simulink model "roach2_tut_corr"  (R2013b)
settings: Solver=VariableStepDiscrete  SolverMode=SingleTasking  StartTime=0.0  StopTime=100  RelTol=1e-3
undefined symbols (not defined in the file): add_latency, addr_width, Bit, bitfield, BitWidth, bram_latency, burst_size, casper_library_scopes, conv_latency, data_width, DelayLen, fan_latency, FFTSize, FFTStage, getfield, increment, led, Location, Lower, mult_latency, mux_latency, n_bits, n_bits_data, n_inputs, n_streams, n_taps, neg_latency, negate_latency, nsamples, pfb_size, pulse_len, reset_period, ROACH, ROACH2, snapshot, sx475t, sync_period, sync_period_bits, Upper, UseCounter, Width
libraries: xbsIndex_r4 x24444, casper_library_misc x73, xbsReplacements_r4 x34, casper_library_delays x14, xps_library x7
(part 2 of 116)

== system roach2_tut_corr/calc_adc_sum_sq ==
  In1 : Inport
  In2 : Inport  Port=2
  In3 : Inport  Port=3
  In4 : Inport  Port=4
  Accumulator : xbsIndex_r4/Accumulator  operation=Add  n_bits=32  overflow=Wrap  scale=1  rst=on  infoeditControl=reset for floating point data type must be asserted for a minimum of 2 cycles  hasbypass=off  en=off  latency=0  dbl_ovrd=off  msb_inp=100  msb=100  lsb=-100  use_behavioral_HDL=on  implementation=Fabric  block_type=accum
  Convert1 : xbsIndex_r4/Convert  gui_display_data_type=Fixed-point  arith_type=Unsigned  n_bits=32  bin_pt=0  float_type=Single  exp_bits=8  fraction_bits=24  quantization=Truncate  overflow=Wrap  en=off  latency=0  dbl_ovrd=off  pipeline=off  block_type=convert
  Convert2 : xbsIndex_r4/Convert  gui_display_data_type=Boolean  arith_type=Boolean  n_bits=32  bin_pt=0  float_type=Single  exp_bits=8  fraction_bits=24  quantization=Truncate  overflow=Wrap  en=off  latency=0  dbl_ovrd=off  pipeline=off  block_type=convert
  Counter : xbsIndex_r4/Counter  cnt_type=Free Running  cnt_to=Inf  operation=Up  start_count=0  cnt_by_val=1  arith_type=Unsigned  n_bits=2  bin_pt=0  load_pin=off  rst=off  en=off  explicit_period=off  period=1  dbl_ovrd=off  use_behavioral_HDL=off  implementation=Fabric  use_rpm=on  block_type=counter
  Counter1 : xbsIndex_r4/Counter  cnt_type=Free Running  cnt_to=Inf  operation=Up  start_count=0  cnt_by_val=1  arith_type=Unsigned  n_bits=16  bin_pt=0  load_pin=off  rst=off  en=off  explicit_period=off  period=1  dbl_ovrd=off  use_behavioral_HDL=off  implementation=Fabric  use_rpm=on  block_type=counter
  Mult : xbsIndex_r4/Mult  precision=Full  arith_type="Signed  (2's comp)"  n_bits=8  bin_pt=2  quantization=Truncate  overflow=Wrap  en=off  latency=2  dbl_ovrd=off  use_behavioral_HDL=on  opt=Speed  use_embedded=on  optimum_pipeline=off  pipeline=on  use_rpm=on  placement_style=Rectangular shape  block_type=mult
  Mux : xbsIndex_r4/Mux  inputs=4  en=off  latency=1  precision=Full  arith_type="Signed  (2's comp)"  n_bits=8  bin_pt=2  quantization=Truncate  overflow=Wrap  dbl_ovrd=off  block_type=mux
  Register : xbsIndex_r4/Register  init=0  rst=off  en=on  dbl_ovrd=off  block_type=register
  Slice : xbsIndex_r4/Slice  nbits=1  boolean_output=off  mode=Upper Bit Location + Width  bit1=0  base1=MSB of Input  bit0=0  base0=LSB of Input  dbl_ovrd=off  block_type=slice
  edge_detect2 : Subsystem  AncestorBlock=casper_library_misc/edge_detect
  sum_sq : Outport
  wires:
  Mult/1 -> Accumulator/1
  Accumulator/1 -> Register/1
  Register/1 -> Convert1/1
  Mux/1 -> Mult/1, Mult/2
  Counter/1 -> Mux/1
  Counter1/1 -> Slice/1
  Slice/1 -> edge_detect2/1(in)
  edge_detect2/1(out) -> Convert2/1
  In1/1 -> Mux/2
  In3/1 -> Mux/3
  In2/1 -> Mux/4
  In4/1 -> Mux/5
  Convert1/1 -> sum_sq/1
  Convert2/1 -> Accumulator/2, Register/2

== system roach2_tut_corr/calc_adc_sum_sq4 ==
  In1 : Inport
  In2 : Inport  Port=2
  In3 : Inport  Port=3
  In4 : Inport  Port=4
  Accumulator : xbsIndex_r4/Accumulator  operation=Add  n_bits=32  overflow=Wrap  scale=1  rst=on  infoeditControl=reset for floating point data type must be asserted for a minimum of 2 cycles  hasbypass=off  en=off  latency=0  dbl_ovrd=off  msb_inp=100  msb=100  lsb=-100  use_behavioral_HDL=on  implementation=Fabric  block_type=accum
  Convert1 : xbsIndex_r4/Convert  gui_display_data_type=Fixed-point  arith_type=Unsigned  n_bits=32  bin_pt=0  float_type=Single  exp_bits=8  fraction_bits=24  quantization=Truncate  overflow=Wrap  en=off  latency=0  dbl_ovrd=off  pipeline=off  block_type=convert
  Convert2 : xbsIndex_r4/Convert  gui_display_data_type=Boolean  arith_type=Boolean  n_bits=32  bin_pt=0  float_type=Single  exp_bits=8  fraction_bits=24  quantization=Truncate  overflow=Wrap  en=off  latency=0  dbl_ovrd=off  pipeline=off  block_type=convert
  Counter : xbsIndex_r4/Counter  cnt_type=Free Running  cnt_to=Inf  operation=Up  start_count=0  cnt_by_val=1  arith_type=Unsigned  n_bits=2  bin_pt=0  load_pin=off  rst=off  en=off  explicit_period=off  period=1  dbl_ovrd=off  use_behavioral_HDL=off  implementation=Fabric  use_rpm=on  block_type=counter
  Counter1 : xbsIndex_r4/Counter  cnt_type=Free Running  cnt_to=Inf  operation=Up  start_count=0  cnt_by_val=1  arith_type=Unsigned  n_bits=16  bin_pt=0  load_pin=off  rst=off  en=off  explicit_period=off  period=1  dbl_ovrd=off  use_behavioral_HDL=off  implementation=Fabric  use_rpm=on  block_type=counter
  Mult : xbsIndex_r4/Mult  precision=Full  arith_type="Signed  (2's comp)"  n_bits=8  bin_pt=2  quantization=Truncate  overflow=Wrap  en=off  latency=2  dbl_ovrd=off  use_behavioral_HDL=on  opt=Speed  use_embedded=on  optimum_pipeline=off  pipeline=on  use_rpm=on  placement_style=Rectangular shape  block_type=mult
  Mux : xbsIndex_r4/Mux  inputs=4  en=off  latency=1  precision=Full  arith_type="Signed  (2's comp)"  n_bits=8  bin_pt=2  quantization=Truncate  overflow=Wrap  dbl_ovrd=off  block_type=mux
  Register : xbsIndex_r4/Register  init=0  rst=off  en=on  dbl_ovrd=off  block_type=register
  Slice : xbsIndex_r4/Slice  nbits=1  boolean_output=off  mode=Upper Bit Location + Width  bit1=0  base1=MSB of Input  bit0=0  base0=LSB of Input  dbl_ovrd=off  block_type=slice
  edge_detect2 : Subsystem  AncestorBlock=casper_library_misc/edge_detect
  sum_sq : Outport
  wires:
  Convert1/1 -> sum_sq/1
  In4/1 -> Mux/5
  In2/1 -> Mux/4
  In3/1 -> Mux/3
  In1/1 -> Mux/2
  edge_detect2/1(out) -> Convert2/1
  Slice/1 -> edge_detect2/1(in)
  Counter1/1 -> Slice/1
  Counter/1 -> Mux/1
  Mux/1 -> Mult/2, Mult/1
  Register/1 -> Convert1/1
  Accumulator/1 -> Register/1
  Mult/1 -> Accumulator/1
  Convert2/1 -> Register/2, Accumulator/2

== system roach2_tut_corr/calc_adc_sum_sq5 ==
  In1 : Inport
  In2 : Inport  Port=2
  In3 : Inport  Port=3
  In4 : Inport  Port=4
  Accumulator : xbsIndex_r4/Accumulator  operation=Add  n_bits=32  overflow=Wrap  scale=1  rst=on  infoeditControl=reset for floating point data type must be asserted for a minimum of 2 cycles  hasbypass=off  en=off  latency=0  dbl_ovrd=off  msb_inp=100  msb=100  lsb=-100  use_behavioral_HDL=on  implementation=Fabric  block_type=accum
  Convert1 : xbsIndex_r4/Convert  gui_display_data_type=Fixed-point  arith_type=Unsigned  n_bits=32  bin_pt=0  float_type=Single  exp_bits=8  fraction_bits=24  quantization=Truncate  overflow=Wrap  en=off  latency=0  dbl_ovrd=off  pipeline=off  block_type=convert
  Convert2 : xbsIndex_r4/Convert  gui_display_data_type=Boolean  arith_type=Boolean  n_bits=32  bin_pt=0  float_type=Single  exp_bits=8  fraction_bits=24  quantization=Truncate  overflow=Wrap  en=off  latency=0  dbl_ovrd=off  pipeline=off  block_type=convert
  Counter : xbsIndex_r4/Counter  cnt_type=Free Running  cnt_to=Inf  operation=Up  start_count=0  cnt_by_val=1  arith_type=Unsigned  n_bits=2  bin_pt=0  load_pin=off  rst=off  en=off  explicit_period=off  period=1  dbl_ovrd=off  use_behavioral_HDL=off  implementation=Fabric  use_rpm=on  block_type=counter
  Counter1 : xbsIndex_r4/Counter  cnt_type=Free Running  cnt_to=Inf  operation=Up  start_count=0  cnt_by_val=1  arith_type=Unsigned  n_bits=16  bin_pt=0  load_pin=off  rst=off  en=off  explicit_period=off  period=1  dbl_ovrd=off  use_behavioral_HDL=off  implementation=Fabric  use_rpm=on  block_type=counter
  Mult : xbsIndex_r4/Mult  precision=Full  arith_type="Signed  (2's comp)"  n_bits=8  bin_pt=2  quantization=Truncate  overflow=Wrap  en=off  latency=2  dbl_ovrd=off  use_behavioral_HDL=on  opt=Speed  use_embedded=on  optimum_pipeline=off  pipeline=on  use_rpm=on  placement_style=Rectangular shape  block_type=mult
  Mux : xbsIndex_r4/Mux  inputs=4  en=off  latency=1  precision=Full  arith_type="Signed  (2's comp)"  n_bits=8  bin_pt=2  quantization=Truncate  overflow=Wrap  dbl_ovrd=off  block_type=mux
  Register : xbsIndex_r4/Register  init=0  rst=off  en=on  dbl_ovrd=off  block_type=register
  Slice : xbsIndex_r4/Slice  nbits=1  boolean_output=off  mode=Upper Bit Location + Width  bit1=0  base1=MSB of Input  bit0=0  base0=LSB of Input  dbl_ovrd=off  block_type=slice
  edge_detect2 : Subsystem  AncestorBlock=casper_library_misc/edge_detect
  sum_sq : Outport
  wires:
  Mult/1 -> Accumulator/1
  Accumulator/1 -> Register/1
  Register/1 -> Convert1/1
  Mux/1 -> Mult/1, Mult/2
  Counter/1 -> Mux/1
  Counter1/1 -> Slice/1
  Slice/1 -> edge_detect2/1(in)
  edge_detect2/1(out) -> Convert2/1
  In1/1 -> Mux/2
  In3/1 -> Mux/3
  In2/1 -> Mux/4
  In4/1 -> Mux/5
  Convert1/1 -> sum_sq/1
  Convert2/1 -> Accumulator/2, Register/2

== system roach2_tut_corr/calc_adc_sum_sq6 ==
  In1 : Inport
  In2 : Inport  Port=2
  In3 : Inport  Port=3
  In4 : Inport  Port=4
  Accumulator : xbsIndex_r4/Accumulator  operation=Add  n_bits=32  overflow=Wrap  scale=1  rst=on  infoeditControl=reset for floating point data type must be asserted for a minimum of 2 cycles  hasbypass=off  en=off  latency=0  dbl_ovrd=off  msb_inp=100  msb=100  lsb=-100  use_behavioral_HDL=on  implementation=Fabric  block_type=accum
  Convert1 : xbsIndex_r4/Convert  gui_display_data_type=Fixed-point  arith_type=Unsigned  n_bits=32  bin_pt=0  float_type=Single  exp_bits=8  fraction_bits=24  quantization=Truncate  overflow=Wrap  en=off  latency=0  dbl_ovrd=off  pipeline=off  block_type=convert
  Convert2 : xbsIndex_r4/Convert  gui_display_data_type=Boolean  arith_type=Boolean  n_bits=32  bin_pt=0  float_type=Single  exp_bits=8  fraction_bits=24  quantization=Truncate  overflow=Wrap  en=off  latency=0  dbl_ovrd=off  pipeline=off  block_type=convert
  Counter : xbsIndex_r4/Counter  cnt_type=Free Running  cnt_to=Inf  operation=Up  start_count=0  cnt_by_val=1  arith_type=Unsigned  n_bits=2  bin_pt=0  load_pin=off  rst=off  en=off  explicit_period=off  period=1  dbl_ovrd=off  use_behavioral_HDL=off  implementation=Fabric  use_rpm=on  block_type=counter
  Counter1 : xbsIndex_r4/Counter  cnt_type=Free Running  cnt_to=Inf  operation=Up  start_count=0  cnt_by_val=1  arith_type=Unsigned  n_bits=16  bin_pt=0  load_pin=off  rst=off  en=off  explicit_period=off  period=1  dbl_ovrd=off  use_behavioral_HDL=off  implementation=Fabric  use_rpm=on  block_type=counter
  Mult : xbsIndex_r4/Mult  precision=Full  arith_type="Signed  (2's comp)"  n_bits=8  bin_pt=2  quantization=Truncate  overflow=Wrap  en=off  latency=2  dbl_ovrd=off  use_behavioral_HDL=on  opt=Speed  use_embedded=on  optimum_pipeline=off  pipeline=on  use_rpm=on  placement_style=Rectangular shape  block_type=mult
  Mux : xbsIndex_r4/Mux  inputs=4  en=off  latency=1  precision=Full  arith_type="Signed  (2's comp)"  n_bits=8  bin_pt=2  quantization=Truncate  overflow=Wrap  dbl_ovrd=off  block_type=mux
  Register : xbsIndex_r4/Register  init=0  rst=off  en=on  dbl_ovrd=off  block_type=register
  Slice : xbsIndex_r4/Slice  nbits=1  boolean_output=off  mode=Upper Bit Location + Width  bit1=0  base1=MSB of Input  bit0=0  base0=LSB of Input  dbl_ovrd=off  block_type=slice
  edge_detect2 : Subsystem  AncestorBlock=casper_library_misc/edge_detect
  sum_sq : Outport
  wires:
  Convert1/1 -> sum_sq/1
  In4/1 -> Mux/5
  In2/1 -> Mux/4
  In3/1 -> Mux/3
  In1/1 -> Mux/2
  edge_detect2/1(out) -> Convert2/1
  Slice/1 -> edge_detect2/1(in)
  Counter1/1 -> Slice/1
  Counter/1 -> Mux/1
  Mux/1 -> Mult/2, Mult/1
  Register/1 -> Convert1/1
  Accumulator/1 -> Register/1
  Mult/1 -> Accumulator/1
  Convert2/1 -> Register/2, Accumulator/2

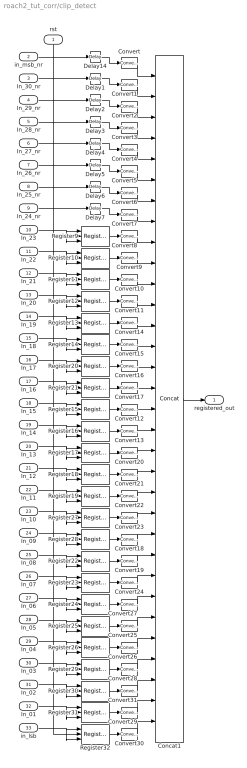
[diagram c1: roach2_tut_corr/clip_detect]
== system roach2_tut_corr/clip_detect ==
  rst : Inport
  in_msb_nr : Inport  Port=2
  In_30_nr : Inport  Port=3
  In_29_nr : Inport  Port=4
  In_28_nr : Inport  Port=5
  In_27_nr : Inport  Port=6
  In_26_nr : Inport  Port=7
  In_25_nr : Inport  Port=8
  In_24_nr : Inport  Port=9
  In_23 : Inport  Port=10
  In_22 : Inport  Port=11
  In_21 : Inport  Port=12
  In_20 : Inport  Port=13
  In_19 : Inport  Port=14
  In_18 : Inport  Port=15
  In_17 : Inport  Port=16
  In_16 : Inport  Port=17
  In_15 : Inport  Port=18
  In_14 : Inport  Port=19
  In_13 : Inport  Port=20
  In_12 : Inport  Port=21
  In_11 : Inport  Port=22
  In_10 : Inport  Port=23
  In_09 : Inport  Port=24
  In_08 : Inport  Port=25
  In_07 : Inport  Port=26
  In_06 : Inport  Port=27
  In_05 : Inport  Port=28
  In_04 : Inport  Port=29
  In_03 : Inport  Port=30
  In_02 : Inport  Port=31
  In_01 : Inport  Port=32
  in_lsb : Inport  Port=33
  Concat1 : xbsIndex_r4/Concat  num_inputs=32  dbl_ovrd=off  block_type=concat
  Convert{,1..31} (32 alike) : xbsIndex_r4/Convert  gui_display_data_type=Fixed-point  arith_type=Unsigned  n_bits=1  bin_pt=0  float_type=Single  exp_bits=8  fraction_bits=24  quantization=Truncate  overflow=Wrap  en=off  latency=0  dbl_ovrd=off  pipeline=off  block_type=convert
  Delay{1..7,14} (8 alike) : xbsIndex_r4/Delay  rst=off  infoeditControl=Selection of Reset will increase slice count due to use of real FFs and instead of SRLs  en=off  latency=1  dbl_ovrd=off  reg_retiming=on  block_type=delay
  Register{9..32} (24 alike) : xbsIndex_r4/Register  init=0  rst=on  en=on  dbl_ovrd=off  block_type=register
  registered_out : Outport
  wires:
  Concat1/1 -> registered_out/1
  rst/1 -> Register11/2, Register12/2, Register14/2, Register20/2, Register21/2, Register15/2, Register16/2, Register17/2, Register19/2, Register23/2, Register24/2, Register26/2, Register29/2, Register30/2, Register31/2, Register32/2, Register25/2, Register22/2, Register28/2, Register27/2, Register18/2, Register13/2, Register10/2, Register9/2
  in_msb_nr/1 -> Delay14/1
  Convert/1 -> Concat1/1
  In_30_nr/1 -> Delay1/1
  Convert1/1 -> Concat1/2
  Convert2/1 -> Concat1/3
  Convert3/1 -> Concat1/4
  Convert4/1 -> Concat1/5
  Convert5/1 -> Concat1/6
  Convert6/1 -> Concat1/7
  Convert7/1 -> Concat1/8
  Convert8/1 -> Concat1/9
  Convert9/1 -> Concat1/10
  Convert10/1 -> Concat1/11
  Convert11/1 -> Concat1/12
  Convert14/1 -> Concat1/13
  Convert15/1 -> Concat1/14
  Convert16/1 -> Concat1/15
  Convert17/1 -> Concat1/16
  Convert12/1 -> Concat1/17
  Convert13/1 -> Concat1/18
  Convert20/1 -> Concat1/19
  Convert21/1 -> Concat1/20
  Convert22/1 -> Concat1/21
  Convert23/1 -> Concat1/22
  Convert18/1 -> Concat1/23
  Convert19/1 -> Concat1/24
  Convert24/1 -> Concat1/25
  In_29_nr/1 -> Delay2/1
  In_28_nr/1 -> Delay3/1
  In_27_nr/1 -> Delay4/1
  In_26_nr/1 -> Delay5/1
  In_25_nr/1 -> Delay6/1
  In_24_nr/1 -> Delay7/1
  Register9/1 -> Convert8/1
  Register10/1 -> Convert9/1
  Register11/1 -> Convert10/1
  Register12/1 -> Convert11/1
  Register13/1 -> Convert14/1
  Register14/1 -> Convert15/1
  Register20/1 -> Convert16/1
  Register21/1 -> Convert17/1
  Register15/1 -> Convert12/1
  Register16/1 -> Convert13/1
  Register17/1 -> Convert20/1
  Register18/1 -> Convert21/1
  Register19/1 -> Convert22/1
  Register27/1 -> Convert23/1
  Register28/1 -> Convert18/1
  Register22/1 -> Convert19/1
  Register23/1 -> Convert24/1
  In_23/1 -> Register9/3, Register9/1
  In_22/1 -> Register10/3, Register10/1
  In_21/1 -> Register11/1, Register11/3
  In_20/1 -> Register12/3, Register12/1
  In_19/1 -> Register13/1, Register13/3
  In_18/1 -> Register14/3, Register14/1
  In_17/1 -> Register20/1, Register20/3
  In_16/1 -> Register21/1, Register21/3
  In_15/1 -> Register15/1, Register15/3
  In_14/1 -> Register16/3, Register16/1
  In_13/1 -> Register17/1, Register17/3
  In_12/1 -> Register18/3, Register18/1
  In_11/1 -> Register19/1, Register19/3
  In_10/1 -> Register27/3, Register27/1
  In_09/1 -> Register28/3, Register28/1
  In_08/1 -> Register22/3, Register22/1
  In_07/1 -> Register23/1, Register23/3
  In_06/1 -> Register24/3, Register24/1
  In_05/1 -> Register25/1, Register25/3
  In_04/1 -> Register26/3, Register26/1
  In_03/1 -> Register29/1, Register29/3
  In_02/1 -> Register30/3, Register30/1
  In_01/1 -> Register31/1, Register31/3
  Convert27/1 -> Concat1/26
  Convert25/1 -> Concat1/27
  Convert26/1 -> Concat1/28
  Convert28/1 -> Concat1/29
  Register24/1 -> Convert27/1
  Register25/1 -> Convert25/1
  Register26/1 -> Convert26/1
  Register29/1 -> Convert28/1
  Convert31/1 -> Concat1/30
  Convert29/1 -> Concat1/31
  Convert30/1 -> Concat1/32
  in_lsb/1 -> Register32/3, Register32/1
  Register30/1 -> Convert31/1
  Register31/1 -> Convert29/1
  Register32/1 -> Convert30/1
  Delay14/1 -> Convert/1
  Delay1/1 -> Convert1/1
  Delay2/1 -> Convert2/1
  Delay3/1 -> Convert3/1
  Delay4/1 -> Convert4/1
  Delay5/1 -> Convert5/1
  Delay6/1 -> Convert6/1
  Delay7/1 -> Convert7/1

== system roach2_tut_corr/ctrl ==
  sim_1 : Inport
  io_delay : xbsIndex_r4/Delay  rst=off  infoeditControl=Selection of Reset will increase slice count due to use of real FFs and instead of SRLs  en=off  latency=0  dbl_ovrd=off  reg_retiming=on  block_type=delay
  reint1 : xbsIndex_r4/Reinterpret  force_arith_type=on  arith_type=Unsigned  force_bin_pt=on  bin_pt=0  block_type=reinterpret
  roach2_tut_corr_ctrl_user_data_out : xbsIndex_r4/Gateway In  gui_display_data_type=Fixed-point  arith_type=Unsigned  n_bits=32  bin_pt=0  preci_type=Single  exp_width=8  frac_width=24  quantization="Round  (unbiased: +/- Inf)"  overflow=Saturate  period=1  dbl_ovrd=off  timing_constraint=None  locs_specified=off  LOCs={}  UseAsADC=off  ADCChannel='1'  inherit_from_input=off  hdl_port=on  block_type=gatewayin
  slice_reg : xbsIndex_r4/Slice  nbits=32  boolean_output=off  mode=Lower Bit Location + Width  bit1=0  base1=MSB of Input  bit0=0  base0=LSB of Input  dbl_ovrd=off  block_type=slice
  in_reg : Outport
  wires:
  roach2_tut_corr_ctrl_user_data_out/1 -> io_delay/1
  sim_1/1 -> roach2_tut_corr_ctrl_user_data_out/1
  io_delay/1 -> slice_reg/1
  slice_reg/1 -> reint1/1
  reint1/1 -> in_reg/1

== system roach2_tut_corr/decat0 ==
  In1 : Inport
  Reinterpret{1..4} (4 alike) : xbsIndex_r4/Reinterpret  force_arith_type=on  arith_type="Signed  (2's comp)"  force_bin_pt=on  bin_pt=0  block_type=reinterpret
  Slice15 : xbsIndex_r4/Slice  nbits=8  boolean_output=off  mode=Lower Bit Location + Width  bit1=0  base1=MSB of Input  bit0=8  base0=LSB of Input  dbl_ovrd=off  block_type=slice
  Slice16 : xbsIndex_r4/Slice  nbits=8  boolean_output=off  mode=Lower Bit Location + Width  bit1=0  base1=MSB of Input  bit0=16  base0=LSB of Input  dbl_ovrd=off  block_type=slice
  Slice17 : xbsIndex_r4/Slice  nbits=8  boolean_output=off  mode=Lower Bit Location + Width  bit1=0  base1=MSB of Input  bit0=24  base0=LSB of Input  dbl_ovrd=off  block_type=slice
  Slice9 : xbsIndex_r4/Slice  nbits=8  boolean_output=off  mode=Lower Bit Location + Width  bit1=0  base1=MSB of Input  bit0=0  base0=LSB of Input  dbl_ovrd=off  block_type=slice
  Out1 : Outport
  Out2 : Outport  Port=2
  Out3 : Outport  Port=3
  Out4 : Outport  Port=4
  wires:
  Reinterpret4/1 -> Out4/1
  Reinterpret3/1 -> Out3/1
  Reinterpret1/1 -> Out2/1
  Reinterpret2/1 -> Out1/1
  Slice9/1 -> Reinterpret4/1
  Slice15/1 -> Reinterpret3/1
  Slice16/1 -> Reinterpret1/1
  Slice17/1 -> Reinterpret2/1
  In1/1 -> Slice15/1, Slice9/1, Slice16/1, Slice17/1

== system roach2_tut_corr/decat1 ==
  In1 : Inport
  Reinterpret{1..4} (4 alike) : xbsIndex_r4/Reinterpret  force_arith_type=on  arith_type="Signed  (2's comp)"  force_bin_pt=on  bin_pt=0  block_type=reinterpret
  Slice15 : xbsIndex_r4/Slice  nbits=8  boolean_output=off  mode=Lower Bit Location + Width  bit1=0  base1=MSB of Input  bit0=8  base0=LSB of Input  dbl_ovrd=off  block_type=slice
  Slice16 : xbsIndex_r4/Slice  nbits=8  boolean_output=off  mode=Lower Bit Location + Width  bit1=0  base1=MSB of Input  bit0=16  base0=LSB of Input  dbl_ovrd=off  block_type=slice
  Slice17 : xbsIndex_r4/Slice  nbits=8  boolean_output=off  mode=Lower Bit Location + Width  bit1=0  base1=MSB of Input  bit0=24  base0=LSB of Input  dbl_ovrd=off  block_type=slice
  Slice9 : xbsIndex_r4/Slice  nbits=8  boolean_output=off  mode=Lower Bit Location + Width  bit1=0  base1=MSB of Input  bit0=0  base0=LSB of Input  dbl_ovrd=off  block_type=slice
  Out1 : Outport
  Out2 : Outport  Port=2
  Out3 : Outport  Port=3
  Out4 : Outport  Port=4
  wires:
  In1/1 -> Slice17/1, Slice16/1, Slice9/1, Slice15/1
  Slice17/1 -> Reinterpret2/1
  Slice16/1 -> Reinterpret1/1
  Slice15/1 -> Reinterpret3/1
  Slice9/1 -> Reinterpret4/1
  Reinterpret2/1 -> Out1/1
  Reinterpret1/1 -> Out2/1
  Reinterpret3/1 -> Out3/1
  Reinterpret4/1 -> Out4/1

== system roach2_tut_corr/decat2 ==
  In1 : Inport
  Reinterpret{1..4} (4 alike) : xbsIndex_r4/Reinterpret  force_arith_type=on  arith_type="Signed  (2's comp)"  force_bin_pt=on  bin_pt=0  block_type=reinterpret
  Slice15 : xbsIndex_r4/Slice  nbits=8  boolean_output=off  mode=Lower Bit Location + Width  bit1=0  base1=MSB of Input  bit0=8  base0=LSB of Input  dbl_ovrd=off  block_type=slice
  Slice16 : xbsIndex_r4/Slice  nbits=8  boolean_output=off  mode=Lower Bit Location + Width  bit1=0  base1=MSB of Input  bit0=16  base0=LSB of Input  dbl_ovrd=off  block_type=slice
  Slice17 : xbsIndex_r4/Slice  nbits=8  boolean_output=off  mode=Lower Bit Location + Width  bit1=0  base1=MSB of Input  bit0=24  base0=LSB of Input  dbl_ovrd=off  block_type=slice
  Slice9 : xbsIndex_r4/Slice  nbits=8  boolean_output=off  mode=Lower Bit Location + Width  bit1=0  base1=MSB of Input  bit0=0  base0=LSB of Input  dbl_ovrd=off  block_type=slice
  Out1 : Outport
  Out2 : Outport  Port=2
  Out3 : Outport  Port=3
  Out4 : Outport  Port=4
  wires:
  Reinterpret4/1 -> Out4/1
  Reinterpret3/1 -> Out3/1
  Reinterpret1/1 -> Out2/1
  Reinterpret2/1 -> Out1/1
  Slice9/1 -> Reinterpret4/1
  Slice15/1 -> Reinterpret3/1
  Slice16/1 -> Reinterpret1/1
  Slice17/1 -> Reinterpret2/1
  In1/1 -> Slice15/1, Slice9/1, Slice16/1, Slice17/1

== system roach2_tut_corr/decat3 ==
  In1 : Inport
  Reinterpret{1..4} (4 alike) : xbsIndex_r4/Reinterpret  force_arith_type=on  arith_type="Signed  (2's comp)"  force_bin_pt=on  bin_pt=0  block_type=reinterpret
  Slice15 : xbsIndex_r4/Slice  nbits=8  boolean_output=off  mode=Lower Bit Location + Width  bit1=0  base1=MSB of Input  bit0=8  base0=LSB of Input  dbl_ovrd=off  block_type=slice
  Slice16 : xbsIndex_r4/Slice  nbits=8  boolean_output=off  mode=Lower Bit Location + Width  bit1=0  base1=MSB of Input  bit0=16  base0=LSB of Input  dbl_ovrd=off  block_type=slice
  Slice17 : xbsIndex_r4/Slice  nbits=8  boolean_output=off  mode=Lower Bit Location + Width  bit1=0  base1=MSB of Input  bit0=24  base0=LSB of Input  dbl_ovrd=off  block_type=slice
  Slice9 : xbsIndex_r4/Slice  nbits=8  boolean_output=off  mode=Lower Bit Location + Width  bit1=0  base1=MSB of Input  bit0=0  base0=LSB of Input  dbl_ovrd=off  block_type=slice
  Out1 : Outport
  Out2 : Outport  Port=2
  Out3 : Outport  Port=3
  Out4 : Outport  Port=4
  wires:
  In1/1 -> Slice17/1, Slice16/1, Slice9/1, Slice15/1
  Slice17/1 -> Reinterpret2/1
  Slice16/1 -> Reinterpret1/1
  Slice15/1 -> Reinterpret3/1
  Slice9/1 -> Reinterpret4/1
  Reinterpret2/1 -> Out1/1
  Reinterpret1/1 -> Out2/1
  Reinterpret3/1 -> Out3/1
  Reinterpret4/1 -> Out4/1

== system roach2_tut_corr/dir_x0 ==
  new_acc : Inport
  a : Inport  Port=2
  b : Inport  Port=3
  c : Inport  Port=4
  d : Inport  Port=5
  aa : Subsystem
  ab : Subsystem
  ac : Subsystem
  ad : Subsystem
  bb : Subsystem
  bc : Subsystem
  bd : Subsystem
  cc : Subsystem
  cd : Subsystem
  dd : Subsystem
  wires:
  a/1 -> aa/2(c+di), aa/1(a+bi), ab/1(a+bi), ad/2(c+di), ac/1(a+bi)
  new_acc/1 -> bb/3(new_acc), ab/3(new_acc), cc/3(new_acc), bc/3(new_acc), ac/3(new_acc), dd/3(new_acc), cd/3(new_acc), bd/3(new_acc), ad/3(new_acc), aa/3(new_acc)
  c/1 -> ac/2(c+di), bc/2(c+di), cd/1(a+bi), cc/1(a+bi), cc/2(c+di)
  d/1 -> ad/1(a+bi), bd/2(c+di), cd/2(c+di), dd/1(a+bi), dd/2(c+di)
  b/1 -> ab/2(c+di), bb/2(c+di), bb/1(a+bi), bd/1(a+bi), bc/1(a+bi)

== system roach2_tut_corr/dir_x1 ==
  new_acc : Inport
  a : Inport  Port=2
  b : Inport  Port=3
  c : Inport  Port=4
  d : Inport  Port=5
  aa : Subsystem
  ab : Subsystem
  ac : Subsystem
  ad : Subsystem
  bb : Subsystem
  bc : Subsystem
  bd : Subsystem
  cc : Subsystem
  cd : Subsystem
  dd : Subsystem
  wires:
  b/1 -> bc/1(a+bi), bd/1(a+bi), bb/1(a+bi), bb/2(c+di), ab/2(c+di)
  d/1 -> dd/2(c+di), dd/1(a+bi), cd/2(c+di), bd/2(c+di), ad/1(a+bi)
  c/1 -> cc/2(c+di), cc/1(a+bi), cd/1(a+bi), bc/2(c+di), ac/2(c+di)
  new_acc/1 -> aa/3(new_acc), ad/3(new_acc), bd/3(new_acc), cd/3(new_acc), dd/3(new_acc), ac/3(new_acc), bc/3(new_acc), cc/3(new_acc), ab/3(new_acc), bb/3(new_acc)
  a/1 -> ac/1(a+bi), ad/2(c+di), ab/1(a+bi), aa/1(a+bi), aa/2(c+di)

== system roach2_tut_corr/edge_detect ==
  in : Inport
  Delay : xbsIndex_r4/Delay  rst=off  infoeditControl=Selection of Reset will increase slice count due to use of real FFs and instead of SRLs  en=off  latency=1  dbl_ovrd=off  reg_retiming=on  block_type=delay
  Inverter : xbsIndex_r4/Inverter  en=off  latency=0  dbl_ovrd=off  block_type=inv
  edge_op : xbsIndex_r4/Logical  logical_function=NOR  inputs=2  en=off  latency=0  precision=Full  arith_type=Unsigned  n_bits=8  bin_pt=2  align_bp=on  dbl_ovrd=off  block_type=logical
  out : Outport
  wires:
  Inverter/1 -> edge_op/1
  edge_op/1 -> out/1
  in/1 -> Inverter/1, Delay/1
  Delay/1 -> edge_op/2

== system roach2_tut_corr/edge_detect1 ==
  in : Inport
  Delay : xbsIndex_r4/Delay  rst=off  infoeditControl=Selection of Reset will increase slice count due to use of real FFs and instead of SRLs  en=off  latency=1  dbl_ovrd=off  reg_retiming=on  block_type=delay
  Inverter : xbsIndex_r4/Inverter  en=off  latency=0  dbl_ovrd=off  block_type=inv
  edge_op : xbsIndex_r4/Logical  logical_function=NOR  inputs=2  en=off  latency=0  precision=Full  arith_type=Unsigned  n_bits=8  bin_pt=2  align_bp=on  dbl_ovrd=off  block_type=logical
  out : Outport
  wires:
  Inverter/1 -> edge_op/1
  edge_op/1 -> out/1
  in/1 -> Inverter/1, Delay/1
  Delay/1 -> edge_op/2

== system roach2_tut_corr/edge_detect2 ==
  in : Inport
  Delay : xbsIndex_r4/Delay  rst=off  infoeditControl=Selection of Reset will increase slice count due to use of real FFs and instead of SRLs  en=off  latency=1  dbl_ovrd=off  reg_retiming=on  block_type=delay
  Inverter : xbsIndex_r4/Inverter  en=off  latency=0  dbl_ovrd=off  block_type=inv
  edge_op : xbsIndex_r4/Logical  logical_function=NOR  inputs=2  en=off  latency=0  precision=Full  arith_type=Unsigned  n_bits=8  bin_pt=2  align_bp=on  dbl_ovrd=off  block_type=logical
  out : Outport
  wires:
  Inverter/1 -> edge_op/1
  edge_op/1 -> out/1
  in/1 -> Inverter/1, Delay/1
  Delay/1 -> edge_op/2

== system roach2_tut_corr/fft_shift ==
  sim_1 : Inport
  io_delay : xbsIndex_r4/Delay  rst=off  infoeditControl=Selection of Reset will increase slice count due to use of real FFs and instead of SRLs  en=off  latency=0  dbl_ovrd=off  reg_retiming=on  block_type=delay
  reint1 : xbsIndex_r4/Reinterpret  force_arith_type=on  arith_type=Unsigned  force_bin_pt=on  bin_pt=0  block_type=reinterpret
  roach2_tut_corr_fft_shift_user_data_out : xbsIndex_r4/Gateway In  gui_display_data_type=Fixed-point  arith_type=Unsigned  n_bits=32  bin_pt=0  preci_type=Single  exp_width=8  frac_width=24  quantization="Round  (unbiased: +/- Inf)"  overflow=Saturate  period=1  dbl_ovrd=off  timing_constraint=None  locs_specified=off  LOCs={}  UseAsADC=off  ADCChannel='1'  inherit_from_input=off  hdl_port=on  block_type=gatewayin
  slice_reg : xbsIndex_r4/Slice  nbits=32  boolean_output=off  mode=Lower Bit Location + Width  bit1=0  base1=MSB of Input  bit0=0  base0=LSB of Input  dbl_ovrd=off  block_type=slice
  in_reg : Outport
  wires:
  roach2_tut_corr_fft_shift_user_data_out/1 -> io_delay/1
  sim_1/1 -> roach2_tut_corr_fft_shift_user_data_out/1
  io_delay/1 -> slice_reg/1
  slice_reg/1 -> reint1/1
  reint1/1 -> in_reg/1

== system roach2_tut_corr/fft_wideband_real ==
  sync : Inport
  shift : Inport  Port=2
  in00 : Inport  Port=3
  in01 : Inport  Port=4
  in02 : Inport  Port=5
  in03 : Inport  Port=6
  in10 : Inport  Port=7
  in11 : Inport  Port=8
  in12 : Inport  Port=9
  in13 : Inport  Port=10
  in20 : Inport  Port=11
  in21 : Inport  Port=12
  in22 : Inport  Port=13
  in23 : Inport  Port=14
  in30 : Inport  Port=15
  in31 : Inport  Port=16
  in32 : Inport  Port=17
  in33 : Inport  Port=18
  del_4x_pol0 : Subsystem  AncestorBlock=casper_library_delays/pipeline
  del_4x_pol1 : Subsystem  AncestorBlock=casper_library_delays/pipeline
  del_4x_pol10 : Subsystem  AncestorBlock=casper_library_delays/pipeline
  del_4x_pol11 : Subsystem  AncestorBlock=casper_library_delays/pipeline
  del_4x_pol12 : Subsystem  AncestorBlock=casper_library_delays/pipeline
  del_4x_pol13 : Subsystem  AncestorBlock=casper_library_delays/pipeline
  del_4x_pol14 : Subsystem  AncestorBlock=casper_library_delays/pipeline
  del_4x_pol15 : Subsystem  AncestorBlock=casper_library_delays/pipeline
  del_4x_pol2 : Subsystem  AncestorBlock=casper_library_delays/pipeline
  del_4x_pol3 : Subsystem  AncestorBlock=casper_library_delays/pipeline
  del_4x_pol4 : Subsystem  AncestorBlock=casper_library_delays/pipeline
  del_4x_pol5 : Subsystem  AncestorBlock=casper_library_delays/pipeline
  del_4x_pol6 : Subsystem  AncestorBlock=casper_library_delays/pipeline
  del_4x_pol7 : Subsystem  AncestorBlock=casper_library_delays/pipeline
  del_4x_pol8 : Subsystem  AncestorBlock=casper_library_delays/pipeline
  del_4x_pol9 : Subsystem  AncestorBlock=casper_library_delays/pipeline
  del_direct1 : Subsystem  AncestorBlock=casper_library_delays/pipeline
  del_direct10 : Subsystem  AncestorBlock=casper_library_delays/pipeline
  del_direct13 : Subsystem  AncestorBlock=casper_library_delays/pipeline
  del_direct14 : Subsystem  AncestorBlock=casper_library_delays/pipeline
  del_direct2 : Subsystem  AncestorBlock=casper_library_delays/pipeline
  del_direct5 : Subsystem  AncestorBlock=casper_library_delays/pipeline
  del_direct6 : Subsystem  AncestorBlock=casper_library_delays/pipeline
  del_direct9 : Subsystem  AncestorBlock=casper_library_delays/pipeline
  del_sync_4x : Subsystem  AncestorBlock=casper_library_delays/pipeline
  fft_biplex_real_4x : Subsystem  Tag=casper:fft_biplex_real_4x  AncestorBlock=casper_library_ffts/fft_biplex_real_4x
  fft_direct : Subsystem  AncestorBlock=casper_library_ffts/fft_direct
  fft_direct_sync_delay : Subsystem  AncestorBlock=casper_library_delays/pipeline
  fft_unscrambler : Subsystem  AncestorBlock=casper_library_ffts/fft_unscrambler
  in_del_4x_pol0 : Subsystem  AncestorBlock=casper_library_delays/pipeline
  in_del_4x_pol1 : Subsystem  AncestorBlock=casper_library_delays/pipeline
  in_del_4x_pol10 : Subsystem  AncestorBlock=casper_library_delays/pipeline
  in_del_4x_pol11 : Subsystem  AncestorBlock=casper_library_delays/pipeline
  in_del_4x_pol12 : Subsystem  AncestorBlock=casper_library_delays/pipeline
  in_del_4x_pol13 : Subsystem  AncestorBlock=casper_library_delays/pipeline
  in_del_4x_pol14 : Subsystem  AncestorBlock=casper_library_delays/pipeline
  in_del_4x_pol15 : Subsystem  AncestorBlock=casper_library_delays/pipeline
  in_del_4x_pol2 : Subsystem  AncestorBlock=casper_library_delays/pipeline
  in_del_4x_pol3 : Subsystem  AncestorBlock=casper_library_delays/pipeline
  in_del_4x_pol4 : Subsystem  AncestorBlock=casper_library_delays/pipeline
  in_del_4x_pol5 : Subsystem  AncestorBlock=casper_library_delays/pipeline
  in_del_4x_pol6 : Subsystem  AncestorBlock=casper_library_delays/pipeline
  in_del_4x_pol7 : Subsystem  AncestorBlock=casper_library_delays/pipeline
  in_del_4x_pol8 : Subsystem  AncestorBlock=casper_library_delays/pipeline
  in_del_4x_pol9 : Subsystem  AncestorBlock=casper_library_delays/pipeline
  in_del_sync_4x : Subsystem  AncestorBlock=casper_library_delays/pipeline
  of_or : xbsIndex_r4/Logical  logical_function=OR  inputs=2  en=off  latency=1  precision=Full  arith_type=Unsigned  n_bits=16  bin_pt=0  align_bp=on  dbl_ovrd=off  block_type=logical
  slice : xbsIndex_r4/Slice  nbits=2  boolean_output=off  mode=Lower Bit Location + Width  bit1=0  base1=MSB of Input  bit0=9  base0=LSB of Input  dbl_ovrd=off  block_type=slice
  t{0..7} (8 alike) : Terminator
  sync_out : Outport
  out00 : Outport  Port=2
  out01 : Outport  Port=3
  out10 : Outport  Port=4
  out11 : Outport  Port=5
  out20 : Outport  Port=6
  out21 : Outport  Port=7
  out30 : Outport  Port=8
  out31 : Outport  Port=9
  of : Outport  Port=10
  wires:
  sync/1 -> in_del_sync_4x/1(d)
  shift/1 -> fft_biplex_real_4x/2(shift), slice/1
  in_del_sync_4x/1(q) -> fft_biplex_real_4x/1(sync)
  fft_biplex_real_4x/1(sync_out) -> del_sync_4x/1(d)
  del_sync_4x/1(q) -> fft_direct/1(sync)
  fft_direct/4(out02) -> t0/1
  fft_direct/5(out03) -> t1/1
  fft_direct/8(out12) -> t2/1
  fft_direct/9(out13) -> t3/1
  fft_direct/12(out22) -> t4/1
  fft_direct/13(out23) -> t5/1
  fft_direct/16(out32) -> t6/1
  fft_direct/17(out33) -> t7/1
  fft_direct/1(sync_out) -> fft_direct_sync_delay/1(d)
  fft_direct_sync_delay/1(q) -> fft_unscrambler/1(sync)
  fft_unscrambler/1(sync_out) -> sync_out/1
  fft_direct/2(out00) -> del_direct1/1(d)
  del_direct1/1(q) -> fft_unscrambler/2(in00)
  fft_unscrambler/2(out00) -> out00/1
  fft_direct/3(out01) -> del_direct2/1(d)
  del_direct2/1(q) -> fft_unscrambler/3(in01)
  fft_unscrambler/3(out01) -> out01/1
  fft_direct/6(out10) -> del_direct5/1(d)
  del_direct5/1(q) -> fft_unscrambler/4(in10)
  fft_unscrambler/4(out10) -> out10/1
  fft_direct/7(out11) -> del_direct6/1(d)
  del_direct6/1(q) -> fft_unscrambler/5(in11)
  fft_unscrambler/5(out11) -> out11/1
  fft_direct/10(out20) -> del_direct9/1(d)
  del_direct9/1(q) -> fft_unscrambler/6(in20)
  fft_unscrambler/6(out20) -> out20/1
  fft_direct/11(out21) -> del_direct10/1(d)
  del_direct10/1(q) -> fft_unscrambler/7(in21)
  fft_unscrambler/7(out21) -> out21/1
  fft_direct/14(out30) -> del_direct13/1(d)
  del_direct13/1(q) -> fft_unscrambler/8(in30)
  fft_unscrambler/8(out30) -> out30/1
  fft_direct/15(out31) -> del_direct14/1(d)
  del_direct14/1(q) -> fft_unscrambler/9(in31)
  fft_unscrambler/9(out31) -> out31/1
  slice/1 -> fft_direct/2(shift)
  fft_biplex_real_4x/18(of) -> of_or/2
  fft_direct/18(of) -> of_or/1
  of_or/1 -> of/1
  in00/1 -> in_del_4x_pol0/1(d)
  in_del_4x_pol0/1(q) -> fft_biplex_real_4x/3(pol0_in)
  fft_biplex_real_4x/2(pol0_out) -> del_4x_pol0/1(d)
  del_4x_pol0/1(q) -> fft_direct/3(in00)
  in01/1 -> in_del_4x_pol1/1(d)
  in_del_4x_pol1/1(q) -> fft_biplex_real_4x/4(pol1_in)
  fft_biplex_real_4x/3(pol1_out) -> del_4x_pol1/1(d)
  del_4x_pol1/1(q) -> fft_direct/4(in01)
  in02/1 -> in_del_4x_pol2/1(d)
  in_del_4x_pol2/1(q) -> fft_biplex_real_4x/5(pol2_in)
  fft_biplex_real_4x/4(pol2_out) -> del_4x_pol2/1(d)
  del_4x_pol2/1(q) -> fft_direct/5(in02)
  in03/1 -> in_del_4x_pol3/1(d)
  in_del_4x_pol3/1(q) -> fft_biplex_real_4x/6(pol3_in)
  fft_biplex_real_4x/5(pol3_out) -> del_4x_pol3/1(d)
  del_4x_pol3/1(q) -> fft_direct/6(in03)
  in10/1 -> in_del_4x_pol4/1(d)
  in_del_4x_pol4/1(q) -> fft_biplex_real_4x/7(pol4_in)
  fft_biplex_real_4x/6(pol4_out) -> del_4x_pol4/1(d)
  del_4x_pol4/1(q) -> fft_direct/7(in10)
  in11/1 -> in_del_4x_pol5/1(d)
  in_del_4x_pol5/1(q) -> fft_biplex_real_4x/8(pol5_in)
  fft_biplex_real_4x/7(pol5_out) -> del_4x_pol5/1(d)
  del_4x_pol5/1(q) -> fft_direct/8(in11)
  in12/1 -> in_del_4x_pol6/1(d)
  in_del_4x_pol6/1(q) -> fft_biplex_real_4x/9(pol6_in)
  fft_biplex_real_4x/8(pol6_out) -> del_4x_pol6/1(d)
  del_4x_pol6/1(q) -> fft_direct/9(in12)
  in13/1 -> in_del_4x_pol7/1(d)
  in_del_4x_pol7/1(q) -> fft_biplex_real_4x/10(pol7_in)
  fft_biplex_real_4x/9(pol7_out) -> del_4x_pol7/1(d)
  del_4x_pol7/1(q) -> fft_direct/10(in13)
  in20/1 -> in_del_4x_pol8/1(d)
  in_del_4x_pol8/1(q) -> fft_biplex_real_4x/11(pol8_in)
  fft_biplex_real_4x/10(pol8_out) -> del_4x_pol8/1(d)
  del_4x_pol8/1(q) -> fft_direct/11(in20)
  in21/1 -> in_del_4x_pol9/1(d)
  in_del_4x_pol9/1(q) -> fft_biplex_real_4x/12(pol9_in)
  fft_biplex_real_4x/11(pol9_out) -> del_4x_pol9/1(d)
  del_4x_pol9/1(q) -> fft_direct/12(in21)
  in22/1 -> in_del_4x_pol10/1(d)
  in_del_4x_pol10/1(q) -> fft_biplex_real_4x/13(pol10_in)
  fft_biplex_real_4x/12(pol10_out) -> del_4x_pol10/1(d)
  del_4x_pol10/1(q) -> fft_direct/13(in22)
  in23/1 -> in_del_4x_pol11/1(d)
  in_del_4x_pol11/1(q) -> fft_biplex_real_4x/14(pol11_in)
  fft_biplex_real_4x/13(pol11_out) -> del_4x_pol11/1(d)
  del_4x_pol11/1(q) -> fft_direct/14(in23)
  in30/1 -> in_del_4x_pol12/1(d)
  in_del_4x_pol12/1(q) -> fft_biplex_real_4x/15(pol12_in)
  fft_biplex_real_4x/14(pol12_out) -> del_4x_pol12/1(d)
  del_4x_pol12/1(q) -> fft_direct/15(in30)
  in31/1 -> in_del_4x_pol13/1(d)
  in_del_4x_pol13/1(q) -> fft_biplex_real_4x/16(pol13_in)
  fft_biplex_real_4x/15(pol13_out) -> del_4x_pol13/1(d)
  del_4x_pol13/1(q) -> fft_direct/16(in31)
  in32/1 -> in_del_4x_pol14/1(d)
  in_del_4x_pol14/1(q) -> fft_biplex_real_4x/17(pol14_in)
  fft_biplex_real_4x/16(pol14_out) -> del_4x_pol14/1(d)
  del_4x_pol14/1(q) -> fft_direct/17(in32)
  in33/1 -> in_del_4x_pol15/1(d)
  in_del_4x_pol15/1(q) -> fft_biplex_real_4x/18(pol15_in)
  fft_biplex_real_4x/17(pol15_out) -> del_4x_pol15/1(d)
  del_4x_pol15/1(q) -> fft_direct/18(in33)

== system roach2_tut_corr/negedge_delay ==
  in : Inport
  Constant5 : xbsIndex_r4/Constant  const=pulse_len-2  gui_display_data_type=Fixed-point  arith_type=Unsigned  n_bits=bits  bin_pt=0  preci_type=Single  exp_width=8  frac_width=24  explicit_period=off  period=1  equ=P=C  opselect=C  inp2=PCIN>>17  opr=+  inp1=P  carry=CIN  dbl_ovrd=off  block_type=constant
  Counter3 : xbsIndex_r4/Counter  cnt_type=Free Running  cnt_to=1023  operation=Up  start_count=0  cnt_by_val=1  arith_type=Unsigned  n_bits=bits  bin_pt=0  load_pin=off  rst=on  en=on  explicit_period=on  period=1  dbl_ovrd=off  use_behavioral_HDL=on  implementation=Fabric  use_rpm=on  block_type=counter
  Delay : xbsIndex_r4/Delay  rst=off  infoeditControl=Selection of Reset will increase slice count due to use of real FFs and instead of SRLs  en=off  latency=1  dbl_ovrd=off  reg_retiming=on  block_type=delay
  Logical : xbsIndex_r4/Logical  logical_function=OR  inputs=3  en=off  latency=0  precision=Full  arith_type=Unsigned  n_bits=16  bin_pt=0  align_bp=on  dbl_ovrd=off  block_type=logical
  Relational5 : xbsIndex_r4/Relational  mode=a<=b  en=off  latency=0  dbl_ovrd=off  block_type=relational
  negedge : Subsystem  AncestorBlock=casper_library_misc/edge_detect
  out : Outport
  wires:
  Delay/1 -> Logical/2
  Logical/1 -> out/1
  Counter3/1 -> Relational5/1
  Constant5/1 -> Relational5/2
  Relational5/1 -> Logical/3, Counter3/2
  in/1 -> negedge/1(in), Logical/1, Delay/1
  negedge/1(out) -> Counter3/1

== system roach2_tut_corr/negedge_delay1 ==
  in : Inport
  Constant5 : xbsIndex_r4/Constant  const=pulse_len-2  gui_display_data_type=Fixed-point  arith_type=Unsigned  n_bits=bits  bin_pt=0  preci_type=Single  exp_width=8  frac_width=24  explicit_period=off  period=1  equ=P=C  opselect=C  inp2=PCIN>>17  opr=+  inp1=P  carry=CIN  dbl_ovrd=off  block_type=constant
  Counter3 : xbsIndex_r4/Counter  cnt_type=Free Running  cnt_to=1023  operation=Up  start_count=0  cnt_by_val=1  arith_type=Unsigned  n_bits=bits  bin_pt=0  load_pin=off  rst=on  en=on  explicit_period=on  period=1  dbl_ovrd=off  use_behavioral_HDL=on  implementation=Fabric  use_rpm=on  block_type=counter
  Delay : xbsIndex_r4/Delay  rst=off  infoeditControl=Selection of Reset will increase slice count due to use of real FFs and instead of SRLs  en=off  latency=1  dbl_ovrd=off  reg_retiming=on  block_type=delay
  Logical : xbsIndex_r4/Logical  logical_function=OR  inputs=3  en=off  latency=0  precision=Full  arith_type=Unsigned  n_bits=16  bin_pt=0  align_bp=on  dbl_ovrd=off  block_type=logical
  Relational5 : xbsIndex_r4/Relational  mode=a<=b  en=off  latency=0  dbl_ovrd=off  block_type=relational
  negedge : Subsystem  AncestorBlock=casper_library_misc/edge_detect
  out : Outport
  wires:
  Delay/1 -> Logical/2
  Logical/1 -> out/1
  Counter3/1 -> Relational5/1
  Constant5/1 -> Relational5/2
  Relational5/1 -> Logical/3, Counter3/2
  in/1 -> negedge/1(in), Logical/1, Delay/1
  negedge/1(out) -> Counter3/1

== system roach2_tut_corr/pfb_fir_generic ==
  sync : Inport
  pol0_in0 : Inport  Port=2
  pol0_in1 : Inport  Port=3
  pol0_in2 : Inport  Port=4
  pol0_in3 : Inport  Port=5
  pol1_in0 : Inport  Port=6
  pol1_in1 : Inport  Port=7
  pol1_in2 : Inport  Port=8
  pol1_in3 : Inport  Port=9
  pol2_in0 : Inport  Port=10
  pol2_in1 : Inport  Port=11
  pol2_in2 : Inport  Port=12
  pol2_in3 : Inport  Port=13
  pol3_in0 : Inport  Port=14
  pol3_in1 : Inport  Port=15
  pol3_in2 : Inport  Port=16
  pol3_in3 : Inport  Port=17
  bus_convert : Subsystem  AncestorBlock=casper_library_bus/bus_convert
  bus_create : Subsystem  AncestorBlock=casper_library_flow_control/bus_create
  bus_expand : Subsystem  AncestorBlock=casper_library_flow_control/bus_expand
  bus_scale : Subsystem  AncestorBlock=casper_library_bus/bus_scale
  coeff_munge : Subsystem  AncestorBlock=casper_library_flow_control/munge
  pfb_fir_coeff_gen : Subsystem  AncestorBlock=casper_library_pfbs/pfb_fir_coeff_gen
  pfb_fir_taps : Subsystem  AncestorBlock=casper_library_pfbs/pfb_fir_taps
  sync_delay : xbsIndex_r4/Delay  rst=off  infoeditControl=Selection of Reset will increase slice count due to use of real FFs and instead of SRLs  en=off  latency=conv_latency  dbl_ovrd=off  reg_retiming=on  block_type=delay
  sync_out : Outport
  pol0_out0 : Outport  Port=2
  pol0_out1 : Outport  Port=3
  pol0_out2 : Outport  Port=4
  pol0_out3 : Outport  Port=5
  pol1_out0 : Outport  Port=6
  pol1_out1 : Outport  Port=7
  pol1_out2 : Outport  Port=8
  pol1_out3 : Outport  Port=9
  pol2_out0 : Outport  Port=10
  pol2_out1 : Outport  Port=11
  pol2_out2 : Outport  Port=12
  pol2_out3 : Outport  Port=13
  pol3_out0 : Outport  Port=14
  pol3_out1 : Outport  Port=15
  pol3_out2 : Outport  Port=16
  pol3_out3 : Outport  Port=17
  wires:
  pol0_in0/1 -> bus_create/1(in1)
  bus_expand/1(msb_out16) -> pol0_out0/1
  pol0_in1/1 -> bus_create/5(in5)
  bus_expand/5(out12) -> pol0_out1/1
  pol0_in2/1 -> bus_create/9(in9)
  bus_expand/9(out8) -> pol0_out2/1
  pol0_in3/1 -> bus_create/13(in13)
  bus_expand/13(out4) -> pol0_out3/1
  pol1_in0/1 -> bus_create/2(in2)
  bus_expand/2(out15) -> pol1_out0/1
  pol1_in1/1 -> bus_create/6(in6)
  bus_expand/6(out11) -> pol1_out1/1
  pol1_in2/1 -> bus_create/10(in10)
  bus_expand/10(out7) -> pol1_out2/1
  pol1_in3/1 -> bus_create/14(in14)
  bus_expand/14(out3) -> pol1_out3/1
  pol2_in0/1 -> bus_create/3(in3)
  bus_expand/3(out14) -> pol2_out0/1
  pol2_in1/1 -> bus_create/7(in7)
  bus_expand/7(out10) -> pol2_out1/1
  pol2_in2/1 -> bus_create/11(in11)
  bus_expand/11(out6) -> pol2_out2/1
  pol2_in3/1 -> bus_create/15(in15)
  bus_expand/15(out2) -> pol2_out3/1
  pol3_in0/1 -> bus_create/4(in4)
  bus_expand/4(out13) -> pol3_out0/1
  pol3_in1/1 -> bus_create/8(in8)
  bus_expand/8(out9) -> pol3_out1/1
  pol3_in2/1 -> bus_create/12(in12)
  bus_expand/12(out5) -> pol3_out2/1
  pol3_in3/1 -> bus_create/16(in16)
  bus_expand/16(lsb_out1) -> pol3_out3/1
  bus_create/1(bus_out) -> pfb_fir_coeff_gen/2(din)
  pfb_fir_coeff_gen/3(coeffs) -> coeff_munge/1(din)
  pfb_fir_coeff_gen/2(dout) -> pfb_fir_taps/2(din)
  coeff_munge/1(dout) -> pfb_fir_taps/3(coeffs)
  pfb_fir_taps/2(dout) -> bus_scale/1(din)
  bus_scale/1(dout) -> bus_convert/1(din)
  bus_convert/1(dout) -> bus_expand/1(bus_in)
  sync/1 -> pfb_fir_coeff_gen/1(sync)
  pfb_fir_coeff_gen/1(sync_out) -> pfb_fir_taps/1(sync)
  pfb_fir_taps/1(sync_out) -> sync_delay/1
  sync_delay/1 -> sync_out/1

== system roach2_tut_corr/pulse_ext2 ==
  in : Inport
  Constant5 : xbsIndex_r4/Constant  const=pulse_len  gui_display_data_type=Fixed-point  arith_type=Unsigned  n_bits=bits  bin_pt=0  preci_type=Single  exp_width=8  frac_width=24  explicit_period=off  period=1  equ=P=C  opselect=C  inp2=PCIN>>17  opr=+  inp1=P  carry=CIN  dbl_ovrd=off  block_type=constant
  Counter3 : xbsIndex_r4/Counter  cnt_type=Free Running  cnt_to=1023  operation=Up  start_count=0  cnt_by_val=1  arith_type=Unsigned  n_bits=bits  bin_pt=0  load_pin=off  rst=on  en=on  explicit_period=on  period=1  dbl_ovrd=off  use_behavioral_HDL=off  implementation=Fabric  use_rpm=on  block_type=counter
  Relational5 : xbsIndex_r4/Relational  mode=a!=b  en=off  latency=0  dbl_ovrd=off  block_type=relational
  edge_detect : Subsystem  AncestorBlock=casper_library_misc/edge_detect
  out : Outport
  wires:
  Counter3/1 -> Relational5/1
  Constant5/1 -> Relational5/2
  Relational5/1 -> Counter3/2, out/1
  in/1 -> edge_detect/1(in)
  edge_detect/1(out) -> Counter3/1

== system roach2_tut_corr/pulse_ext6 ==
  in : Inport
  Constant5 : xbsIndex_r4/Constant  const=pulse_len  gui_display_data_type=Fixed-point  arith_type=Unsigned  n_bits=bits  bin_pt=0  preci_type=Single  exp_width=8  frac_width=24  explicit_period=off  period=1  equ=P=C  opselect=C  inp2=PCIN>>17  opr=+  inp1=P  carry=CIN  dbl_ovrd=off  block_type=constant
  Counter3 : xbsIndex_r4/Counter  cnt_type=Free Running  cnt_to=1023  operation=Up  start_count=0  cnt_by_val=1  arith_type=Unsigned  n_bits=bits  bin_pt=0  load_pin=off  rst=on  en=on  explicit_period=on  period=1  dbl_ovrd=off  use_behavioral_HDL=off  implementation=Fabric  use_rpm=on  block_type=counter
  Relational5 : xbsIndex_r4/Relational  mode=a!=b  en=off  latency=0  dbl_ovrd=off  block_type=relational
  edge_detect : Subsystem  AncestorBlock=casper_library_misc/edge_detect
  out : Outport
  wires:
  edge_detect/1(out) -> Counter3/1
  in/1 -> edge_detect/1(in)
  Relational5/1 -> out/1, Counter3/2
  Constant5/1 -> Relational5/2
  Counter3/1 -> Relational5/1

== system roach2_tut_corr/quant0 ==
  sync : Inport
  din : Inport  Port=2
  Constant : xbsIndex_r4/Constant  const=0  gui_display_data_type=Fixed-point  arith_type=Unsigned  n_bits=32  bin_pt=0  preci_type=Single  exp_width=8  frac_width=24  explicit_period=on  period=1  equ=P=C  opselect=C  inp2=PCIN>>17  opr=+  inp1=P  carry=CIN  dbl_ovrd=off  block_type=constant
  Constant1 : xbsIndex_r4/Constant  const=0  gui_display_data_type=Boolean  arith_type=Boolean  n_bits=32  bin_pt=0  preci_type=Single  exp_width=8  frac_width=24  explicit_period=on  period=1  equ=P=C  opselect=C  inp2=PCIN>>17  opr=+  inp1=P  carry=CIN  dbl_ovrd=off  block_type=constant
  Counter : xbsIndex_r4/Counter  cnt_type=Free Running  cnt_to=Inf  operation=Up  start_count=0  cnt_by_val=1  arith_type=Unsigned  n_bits=10  bin_pt=0  load_pin=off  rst=on  en=off  explicit_period=on  period=1  dbl_ovrd=off  use_behavioral_HDL=off  implementation=Fabric  block_type=counter
  Delay{1..3,5} (4 alike) : xbsIndex_r4/Delay  rst=off  infoeditControl=Selection of Reset will increase slice count due to use of real FFs and instead of SRLs  en=off  latency=1  dbl_ovrd=off  reg_retiming=on  block_type=delay
  Delay{6,18..19,25} (4 alike) : xbsIndex_r4/Delay  rst=off  infoeditControl=Selection of Reset will increase slice count due to use of real FFs and instead of SRLs  en=off  latency=1  dbl_ovrd=off  reg_retiming=off  block_type=delay
  Delay4 : xbsIndex_r4/Delay  rst=off  infoeditControl=Selection of Reset will increase slice count due to use of real FFs and instead of SRLs  en=off  latency=6  dbl_ovrd=off  reg_retiming=on  block_type=delay
  Logical5 : xbsIndex_r4/Logical  logical_function=OR  inputs=2  en=off  latency=0  precision=Full  arith_type=Unsigned  n_bits=8  bin_pt=2  align_bp=on  dbl_ovrd=off  block_type=logical
  Slice11 : xbsIndex_r4/Slice  nbits=16  boolean_output=off  mode=Lower Bit Location + Width  bit1=0  base1=MSB of Input  bit0=0  base0=LSB of Input  dbl_ovrd=off  block_type=slice
  Slice14 : xbsIndex_r4/Slice  nbits=16  boolean_output=off  mode=Lower Bit Location + Width  bit1=0  base1=MSB of Input  bit0=16  base0=LSB of Input  dbl_ovrd=off  block_type=slice
  bus_expand : Subsystem  AncestorBlock=casper_library_flow_control/bus_expand
  coeffs : Subsystem  Tag=xps:bram  AncestorBlock=xps_library/Shared_BRAM
  round0 : Subsystem
  round1 : Subsystem
  sync_out : Outport
  clip_out : Outport  Port=2
  dout0 : Outport  Port=3
  dout1 : Outport  Port=4
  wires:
  round0/2(clip) -> Logical5/1
  round1/2(clip) -> Logical5/2
  Delay19/1 -> Delay4/1
  coeffs/1(data_out) -> Delay1/1
  Slice14/1 -> round0/2(scale)
  Slice11/1 -> round1/2(scale)
  Delay18/1 -> Delay3/1
  Delay25/1 -> Delay2/1
  sync/1 -> Counter/1, Delay6/1
  Delay4/1 -> sync_out/1
  round0/1(dout) -> dout0/1
  Logical5/1 -> Delay5/1
  bus_expand/2(lsb_out1) -> Delay25/1
  round1/1(dout) -> dout1/1
  Delay1/1 -> Slice11/1, Slice14/1
  Delay2/1 -> round1/1(din)
  Delay3/1 -> round0/1(din)
  Delay5/1 -> clip_out/1
  bus_expand/1(msb_out2) -> Delay18/1
  din/1 -> bus_expand/1(bus_in)
  Delay6/1 -> Delay19/1
  Counter/1 -> coeffs/1(addr)
  Constant/1 -> coeffs/2(data_in)
  Constant1/1 -> coeffs/3(we)
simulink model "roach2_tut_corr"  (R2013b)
settings: Solver=VariableStepDiscrete  SolverMode=SingleTasking  StartTime=0.0  StopTime=100  RelTol=1e-3
undefined symbols (not defined in the file): add_latency, addr_width, Bit, bitfield, BitWidth, bram_latency, burst_size, casper_library_scopes, conv_latency, data_width, DelayLen, fan_latency, FFTSize, FFTStage, getfield, increment, led, Location, Lower, mult_latency, mux_latency, n_bits, n_bits_data, n_inputs, n_streams, n_taps, neg_latency, negate_latency, nsamples, pfb_size, pulse_len, reset_period, ROACH, ROACH2, snapshot, sx475t, sync_period, sync_period_bits, Upper, UseCounter, Width
libraries: xbsIndex_r4 x24444, casper_library_misc x73, xbsReplacements_r4 x34, casper_library_delays x14, xps_library x7
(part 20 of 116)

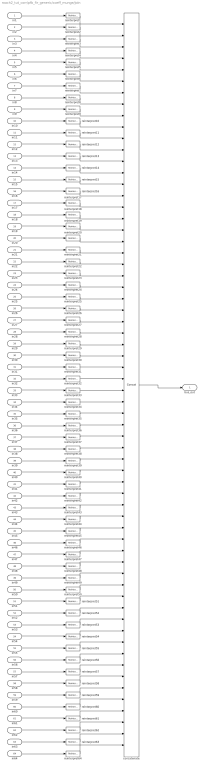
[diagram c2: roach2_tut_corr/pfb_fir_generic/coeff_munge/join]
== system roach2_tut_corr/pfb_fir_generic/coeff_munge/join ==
  in1 : Inport
  in2 : Inport  Port=2
  in3 : Inport  Port=3
  in4 : Inport  Port=4
  in5 : Inport  Port=5
  in6 : Inport  Port=6
  in7 : Inport  Port=7
  in8 : Inport  Port=8
  in9 : Inport  Port=9
  in10 : Inport  Port=10
  in11 : Inport  Port=11
  in12 : Inport  Port=12
  in13 : Inport  Port=13
  in14 : Inport  Port=14
  in15 : Inport  Port=15
  in16 : Inport  Port=16
  in17 : Inport  Port=17
  in18 : Inport  Port=18
  in19 : Inport  Port=19
  in20 : Inport  Port=20
  in21 : Inport  Port=21
  in22 : Inport  Port=22
  in23 : Inport  Port=23
  in24 : Inport  Port=24
  in25 : Inport  Port=25
  in26 : Inport  Port=26
  in27 : Inport  Port=27
  in28 : Inport  Port=28
  in29 : Inport  Port=29
  in30 : Inport  Port=30
  in31 : Inport  Port=31
  in32 : Inport  Port=32
  in33 : Inport  Port=33
  in34 : Inport  Port=34
  in35 : Inport  Port=35
  in36 : Inport  Port=36
  in37 : Inport  Port=37
  in38 : Inport  Port=38
  in39 : Inport  Port=39
  in40 : Inport  Port=40
  in41 : Inport  Port=41
  in42 : Inport  Port=42
  in43 : Inport  Port=43
  in44 : Inport  Port=44
  in45 : Inport  Port=45
  in46 : Inport  Port=46
  in47 : Inport  Port=47
  in48 : Inport  Port=48
  in49 : Inport  Port=49
  in50 : Inport  Port=50
  in51 : Inport  Port=51
  in52 : Inport  Port=52
  in53 : Inport  Port=53
  in54 : Inport  Port=54
  in55 : Inport  Port=55
  in56 : Inport  Port=56
  in57 : Inport  Port=57
  in58 : Inport  Port=58
  in59 : Inport  Port=59
  in60 : Inport  Port=60
  in61 : Inport  Port=61
  in62 : Inport  Port=62
  in63 : Inport  Port=63
  in64 : Inport  Port=64
  concatenate : xbsIndex_r4/Concat  num_inputs=64  dbl_ovrd=off  block_type=concat
  reinterpret{1..64} (64 alike) : xbsIndex_r4/Reinterpret  force_arith_type=on  arith_type=Unsigned  force_bin_pt=on  bin_pt=0  block_type=reinterpret
  bus_out : Outport
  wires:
  concatenate/1 -> bus_out/1
  in1/1 -> reinterpret1/1
  reinterpret1/1 -> concatenate/1
  in2/1 -> reinterpret2/1
  reinterpret2/1 -> concatenate/2
  in3/1 -> reinterpret3/1
  reinterpret3/1 -> concatenate/3
  in4/1 -> reinterpret4/1
  reinterpret4/1 -> concatenate/4
  in5/1 -> reinterpret5/1
  reinterpret5/1 -> concatenate/5
  in6/1 -> reinterpret6/1
  reinterpret6/1 -> concatenate/6
  in7/1 -> reinterpret7/1
  reinterpret7/1 -> concatenate/7
  in8/1 -> reinterpret8/1
  reinterpret8/1 -> concatenate/8
  in9/1 -> reinterpret9/1
  reinterpret9/1 -> concatenate/9
  in10/1 -> reinterpret10/1
  reinterpret10/1 -> concatenate/10
  in11/1 -> reinterpret11/1
  reinterpret11/1 -> concatenate/11
  in12/1 -> reinterpret12/1
  reinterpret12/1 -> concatenate/12
  in13/1 -> reinterpret13/1
  reinterpret13/1 -> concatenate/13
  in14/1 -> reinterpret14/1
  reinterpret14/1 -> concatenate/14
  in15/1 -> reinterpret15/1
  reinterpret15/1 -> concatenate/15
  in16/1 -> reinterpret16/1
  reinterpret16/1 -> concatenate/16
  in17/1 -> reinterpret17/1
  reinterpret17/1 -> concatenate/17
  in18/1 -> reinterpret18/1
  reinterpret18/1 -> concatenate/18
  in19/1 -> reinterpret19/1
  reinterpret19/1 -> concatenate/19
  in20/1 -> reinterpret20/1
  reinterpret20/1 -> concatenate/20
  in21/1 -> reinterpret21/1
  reinterpret21/1 -> concatenate/21
  in22/1 -> reinterpret22/1
  reinterpret22/1 -> concatenate/22
  in23/1 -> reinterpret23/1
  reinterpret23/1 -> concatenate/23
  in24/1 -> reinterpret24/1
  reinterpret24/1 -> concatenate/24
  in25/1 -> reinterpret25/1
  reinterpret25/1 -> concatenate/25
  in26/1 -> reinterpret26/1
  reinterpret26/1 -> concatenate/26
  in27/1 -> reinterpret27/1
  reinterpret27/1 -> concatenate/27
  in28/1 -> reinterpret28/1
  reinterpret28/1 -> concatenate/28
  in29/1 -> reinterpret29/1
  reinterpret29/1 -> concatenate/29
  in30/1 -> reinterpret30/1
  reinterpret30/1 -> concatenate/30
  in31/1 -> reinterpret31/1
  reinterpret31/1 -> concatenate/31
  in32/1 -> reinterpret32/1
  reinterpret32/1 -> concatenate/32
  in33/1 -> reinterpret33/1
  reinterpret33/1 -> concatenate/33
  in34/1 -> reinterpret34/1
  reinterpret34/1 -> concatenate/34
  in35/1 -> reinterpret35/1
  reinterpret35/1 -> concatenate/35
  in36/1 -> reinterpret36/1
  reinterpret36/1 -> concatenate/36
  in37/1 -> reinterpret37/1
  reinterpret37/1 -> concatenate/37
  in38/1 -> reinterpret38/1
  reinterpret38/1 -> concatenate/38
  in39/1 -> reinterpret39/1
  reinterpret39/1 -> concatenate/39
  in40/1 -> reinterpret40/1
  reinterpret40/1 -> concatenate/40
  in41/1 -> reinterpret41/1
  reinterpret41/1 -> concatenate/41
  in42/1 -> reinterpret42/1
  reinterpret42/1 -> concatenate/42
  in43/1 -> reinterpret43/1
  reinterpret43/1 -> concatenate/43
  in44/1 -> reinterpret44/1
  reinterpret44/1 -> concatenate/44
  in45/1 -> reinterpret45/1
  reinterpret45/1 -> concatenate/45
  in46/1 -> reinterpret46/1
  reinterpret46/1 -> concatenate/46
  in47/1 -> reinterpret47/1
  reinterpret47/1 -> concatenate/47
  in48/1 -> reinterpret48/1
  reinterpret48/1 -> concatenate/48
  in49/1 -> reinterpret49/1
  reinterpret49/1 -> concatenate/49
  in50/1 -> reinterpret50/1
  reinterpret50/1 -> concatenate/50
  in51/1 -> reinterpret51/1
  reinterpret51/1 -> concatenate/51
  in52/1 -> reinterpret52/1
  reinterpret52/1 -> concatenate/52
  in53/1 -> reinterpret53/1
  reinterpret53/1 -> concatenate/53
  in54/1 -> reinterpret54/1
  reinterpret54/1 -> concatenate/54
  in55/1 -> reinterpret55/1
  reinterpret55/1 -> concatenate/55
  in56/1 -> reinterpret56/1
  reinterpret56/1 -> concatenate/56
  in57/1 -> reinterpret57/1
  reinterpret57/1 -> concatenate/57
  in58/1 -> reinterpret58/1
  reinterpret58/1 -> concatenate/58
  in59/1 -> reinterpret59/1
  reinterpret59/1 -> concatenate/59
  in60/1 -> reinterpret60/1
  reinterpret60/1 -> concatenate/60
  in61/1 -> reinterpret61/1
  reinterpret61/1 -> concatenate/61
  in62/1 -> reinterpret62/1
  reinterpret62/1 -> concatenate/62
  in63/1 -> reinterpret63/1
  reinterpret63/1 -> concatenate/63
  in64/1 -> reinterpret64/1
  reinterpret64/1 -> concatenate/64

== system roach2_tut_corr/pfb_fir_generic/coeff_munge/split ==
  bus_in : Inport
  reinterpret{1..16} (16 alike) : xbsIndex_r4/Reinterpret  force_arith_type=on  arith_type=Unsigned  force_bin_pt=on  bin_pt=0  block_type=reinterpret
  slice1 : xbsIndex_r4/Slice  nbits=18  boolean_output=off  mode=Upper Bit Location + Width  bit1=-270  base1=MSB of Input  bit0=0  base0=LSB of Input  dbl_ovrd=off  block_type=slice
  slice10 : xbsIndex_r4/Slice  nbits=18  boolean_output=off  mode=Upper Bit Location + Width  bit1=-108  base1=MSB of Input  bit0=0  base0=LSB of Input  dbl_ovrd=off  block_type=slice
  slice11 : xbsIndex_r4/Slice  nbits=18  boolean_output=off  mode=Upper Bit Location + Width  bit1=-90  base1=MSB of Input  bit0=0  base0=LSB of Input  dbl_ovrd=off  block_type=slice
  slice12 : xbsIndex_r4/Slice  nbits=18  boolean_output=off  mode=Upper Bit Location + Width  bit1=-72  base1=MSB of Input  bit0=0  base0=LSB of Input  dbl_ovrd=off  block_type=slice
  slice13 : xbsIndex_r4/Slice  nbits=18  boolean_output=off  mode=Upper Bit Location + Width  bit1=-54  base1=MSB of Input  bit0=0  base0=LSB of Input  dbl_ovrd=off  block_type=slice
  slice14 : xbsIndex_r4/Slice  nbits=18  boolean_output=off  mode=Upper Bit Location + Width  bit1=-36  base1=MSB of Input  bit0=0  base0=LSB of Input  dbl_ovrd=off  block_type=slice
  slice15 : xbsIndex_r4/Slice  nbits=18  boolean_output=off  mode=Upper Bit Location + Width  bit1=-18  base1=MSB of Input  bit0=0  base0=LSB of Input  dbl_ovrd=off  block_type=slice
  slice16 : xbsIndex_r4/Slice  nbits=18  boolean_output=off  mode=Upper Bit Location + Width  bit1=0  base1=MSB of Input  bit0=0  base0=LSB of Input  dbl_ovrd=off  block_type=slice
  slice2 : xbsIndex_r4/Slice  nbits=18  boolean_output=off  mode=Upper Bit Location + Width  bit1=-252  base1=MSB of Input  bit0=0  base0=LSB of Input  dbl_ovrd=off  block_type=slice
  slice3 : xbsIndex_r4/Slice  nbits=18  boolean_output=off  mode=Upper Bit Location + Width  bit1=-234  base1=MSB of Input  bit0=0  base0=LSB of Input  dbl_ovrd=off  block_type=slice
  slice4 : xbsIndex_r4/Slice  nbits=18  boolean_output=off  mode=Upper Bit Location + Width  bit1=-216  base1=MSB of Input  bit0=0  base0=LSB of Input  dbl_ovrd=off  block_type=slice
  slice5 : xbsIndex_r4/Slice  nbits=18  boolean_output=off  mode=Upper Bit Location + Width  bit1=-198  base1=MSB of Input  bit0=0  base0=LSB of Input  dbl_ovrd=off  block_type=slice
  slice6 : xbsIndex_r4/Slice  nbits=18  boolean_output=off  mode=Upper Bit Location + Width  bit1=-180  base1=MSB of Input  bit0=0  base0=LSB of Input  dbl_ovrd=off  block_type=slice
  slice7 : xbsIndex_r4/Slice  nbits=18  boolean_output=off  mode=Upper Bit Location + Width  bit1=-162  base1=MSB of Input  bit0=0  base0=LSB of Input  dbl_ovrd=off  block_type=slice
  slice8 : xbsIndex_r4/Slice  nbits=18  boolean_output=off  mode=Upper Bit Location + Width  bit1=-144  base1=MSB of Input  bit0=0  base0=LSB of Input  dbl_ovrd=off  block_type=slice
  slice9 : xbsIndex_r4/Slice  nbits=18  boolean_output=off  mode=Upper Bit Location + Width  bit1=-126  base1=MSB of Input  bit0=0  base0=LSB of Input  dbl_ovrd=off  block_type=slice
  msb_out16 : Outport
  out15 : Outport  Port=2
  out14 : Outport  Port=3
  out13 : Outport  Port=4
  out12 : Outport  Port=5
  out11 : Outport  Port=6
  out10 : Outport  Port=7
  out9 : Outport  Port=8
  out8 : Outport  Port=9
  out7 : Outport  Port=10
  out6 : Outport  Port=11
  out5 : Outport  Port=12
  out4 : Outport  Port=13
  out3 : Outport  Port=14
  out2 : Outport  Port=15
  lsb_out1 : Outport  Port=16
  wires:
  bus_in/1 -> slice16/1, slice15/1, slice14/1, slice13/1, slice12/1, slice11/1, slice10/1, slice9/1, slice8/1, slice7/1, slice6/1, slice5/1, slice4/1, slice3/1, slice2/1, slice1/1
  slice16/1 -> reinterpret16/1
  reinterpret16/1 -> msb_out16/1
  slice15/1 -> reinterpret15/1
  reinterpret15/1 -> out15/1
  slice14/1 -> reinterpret14/1
  reinterpret14/1 -> out14/1
  slice13/1 -> reinterpret13/1
  reinterpret13/1 -> out13/1
  slice12/1 -> reinterpret12/1
  reinterpret12/1 -> out12/1
  slice11/1 -> reinterpret11/1
  reinterpret11/1 -> out11/1
  slice10/1 -> reinterpret10/1
  reinterpret10/1 -> out10/1
  slice9/1 -> reinterpret9/1
  reinterpret9/1 -> out9/1
  slice8/1 -> reinterpret8/1
  reinterpret8/1 -> out8/1
  slice7/1 -> reinterpret7/1
  reinterpret7/1 -> out7/1
  slice6/1 -> reinterpret6/1
  reinterpret6/1 -> out6/1
  slice5/1 -> reinterpret5/1
  reinterpret5/1 -> out5/1
  slice4/1 -> reinterpret4/1
  reinterpret4/1 -> out4/1
  slice3/1 -> reinterpret3/1
  reinterpret3/1 -> out3/1
  slice2/1 -> reinterpret2/1
  reinterpret2/1 -> out2/1
  slice1/1 -> reinterpret1/1
  reinterpret1/1 -> lsb_out1/1

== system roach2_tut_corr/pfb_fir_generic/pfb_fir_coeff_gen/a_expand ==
  bus_in : Inport
  reinterpret{1..8} (8 alike) : xbsIndex_r4/Reinterpret  force_arith_type=on  arith_type=Unsigned  force_bin_pt=on  bin_pt=0  block_type=reinterpret
  slice1 : xbsIndex_r4/Slice  nbits=18  boolean_output=off  mode=Upper Bit Location + Width  bit1=-126  base1=MSB of Input  bit0=0  base0=LSB of Input  dbl_ovrd=off  block_type=slice
  slice2 : xbsIndex_r4/Slice  nbits=18  boolean_output=off  mode=Upper Bit Location + Width  bit1=-108  base1=MSB of Input  bit0=0  base0=LSB of Input  dbl_ovrd=off  block_type=slice
  slice3 : xbsIndex_r4/Slice  nbits=18  boolean_output=off  mode=Upper Bit Location + Width  bit1=-90  base1=MSB of Input  bit0=0  base0=LSB of Input  dbl_ovrd=off  block_type=slice
  slice4 : xbsIndex_r4/Slice  nbits=18  boolean_output=off  mode=Upper Bit Location + Width  bit1=-72  base1=MSB of Input  bit0=0  base0=LSB of Input  dbl_ovrd=off  block_type=slice
  slice5 : xbsIndex_r4/Slice  nbits=18  boolean_output=off  mode=Upper Bit Location + Width  bit1=-54  base1=MSB of Input  bit0=0  base0=LSB of Input  dbl_ovrd=off  block_type=slice
  slice6 : xbsIndex_r4/Slice  nbits=18  boolean_output=off  mode=Upper Bit Location + Width  bit1=-36  base1=MSB of Input  bit0=0  base0=LSB of Input  dbl_ovrd=off  block_type=slice
  slice7 : xbsIndex_r4/Slice  nbits=18  boolean_output=off  mode=Upper Bit Location + Width  bit1=-18  base1=MSB of Input  bit0=0  base0=LSB of Input  dbl_ovrd=off  block_type=slice
  slice8 : xbsIndex_r4/Slice  nbits=18  boolean_output=off  mode=Upper Bit Location + Width  bit1=0  base1=MSB of Input  bit0=0  base0=LSB of Input  dbl_ovrd=off  block_type=slice
  msb_out8 : Outport
  out7 : Outport  Port=2
  out6 : Outport  Port=3
  out5 : Outport  Port=4
  out4 : Outport  Port=5
  out3 : Outport  Port=6
  out2 : Outport  Port=7
  lsb_out1 : Outport  Port=8
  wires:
  bus_in/1 -> slice8/1, slice7/1, slice6/1, slice5/1, slice4/1, slice3/1, slice2/1, slice1/1
  slice8/1 -> reinterpret8/1
  reinterpret8/1 -> msb_out8/1
  slice7/1 -> reinterpret7/1
  reinterpret7/1 -> out7/1
  slice6/1 -> reinterpret6/1
  reinterpret6/1 -> out6/1
  slice5/1 -> reinterpret5/1
  reinterpret5/1 -> out5/1
  slice4/1 -> reinterpret4/1
  reinterpret4/1 -> out4/1
  slice3/1 -> reinterpret3/1
  reinterpret3/1 -> out3/1
  slice2/1 -> reinterpret2/1
  reinterpret2/1 -> out2/1
  slice1/1 -> reinterpret1/1
  reinterpret1/1 -> lsb_out1/1

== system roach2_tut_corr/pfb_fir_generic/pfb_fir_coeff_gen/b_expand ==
  bus_in : Inport
  reinterpret{1..8} (8 alike) : xbsIndex_r4/Reinterpret  force_arith_type=on  arith_type=Unsigned  force_bin_pt=on  bin_pt=0  block_type=reinterpret
  slice1 : xbsIndex_r4/Slice  nbits=18  boolean_output=off  mode=Upper Bit Location + Width  bit1=-126  base1=MSB of Input  bit0=0  base0=LSB of Input  dbl_ovrd=off  block_type=slice
  slice2 : xbsIndex_r4/Slice  nbits=18  boolean_output=off  mode=Upper Bit Location + Width  bit1=-108  base1=MSB of Input  bit0=0  base0=LSB of Input  dbl_ovrd=off  block_type=slice
  slice3 : xbsIndex_r4/Slice  nbits=18  boolean_output=off  mode=Upper Bit Location + Width  bit1=-90  base1=MSB of Input  bit0=0  base0=LSB of Input  dbl_ovrd=off  block_type=slice
  slice4 : xbsIndex_r4/Slice  nbits=18  boolean_output=off  mode=Upper Bit Location + Width  bit1=-72  base1=MSB of Input  bit0=0  base0=LSB of Input  dbl_ovrd=off  block_type=slice
  slice5 : xbsIndex_r4/Slice  nbits=18  boolean_output=off  mode=Upper Bit Location + Width  bit1=-54  base1=MSB of Input  bit0=0  base0=LSB of Input  dbl_ovrd=off  block_type=slice
  slice6 : xbsIndex_r4/Slice  nbits=18  boolean_output=off  mode=Upper Bit Location + Width  bit1=-36  base1=MSB of Input  bit0=0  base0=LSB of Input  dbl_ovrd=off  block_type=slice
  slice7 : xbsIndex_r4/Slice  nbits=18  boolean_output=off  mode=Upper Bit Location + Width  bit1=-18  base1=MSB of Input  bit0=0  base0=LSB of Input  dbl_ovrd=off  block_type=slice
  slice8 : xbsIndex_r4/Slice  nbits=18  boolean_output=off  mode=Upper Bit Location + Width  bit1=0  base1=MSB of Input  bit0=0  base0=LSB of Input  dbl_ovrd=off  block_type=slice
  msb_out8 : Outport
  out7 : Outport  Port=2
  out6 : Outport  Port=3
  out5 : Outport  Port=4
  out4 : Outport  Port=5
  out3 : Outport  Port=6
  out2 : Outport  Port=7
  lsb_out1 : Outport  Port=8
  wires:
  bus_in/1 -> slice8/1, slice7/1, slice6/1, slice5/1, slice4/1, slice3/1, slice2/1, slice1/1
  slice8/1 -> reinterpret8/1
  reinterpret8/1 -> msb_out8/1
  slice7/1 -> reinterpret7/1
  reinterpret7/1 -> out7/1
  slice6/1 -> reinterpret6/1
  reinterpret6/1 -> out6/1
  slice5/1 -> reinterpret5/1
  reinterpret5/1 -> out5/1
  slice4/1 -> reinterpret4/1
  reinterpret4/1 -> out4/1
  slice3/1 -> reinterpret3/1
  reinterpret3/1 -> out3/1
  slice2/1 -> reinterpret2/1
  reinterpret2/1 -> out2/1
  slice1/1 -> reinterpret1/1
  reinterpret1/1 -> lsb_out1/1

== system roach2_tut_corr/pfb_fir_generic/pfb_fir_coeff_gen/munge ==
  din : Inport
  join : Subsystem  AncestorBlock=casper_library_flow_control/bus_create
  reinterpret : xbsIndex_r4/Reinterpret  force_arith_type=on  arith_type=Unsigned  force_bin_pt=on  bin_pt=0  block_type=reinterpret
  reinterpret_out : xbsIndex_r4/Reinterpret  force_arith_type=on  arith_type=Unsigned  force_bin_pt=on  bin_pt=0  block_type=reinterpret
  split : Subsystem  AncestorBlock=casper_library_flow_control/bus_expand
  dout : Outport
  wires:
  reinterpret_out/1 -> dout/1
  din/1 -> reinterpret/1
  reinterpret/1 -> split/1(bus_in)
  join/1(bus_out) -> reinterpret_out/1
  split/5(out4) -> join/1(in1)
  split/8(lsb_out1) -> join/2(in2)
  split/7(out2) -> join/3(in3)
  split/6(out3) -> join/4(in4)
  split/1(msb_out8) -> join/5(in5)
  split/4(out5) -> join/6(in6)
  split/3(out6) -> join/7(in7)
  split/2(out7) -> join/8(in8)

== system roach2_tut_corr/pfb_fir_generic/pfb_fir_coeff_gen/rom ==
  addra : Inport
  dina : Inport  Port=2
  wea : Inport  Port=3
  addrb : Inport  Port=4
  dinb : Inport  Port=5
  web : Inport  Port=6
  A_bussify : Subsystem  AncestorBlock=casper_library_flow_control/bus_create
  B_bussify : Subsystem  AncestorBlock=casper_library_flow_control/bus_create
  bram{0..3} (4 alike) : xbsIndex_r4/Dual Port RAM  depth=512  initVector=getfield(get_param(gcb, 'UserData'), 'initVector')  distributed_mem=Block RAM  init_a=0  init_b=0  rst_a=off  rst_b=off  en_a=off  en_b=off  latency=3  write_mode_A=Read Before Write  write_mode_B=Read Before Write  dbl_ovrd=off  optimize=Speed  block_type=dpram
  ddina : xbsIndex_r4/Delay  rst=off  infoeditControl=Selection of Reset will increase slice count due to use of real FFs and instead of SRLs  en=off  latency=0  dbl_ovrd=off  reg_retiming=on  block_type=delay
  ddinb : xbsIndex_r4/Delay  rst=off  infoeditControl=Selection of Reset will increase slice count due to use of real FFs and instead of SRLs  en=off  latency=0  dbl_ovrd=off  reg_retiming=on  block_type=delay
  debus_addra : Subsystem  AncestorBlock=casper_library_flow_control/bus_expand
  debus_addrb : Subsystem  AncestorBlock=casper_library_flow_control/bus_expand
  debus_dina : Subsystem  AncestorBlock=casper_library_flow_control/bus_expand
  debus_dinb : Subsystem  AncestorBlock=casper_library_flow_control/bus_expand
  debus_wea : Subsystem  AncestorBlock=casper_library_flow_control/bus_expand
  debus_web : Subsystem  AncestorBlock=casper_library_flow_control/bus_expand
  rep_addra : Subsystem  AncestorBlock=casper_library_bus/bus_replicate
  rep_addrb : Subsystem  AncestorBlock=casper_library_bus/bus_replicate
  rep_wea : Subsystem  AncestorBlock=casper_library_bus/bus_replicate
  rep_web : Subsystem  AncestorBlock=casper_library_bus/bus_replicate
  A : Outport
  B : Outport  Port=2
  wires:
  addra/1 -> rep_addra/1(in)
  dina/1 -> ddina/1
  wea/1 -> rep_wea/1(in)
  addrb/1 -> rep_addrb/1(in)
  dinb/1 -> ddinb/1
  web/1 -> rep_web/1(in)
  rep_addra/1(out) -> debus_addra/1(bus_in)
  ddina/1 -> debus_dina/1(bus_in)
  rep_wea/1(out) -> debus_wea/1(bus_in)
  rep_addrb/1(out) -> debus_addrb/1(bus_in)
  ddinb/1 -> debus_dinb/1(bus_in)
  rep_web/1(out) -> debus_web/1(bus_in)
  debus_addra/1(msb_out4) -> bram0/1
  debus_dina/1(msb_out4) -> bram0/2
  debus_wea/1(msb_out4) -> bram0/3
  debus_addrb/1(msb_out4) -> bram0/4
  debus_dinb/1(msb_out4) -> bram0/5
  debus_web/1(msb_out4) -> bram0/6
  debus_addra/2(out3) -> bram1/1
  debus_dina/2(out3) -> bram1/2
  debus_wea/2(out3) -> bram1/3
  debus_addrb/2(out3) -> bram1/4
  debus_dinb/2(out3) -> bram1/5
  debus_web/2(out3) -> bram1/6
  debus_addra/3(out2) -> bram2/1
  debus_dina/3(out2) -> bram2/2
  debus_wea/3(out2) -> bram2/3
  debus_addrb/3(out2) -> bram2/4
  debus_dinb/3(out2) -> bram2/5
  debus_web/3(out2) -> bram2/6
  debus_addra/4(lsb_out1) -> bram3/1
  debus_dina/4(lsb_out1) -> bram3/2
  debus_wea/4(lsb_out1) -> bram3/3
  debus_addrb/4(lsb_out1) -> bram3/4
  debus_dinb/4(lsb_out1) -> bram3/5
  debus_web/4(lsb_out1) -> bram3/6
  bram0/1 -> A_bussify/1(in1)
  bram0/2 -> B_bussify/1(in1)
  bram1/1 -> A_bussify/2(in2)
  bram1/2 -> B_bussify/2(in2)
  bram2/1 -> A_bussify/3(in3)
  bram2/2 -> B_bussify/3(in3)
  bram3/1 -> A_bussify/4(in4)
  bram3/2 -> B_bussify/4(in4)
  A_bussify/1(bus_out) -> A/1
  B_bussify/1(bus_out) -> B/1

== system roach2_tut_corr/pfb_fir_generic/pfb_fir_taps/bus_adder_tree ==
  d0 : Inport
  d1 : Inport  Port=2
  d2 : Inport  Port=3
  d3 : Inport  Port=4
  add_tree0 : Subsystem  AncestorBlock=casper_library_misc/adder_tree
  add_tree1 : Subsystem  AncestorBlock=casper_library_misc/adder_tree
  add_tree10 : Subsystem  AncestorBlock=casper_library_misc/adder_tree
  add_tree11 : Subsystem  AncestorBlock=casper_library_misc/adder_tree
  add_tree12 : Subsystem  AncestorBlock=casper_library_misc/adder_tree
  add_tree13 : Subsystem  AncestorBlock=casper_library_misc/adder_tree
  add_tree14 : Subsystem  AncestorBlock=casper_library_misc/adder_tree
  add_tree15 : Subsystem  AncestorBlock=casper_library_misc/adder_tree
  add_tree2 : Subsystem  AncestorBlock=casper_library_misc/adder_tree
  add_tree3 : Subsystem  AncestorBlock=casper_library_misc/adder_tree
  add_tree4 : Subsystem  AncestorBlock=casper_library_misc/adder_tree
  add_tree5 : Subsystem  AncestorBlock=casper_library_misc/adder_tree
  add_tree6 : Subsystem  AncestorBlock=casper_library_misc/adder_tree
  add_tree7 : Subsystem  AncestorBlock=casper_library_misc/adder_tree
  add_tree8 : Subsystem  AncestorBlock=casper_library_misc/adder_tree
  add_tree9 : Subsystem  AncestorBlock=casper_library_misc/adder_tree
  constant : xbsIndex_r4/Constant  const=0  gui_display_data_type=Fixed-point  arith_type=Boolean  n_bits=16  bin_pt=14  preci_type=Single  exp_width=8  frac_width=24  explicit_period=on  period=1  equ=P=C  opselect=C  inp2=PCIN>>17  opr=+  inp1=P  carry=CIN  dbl_ovrd=off  block_type=constant
  d_bussify : Subsystem  AncestorBlock=casper_library_flow_control/bus_create
  expand0 : Subsystem  AncestorBlock=casper_library_flow_control/bus_expand
  expand1 : Subsystem  AncestorBlock=casper_library_flow_control/bus_expand
  expand2 : Subsystem  AncestorBlock=casper_library_flow_control/bus_expand
  expand3 : Subsystem  AncestorBlock=casper_library_flow_control/bus_expand
  out : Outport
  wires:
  d0/1 -> expand0/1(bus_in)
  d1/1 -> expand1/1(bus_in)
  d2/1 -> expand2/1(bus_in)
  d3/1 -> expand3/1(bus_in)
  constant/1 -> add_tree0/1(sync), add_tree1/1(sync), add_tree2/1(sync), add_tree3/1(sync), add_tree4/1(sync), add_tree5/1(sync), add_tree6/1(sync), add_tree7/1(sync), add_tree8/1(sync), add_tree9/1(sync), add_tree10/1(sync), add_tree11/1(sync), add_tree12/1(sync), add_tree13/1(sync), add_tree14/1(sync), add_tree15/1(sync)
  expand0/1(msb_out16) -> add_tree0/2(din1)
  expand1/1(msb_out16) -> add_tree0/3(din2)
  expand2/1(msb_out16) -> add_tree0/4(din3)
  expand3/1(msb_out16) -> add_tree0/5(din4)
  expand0/2(out15) -> add_tree1/2(din1)
  expand1/2(out15) -> add_tree1/3(din2)
  expand2/2(out15) -> add_tree1/4(din3)
  expand3/2(out15) -> add_tree1/5(din4)
  expand0/3(out14) -> add_tree2/2(din1)
  expand1/3(out14) -> add_tree2/3(din2)
  expand2/3(out14) -> add_tree2/4(din3)
  expand3/3(out14) -> add_tree2/5(din4)
  expand0/4(out13) -> add_tree3/2(din1)
  expand1/4(out13) -> add_tree3/3(din2)
  expand2/4(out13) -> add_tree3/4(din3)
  expand3/4(out13) -> add_tree3/5(din4)
  expand0/5(out12) -> add_tree4/2(din1)
  expand1/5(out12) -> add_tree4/3(din2)
  expand2/5(out12) -> add_tree4/4(din3)
  expand3/5(out12) -> add_tree4/5(din4)
  expand0/6(out11) -> add_tree5/2(din1)
  expand1/6(out11) -> add_tree5/3(din2)
  expand2/6(out11) -> add_tree5/4(din3)
  expand3/6(out11) -> add_tree5/5(din4)
  expand0/7(out10) -> add_tree6/2(din1)
  expand1/7(out10) -> add_tree6/3(din2)
  expand2/7(out10) -> add_tree6/4(din3)
  expand3/7(out10) -> add_tree6/5(din4)
  expand0/8(out9) -> add_tree7/2(din1)
  expand1/8(out9) -> add_tree7/3(din2)
  expand2/8(out9) -> add_tree7/4(din3)
  expand3/8(out9) -> add_tree7/5(din4)
  expand0/9(out8) -> add_tree8/2(din1)
  expand1/9(out8) -> add_tree8/3(din2)
  expand2/9(out8) -> add_tree8/4(din3)
  expand3/9(out8) -> add_tree8/5(din4)
  expand0/10(out7) -> add_tree9/2(din1)
  expand1/10(out7) -> add_tree9/3(din2)
  expand2/10(out7) -> add_tree9/4(din3)
  expand3/10(out7) -> add_tree9/5(din4)
  expand0/11(out6) -> add_tree10/2(din1)
  expand1/11(out6) -> add_tree10/3(din2)
  expand2/11(out6) -> add_tree10/4(din3)
  expand3/11(out6) -> add_tree10/5(din4)
  expand0/12(out5) -> add_tree11/2(din1)
  expand1/12(out5) -> add_tree11/3(din2)
  expand2/12(out5) -> add_tree11/4(din3)
  expand3/12(out5) -> add_tree11/5(din4)
  expand0/13(out4) -> add_tree12/2(din1)
  expand1/13(out4) -> add_tree12/3(din2)
  expand2/13(out4) -> add_tree12/4(din3)
  expand3/13(out4) -> add_tree12/5(din4)
  expand0/14(out3) -> add_tree13/2(din1)
  expand1/14(out3) -> add_tree13/3(din2)
  expand2/14(out3) -> add_tree13/4(din3)
  expand3/14(out3) -> add_tree13/5(din4)
  expand0/15(out2) -> add_tree14/2(din1)
  expand1/15(out2) -> add_tree14/3(din2)
  expand2/15(out2) -> add_tree14/4(din3)
  expand3/15(out2) -> add_tree14/5(din4)
  expand0/16(lsb_out1) -> add_tree15/2(din1)
  expand1/16(lsb_out1) -> add_tree15/3(din2)
  expand2/16(lsb_out1) -> add_tree15/4(din3)
  expand3/16(lsb_out1) -> add_tree15/5(din4)
  add_tree0/2(dout) -> d_bussify/1(in1)
  add_tree1/2(dout) -> d_bussify/2(in2)
  add_tree2/2(dout) -> d_bussify/3(in3)
  add_tree3/2(dout) -> d_bussify/4(in4)
  add_tree4/2(dout) -> d_bussify/5(in5)
  add_tree5/2(dout) -> d_bussify/6(in6)
  add_tree6/2(dout) -> d_bussify/7(in7)
  add_tree7/2(dout) -> d_bussify/8(in8)
  add_tree8/2(dout) -> d_bussify/9(in9)
  add_tree9/2(dout) -> d_bussify/10(in10)
  add_tree10/2(dout) -> d_bussify/11(in11)
  add_tree11/2(dout) -> d_bussify/12(in12)
  add_tree12/2(dout) -> d_bussify/13(in13)
  add_tree13/2(dout) -> d_bussify/14(in14)
  add_tree14/2(dout) -> d_bussify/15(in15)
  add_tree15/2(dout) -> d_bussify/16(in16)
  d_bussify/1(bus_out) -> out/1

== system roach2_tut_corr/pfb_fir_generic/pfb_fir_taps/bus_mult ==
  a : Inport
  b : Inport  Port=2
  a*b_bussify : Subsystem  AncestorBlock=casper_library_flow_control/bus_create
  a_debus : Subsystem  AncestorBlock=casper_library_flow_control/bus_expand
  b_debus : Subsystem  AncestorBlock=casper_library_flow_control/bus_expand
  mult{1..64} (64 alike) : xbsIndex_r4/Mult  precision=User Defined  arith_type="Signed  (2's comp)"  n_bits=26  bin_pt=24  quantization=Truncate  overflow=Wrap  en=off  latency=mult_latency  dbl_ovrd=off  use_behavioral_HDL=on  opt=Speed  use_embedded=off  optimum_pipeline=off  pipeline=on  use_rpm=on  placement_style=Triangular  block_type=mult
  repa : Subsystem  AncestorBlock=casper_library_bus/bus_replicate
  repb : Subsystem  AncestorBlock=casper_library_bus/bus_replicate
  a*b : Outport
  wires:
  a/1 -> repa/1(in)
  b/1 -> repb/1(in)
  repa/1(out) -> a_debus/1(bus_in)
  repb/1(out) -> b_debus/1(bus_in)
  a_debus/1(msb_out64) -> mult1/1
  b_debus/1(msb_out64) -> mult1/2
  a_debus/2(out63) -> mult2/1
  b_debus/2(out63) -> mult2/2
  a_debus/3(out62) -> mult3/1
  b_debus/3(out62) -> mult3/2
  a_debus/4(out61) -> mult4/1
  b_debus/4(out61) -> mult4/2
  a_debus/5(out60) -> mult5/1
  b_debus/5(out60) -> mult5/2
  a_debus/6(out59) -> mult6/1
  b_debus/6(out59) -> mult6/2
  a_debus/7(out58) -> mult7/1
  b_debus/7(out58) -> mult7/2
  a_debus/8(out57) -> mult8/1
  b_debus/8(out57) -> mult8/2
  a_debus/9(out56) -> mult9/1
  b_debus/9(out56) -> mult9/2
  a_debus/10(out55) -> mult10/1
  b_debus/10(out55) -> mult10/2
  a_debus/11(out54) -> mult11/1
  b_debus/11(out54) -> mult11/2
  a_debus/12(out53) -> mult12/1
  b_debus/12(out53) -> mult12/2
  a_debus/13(out52) -> mult13/1
  b_debus/13(out52) -> mult13/2
  a_debus/14(out51) -> mult14/1
  b_debus/14(out51) -> mult14/2
  a_debus/15(out50) -> mult15/1
  b_debus/15(out50) -> mult15/2
  a_debus/16(out49) -> mult16/1
  b_debus/16(out49) -> mult16/2
  a_debus/17(out48) -> mult17/1
  b_debus/17(out48) -> mult17/2
  a_debus/18(out47) -> mult18/1
  b_debus/18(out47) -> mult18/2
  a_debus/19(out46) -> mult19/1
  b_debus/19(out46) -> mult19/2
  a_debus/20(out45) -> mult20/1
  b_debus/20(out45) -> mult20/2
  a_debus/21(out44) -> mult21/1
  b_debus/21(out44) -> mult21/2
  a_debus/22(out43) -> mult22/1
  b_debus/22(out43) -> mult22/2
  a_debus/23(out42) -> mult23/1
  b_debus/23(out42) -> mult23/2
  a_debus/24(out41) -> mult24/1
  b_debus/24(out41) -> mult24/2
  a_debus/25(out40) -> mult25/1
  b_debus/25(out40) -> mult25/2
  a_debus/26(out39) -> mult26/1
  b_debus/26(out39) -> mult26/2
  a_debus/27(out38) -> mult27/1
  b_debus/27(out38) -> mult27/2
  a_debus/28(out37) -> mult28/1
  b_debus/28(out37) -> mult28/2
  a_debus/29(out36) -> mult29/1
  b_debus/29(out36) -> mult29/2
  a_debus/30(out35) -> mult30/1
  b_debus/30(out35) -> mult30/2
  a_debus/31(out34) -> mult31/1
  b_debus/31(out34) -> mult31/2
  a_debus/32(out33) -> mult32/1
  b_debus/32(out33) -> mult32/2
  a_debus/33(out32) -> mult33/1
  b_debus/33(out32) -> mult33/2
  a_debus/34(out31) -> mult34/1
  b_debus/34(out31) -> mult34/2
  a_debus/35(out30) -> mult35/1
  b_debus/35(out30) -> mult35/2
  a_debus/36(out29) -> mult36/1
  b_debus/36(out29) -> mult36/2
  a_debus/37(out28) -> mult37/1
  b_debus/37(out28) -> mult37/2
  a_debus/38(out27) -> mult38/1
  b_debus/38(out27) -> mult38/2
  a_debus/39(out26) -> mult39/1
  b_debus/39(out26) -> mult39/2
  a_debus/40(out25) -> mult40/1
  b_debus/40(out25) -> mult40/2
  a_debus/41(out24) -> mult41/1
  b_debus/41(out24) -> mult41/2
  a_debus/42(out23) -> mult42/1
  b_debus/42(out23) -> mult42/2
  a_debus/43(out22) -> mult43/1
  b_debus/43(out22) -> mult43/2
  a_debus/44(out21) -> mult44/1
  b_debus/44(out21) -> mult44/2
  a_debus/45(out20) -> mult45/1
  b_debus/45(out20) -> mult45/2
  a_debus/46(out19) -> mult46/1
  b_debus/46(out19) -> mult46/2
  a_debus/47(out18) -> mult47/1
  b_debus/47(out18) -> mult47/2
  a_debus/48(out17) -> mult48/1
  b_debus/48(out17) -> mult48/2
  a_debus/49(out16) -> mult49/1
  b_debus/49(out16) -> mult49/2
  a_debus/50(out15) -> mult50/1
  b_debus/50(out15) -> mult50/2
  a_debus/51(out14) -> mult51/1
  b_debus/51(out14) -> mult51/2
  a_debus/52(out13) -> mult52/1
  b_debus/52(out13) -> mult52/2
  a_debus/53(out12) -> mult53/1
  b_debus/53(out12) -> mult53/2
  a_debus/54(out11) -> mult54/1
  b_debus/54(out11) -> mult54/2
  a_debus/55(out10) -> mult55/1
  b_debus/55(out10) -> mult55/2
  a_debus/56(out9) -> mult56/1
  b_debus/56(out9) -> mult56/2
  a_debus/57(out8) -> mult57/1
  b_debus/57(out8) -> mult57/2
  a_debus/58(out7) -> mult58/1
  b_debus/58(out7) -> mult58/2
  a_debus/59(out6) -> mult59/1
  b_debus/59(out6) -> mult59/2
  a_debus/60(out5) -> mult60/1
  b_debus/60(out5) -> mult60/2
  a_debus/61(out4) -> mult61/1
  b_debus/61(out4) -> mult61/2
  a_debus/62(out3) -> mult62/1
  b_debus/62(out3) -> mult62/2
  a_debus/63(out2) -> mult63/1
  b_debus/63(out2) -> mult63/2
  a_debus/64(lsb_out1) -> mult64/1
  b_debus/64(lsb_out1) -> mult64/2
  mult1/1 -> a*b_bussify/1(in1)
  mult2/1 -> a*b_bussify/2(in2)
  mult3/1 -> a*b_bussify/3(in3)
  mult4/1 -> a*b_bussify/4(in4)
  mult5/1 -> a*b_bussify/5(in5)
  mult6/1 -> a*b_bussify/6(in6)
  mult7/1 -> a*b_bussify/7(in7)
  mult8/1 -> a*b_bussify/8(in8)
  mult9/1 -> a*b_bussify/9(in9)
  mult10/1 -> a*b_bussify/10(in10)
  mult11/1 -> a*b_bussify/11(in11)
  mult12/1 -> a*b_bussify/12(in12)
  mult13/1 -> a*b_bussify/13(in13)
  mult14/1 -> a*b_bussify/14(in14)
  mult15/1 -> a*b_bussify/15(in15)
  mult16/1 -> a*b_bussify/16(in16)
  mult17/1 -> a*b_bussify/17(in17)
  mult18/1 -> a*b_bussify/18(in18)
  mult19/1 -> a*b_bussify/19(in19)
  mult20/1 -> a*b_bussify/20(in20)
  mult21/1 -> a*b_bussify/21(in21)
  mult22/1 -> a*b_bussify/22(in22)
  mult23/1 -> a*b_bussify/23(in23)
  mult24/1 -> a*b_bussify/24(in24)
  mult25/1 -> a*b_bussify/25(in25)
  mult26/1 -> a*b_bussify/26(in26)
  mult27/1 -> a*b_bussify/27(in27)
  mult28/1 -> a*b_bussify/28(in28)
  mult29/1 -> a*b_bussify/29(in29)
  mult30/1 -> a*b_bussify/30(in30)
  mult31/1 -> a*b_bussify/31(in31)
  mult32/1 -> a*b_bussify/32(in32)
  mult33/1 -> a*b_bussify/33(in33)
  mult34/1 -> a*b_bussify/34(in34)
  mult35/1 -> a*b_bussify/35(in35)
  mult36/1 -> a*b_bussify/36(in36)
  mult37/1 -> a*b_bussify/37(in37)
  mult38/1 -> a*b_bussify/38(in38)
  mult39/1 -> a*b_bussify/39(in39)
  mult40/1 -> a*b_bussify/40(in40)
  mult41/1 -> a*b_bussify/41(in41)
  mult42/1 -> a*b_bussify/42(in42)
  mult43/1 -> a*b_bussify/43(in43)
  mult44/1 -> a*b_bussify/44(in44)
  mult45/1 -> a*b_bussify/45(in45)
  mult46/1 -> a*b_bussify/46(in46)
  mult47/1 -> a*b_bussify/47(in47)
  mult48/1 -> a*b_bussify/48(in48)
  mult49/1 -> a*b_bussify/49(in49)
  mult50/1 -> a*b_bussify/50(in50)
  mult51/1 -> a*b_bussify/51(in51)
  mult52/1 -> a*b_bussify/52(in52)
  mult53/1 -> a*b_bussify/53(in53)
  mult54/1 -> a*b_bussify/54(in54)
  mult55/1 -> a*b_bussify/55(in55)
  mult56/1 -> a*b_bussify/56(in56)
  mult57/1 -> a*b_bussify/57(in57)
  mult58/1 -> a*b_bussify/58(in58)
  mult59/1 -> a*b_bussify/59(in59)
  mult60/1 -> a*b_bussify/60(in60)
  mult61/1 -> a*b_bussify/61(in61)
  mult62/1 -> a*b_bussify/62(in62)
  mult63/1 -> a*b_bussify/63(in63)
  mult64/1 -> a*b_bussify/64(in64)
  a*b_bussify/1(bus_out) -> a*b/1

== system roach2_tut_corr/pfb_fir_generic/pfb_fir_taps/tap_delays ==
  addra : Inport
  dina : Inport  Port=2
  wea : Inport  Port=3
  addrb : Inport  Port=4
  dinb : Inport  Port=5
  web : Inport  Port=6
  A_bussify : Subsystem  AncestorBlock=casper_library_flow_control/bus_create
  B_bussify : Subsystem  AncestorBlock=casper_library_flow_control/bus_create
  bram{0..10} (11 alike) : xbsIndex_r4/Dual Port RAM  depth=512  initVector=getfield(get_param(gcb, 'UserData'), 'initVector')  distributed_mem=Block RAM  init_a=0  init_b=0  rst_a=off  rst_b=off  en_a=off  en_b=off  latency=3  write_mode_A=Read Before Write  write_mode_B=Read Before Write  dbl_ovrd=off  optimize=Speed  block_type=dpram
  ddina : xbsIndex_r4/Delay  rst=off  infoeditControl=Selection of Reset will increase slice count due to use of real FFs and instead of SRLs  en=off  latency=0  dbl_ovrd=off  reg_retiming=on  block_type=delay
  ddinb : xbsIndex_r4/Delay  rst=off  infoeditControl=Selection of Reset will increase slice count due to use of real FFs and instead of SRLs  en=off  latency=1  dbl_ovrd=off  reg_retiming=off  block_type=delay
  debus_addra : Subsystem  AncestorBlock=casper_library_flow_control/bus_expand
  debus_addrb : Subsystem  AncestorBlock=casper_library_flow_control/bus_expand
  debus_dina : Subsystem  AncestorBlock=casper_library_flow_control/bus_expand
  debus_dinb : Subsystem  AncestorBlock=casper_library_flow_control/bus_expand
  debus_wea : Subsystem  AncestorBlock=casper_library_flow_control/bus_expand
  debus_web : Subsystem  AncestorBlock=casper_library_flow_control/bus_expand
  rep_addra : Subsystem  AncestorBlock=casper_library_bus/bus_replicate
  rep_addrb : Subsystem  AncestorBlock=casper_library_bus/bus_replicate
  rep_wea : Subsystem  AncestorBlock=casper_library_bus/bus_replicate
  rep_web : Subsystem  AncestorBlock=casper_library_bus/bus_replicate
  A : Outport
  B : Outport  Port=2
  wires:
  addra/1 -> rep_addra/1(in)
  dina/1 -> ddina/1
  wea/1 -> rep_wea/1(in)
  addrb/1 -> rep_addrb/1(in)
  dinb/1 -> ddinb/1
  web/1 -> rep_web/1(in)
  rep_addra/1(out) -> debus_addra/1(bus_in)
  ddina/1 -> debus_dina/1(bus_in)
  rep_wea/1(out) -> debus_wea/1(bus_in)
  rep_addrb/1(out) -> debus_addrb/1(bus_in)
  ddinb/1 -> debus_dinb/1(bus_in)
  rep_web/1(out) -> debus_web/1(bus_in)
  debus_addra/1(msb_out11) -> bram0/1
  debus_dina/1(msb_out11) -> bram0/2
  debus_wea/1(msb_out11) -> bram0/3
  debus_addrb/1(msb_out11) -> bram0/4
  debus_dinb/1(msb_out11) -> bram0/5
  debus_web/1(msb_out11) -> bram0/6
  debus_addra/2(out10) -> bram1/1
  debus_dina/2(out10) -> bram1/2
  debus_wea/2(out10) -> bram1/3
  debus_addrb/2(out10) -> bram1/4
  debus_dinb/2(out10) -> bram1/5
  debus_web/2(out10) -> bram1/6
  debus_addra/3(out9) -> bram2/1
  debus_dina/3(out9) -> bram2/2
  debus_wea/3(out9) -> bram2/3
  debus_addrb/3(out9) -> bram2/4
  debus_dinb/3(out9) -> bram2/5
  debus_web/3(out9) -> bram2/6
  debus_addra/4(out8) -> bram3/1
  debus_dina/4(out8) -> bram3/2
  debus_wea/4(out8) -> bram3/3
  debus_addrb/4(out8) -> bram3/4
  debus_dinb/4(out8) -> bram3/5
  debus_web/4(out8) -> bram3/6
  debus_addra/5(out7) -> bram4/1
  debus_dina/5(out7) -> bram4/2
  debus_wea/5(out7) -> bram4/3
  debus_addrb/5(out7) -> bram4/4
  debus_dinb/5(out7) -> bram4/5
  debus_web/5(out7) -> bram4/6
  debus_addra/6(out6) -> bram5/1
  debus_dina/6(out6) -> bram5/2
  debus_wea/6(out6) -> bram5/3
  debus_addrb/6(out6) -> bram5/4
  debus_dinb/6(out6) -> bram5/5
  debus_web/6(out6) -> bram5/6
  debus_addra/7(out5) -> bram6/1
  debus_dina/7(out5) -> bram6/2
  debus_wea/7(out5) -> bram6/3
  debus_addrb/7(out5) -> bram6/4
  debus_dinb/7(out5) -> bram6/5
  debus_web/7(out5) -> bram6/6
  debus_addra/8(out4) -> bram7/1
  debus_dina/8(out4) -> bram7/2
  debus_wea/8(out4) -> bram7/3
  debus_addrb/8(out4) -> bram7/4
  debus_dinb/8(out4) -> bram7/5
  debus_web/8(out4) -> bram7/6
  debus_addra/9(out3) -> bram8/1
  debus_dina/9(out3) -> bram8/2
  debus_wea/9(out3) -> bram8/3
  debus_addrb/9(out3) -> bram8/4
  debus_dinb/9(out3) -> bram8/5
  debus_web/9(out3) -> bram8/6
  debus_addra/10(out2) -> bram9/1
  debus_dina/10(out2) -> bram9/2
  debus_wea/10(out2) -> bram9/3
  debus_addrb/10(out2) -> bram9/4
  debus_dinb/10(out2) -> bram9/5
  debus_web/10(out2) -> bram9/6
  debus_addra/11(lsb_out1) -> bram10/1
  debus_dina/11(lsb_out1) -> bram10/2
  debus_wea/11(lsb_out1) -> bram10/3
  debus_addrb/11(lsb_out1) -> bram10/4
  debus_dinb/11(lsb_out1) -> bram10/5
  debus_web/11(lsb_out1) -> bram10/6
  bram0/1 -> A_bussify/1(in1)
  bram0/2 -> B_bussify/1(in1)
  bram1/1 -> A_bussify/2(in2)
  bram1/2 -> B_bussify/2(in2)
  bram2/1 -> A_bussify/3(in3)
  bram2/2 -> B_bussify/3(in3)
  bram3/1 -> A_bussify/4(in4)
  bram3/2 -> B_bussify/4(in4)
  bram4/1 -> A_bussify/5(in5)
  bram4/2 -> B_bussify/5(in5)
  bram5/1 -> A_bussify/6(in6)
  bram5/2 -> B_bussify/6(in6)
  bram6/1 -> A_bussify/7(in7)
  bram6/2 -> B_bussify/7(in7)
  bram7/1 -> A_bussify/8(in8)
  bram7/2 -> B_bussify/8(in8)
  bram8/1 -> A_bussify/9(in9)
  bram8/2 -> B_bussify/9(in9)
  bram9/1 -> A_bussify/10(in10)
  bram9/2 -> B_bussify/10(in10)
  bram10/1 -> A_bussify/11(in11)
  bram10/2 -> B_bussify/11(in11)
  A_bussify/1(bus_out) -> A/1
  B_bussify/1(bus_out) -> B/1

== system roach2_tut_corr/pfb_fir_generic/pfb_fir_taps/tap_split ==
  bus_in : Inport
  reinterpret{1..4} (4 alike) : xbsIndex_r4/Reinterpret  force_arith_type=on  arith_type=Unsigned  force_bin_pt=on  bin_pt=0  block_type=reinterpret
  slice1 : xbsIndex_r4/Slice  nbits=416  boolean_output=off  mode=Upper Bit Location + Width  bit1=-1248  base1=MSB of Input  bit0=0  base0=LSB of Input  dbl_ovrd=off  block_type=slice
  slice2 : xbsIndex_r4/Slice  nbits=416  boolean_output=off  mode=Upper Bit Location + Width  bit1=-832  base1=MSB of Input  bit0=0  base0=LSB of Input  dbl_ovrd=off  block_type=slice
  slice3 : xbsIndex_r4/Slice  nbits=416  boolean_output=off  mode=Upper Bit Location + Width  bit1=-416  base1=MSB of Input  bit0=0  base0=LSB of Input  dbl_ovrd=off  block_type=slice
  slice4 : xbsIndex_r4/Slice  nbits=416  boolean_output=off  mode=Upper Bit Location + Width  bit1=0  base1=MSB of Input  bit0=0  base0=LSB of Input  dbl_ovrd=off  block_type=slice
  msb_out4 : Outport
  out3 : Outport  Port=2
  out2 : Outport  Port=3
  lsb_out1 : Outport  Port=4
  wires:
  bus_in/1 -> slice4/1, slice3/1, slice2/1, slice1/1
  slice4/1 -> reinterpret4/1
  reinterpret4/1 -> msb_out4/1
  slice3/1 -> reinterpret3/1
  reinterpret3/1 -> out3/1
  slice2/1 -> reinterpret2/1
  reinterpret2/1 -> out2/1
  slice1/1 -> reinterpret1/1
  reinterpret1/1 -> lsb_out1/1

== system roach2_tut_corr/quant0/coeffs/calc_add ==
  note: Use behavioural HDL so that gets optimised to minimum logic
  note: If reading/writing words smaller than 32 bits, change address so that addressing is big endian instead of little, otherwise pass through
  in : Inport
  add_sub : xbsIndex_r4/AddSub  mode=Subtraction  use_carryin=off  use_carryout=off  en=off  latency=0  precision=User Defined  arith_type=Unsigned  n_bits=max(1, log2(32/data_width))  bin_pt=0  quantization=Truncate  overflow=Wrap  dbl_ovrd=off  use_behavioral_HDL=on  hw_selection=Fabric  pipelined=off  block_type=addsub
  concat : xbsIndex_r4/Concat  num_inputs=2  dbl_ovrd=off  block_type=concat
  const : xbsIndex_r4/Constant  const=max(0, 32/data_width-1)  gui_display_data_type=Fixed-point  arith_type=Unsigned  n_bits=max(1, log2(32/data_width))  bin_pt=0  preci_type=Single  exp_width=8  frac_width=24  explicit_period=on  period=sample_rate  equ=P=C  opselect=C  inp2=PCIN>>17  opr=+  inp1=P  carry=CIN  dbl_ovrd=off  block_type=constant
  convert_addr : xbsIndex_r4/Convert  gui_display_data_type=Fixed-point  arith_type=Unsigned  n_bits=addr_width  bin_pt=0  float_type=Single  exp_bits=8  fraction_bits=24  quantization=Truncate  overflow=Wrap  en=off  latency=0  dbl_ovrd=off  pipeline=off  block_type=convert
  lsw : xbsIndex_r4/Slice  nbits=max(1, log2(32/data_width))  boolean_output=off  mode=Lower Bit Location + Width  bit1=0  base1=MSB of Input  bit0=0  base0=LSB of Input  dbl_ovrd=off  block_type=slice
  manipulate : xbsIndex_r4/Constant  const=min(1, floor(32/data_width) - 1)  gui_display_data_type=Fixed-point  arith_type=Unsigned  n_bits=1  bin_pt=0  preci_type=Single  exp_width=8  frac_width=24  explicit_period=on  period=sample_rate  equ=P=C  opselect=C  inp2=PCIN>>17  opr=+  inp1=P  carry=CIN  dbl_ovrd=off  block_type=constant
  msw : xbsIndex_r4/Slice  nbits=addr_width - max(1, log2(32/data_width))  boolean_output=off  mode=Upper Bit Location + Width  bit1=0  base1=MSB of Input  bit0=0  base0=LSB of Input  dbl_ovrd=off  block_type=slice
  mux : xbsIndex_r4/Mux  inputs=2  en=off  latency=0  precision=Full  arith_type=Unsigned  n_bits=16  bin_pt=14  quantization=Truncate  overflow=Wrap  dbl_ovrd=off  block_type=mux
  out : Outport
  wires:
  convert_addr/1 -> mux/2, msw/1, lsw/1
  const/1 -> add_sub/1
  lsw/1 -> add_sub/2
  mux/1 -> out/1
  manipulate/1 -> mux/1
  concat/1 -> mux/3
  msw/1 -> concat/1
  add_sub/1 -> concat/2
  in/1 -> convert_addr/1

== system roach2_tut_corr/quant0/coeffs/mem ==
  note: Undo data manipulation on way in and redo on way out for simulated data
  note: Undo address manipulation for simulated data
  In1 : Inport
  In2 : Inport  Port=2
  In3 : Inport  Port=3
  Disregard Subsystem : xbsIndex_r4/Disregard Subsystem  Tag=discardX  block_type=disregard
  calc_add : Subsystem
  ram : xbsIndex_r4/Single Port RAM  depth=2^addr_width  initVector=init_vals  distributed_mem=Block RAM  write_mode=Read After Write  rst=off  init_reg=0  en=off  latency=1  dbl_ovrd=off  optimize=Area  block_type=spram
  sim_addr : xbsIndex_r4/Gateway In  gui_display_data_type=Fixed-point  arith_type=Unsigned  n_bits=addr_width  bin_pt=0  preci_type=Single  exp_width=8  frac_width=24  quantization=Truncate  overflow=Wrap  period=sample_rate  dbl_ovrd=off  timing_constraint=None  locs_specified=off  LOCs={}  UseAsADC=off  ADCChannel='1'  inherit_from_input=off  hdl_port=on  block_type=gatewayin
  sim_data_in : xbsIndex_r4/Gateway In  gui_display_data_type=Fixed-point  arith_type=Unsigned  n_bits=32  bin_pt=0  preci_type=Single  exp_width=8  frac_width=24  quantization=Truncate  overflow=Wrap  period=sample_rate  dbl_ovrd=off  timing_constraint=None  locs_specified=off  LOCs={}  UseAsADC=off  ADCChannel='1'  inherit_from_input=off  hdl_port=on  block_type=gatewayin
  sim_data_out : xbsIndex_r4/Gateway Out  inherit_from_input=off  hdl_port=on  timing_constraint=None  locs_specified=off  LOCs={'B21','B22','A22','B23','B19','C19','A20','A21','A23','B24','A24','A25','E18','D18','C18','B18'}  UseAsDAC=off  DACChannel='1'  block_type=gatewayout
  sim_munge_in : Subsystem  AncestorBlock=casper_library_flow_control/munge
  sim_munge_out : Subsystem  AncestorBlock=casper_library_flow_control/munge
  sim_we : xbsIndex_r4/Gateway In  gui_display_data_type=Fixed-point  arith_type=Boolean  n_bits=1  bin_pt=0  preci_type=Single  exp_width=8  frac_width=24  quantization=Truncate  overflow=Wrap  period=sample_rate  dbl_ovrd=off  timing_constraint=None  locs_specified=off  LOCs={}  UseAsADC=off  ADCChannel='1'  inherit_from_input=off  hdl_port=on  block_type=gatewayin
  Out1 : Outport
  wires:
  calc_add/1(out) -> ram/1
  sim_munge_out/1(dout) -> sim_data_out/1
  In1/1 -> sim_addr/1
  In2/1 -> sim_data_in/1
  sim_data_out/1 -> Out1/1
  In3/1 -> sim_we/1
  sim_addr/1 -> calc_add/1(in)
  sim_data_in/1 -> sim_munge_in/1(din)
  sim_we/1 -> ram/3
  ram/1 -> sim_munge_out/1(din)
  sim_munge_in/1(dout) -> ram/2

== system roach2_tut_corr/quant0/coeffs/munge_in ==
  din : Inport
  reinterpret_out : xbsIndex_r4/Reinterpret  force_arith_type=on  arith_type=Unsigned  force_bin_pt=on  bin_pt=0  block_type=reinterpret
  dout : Outport
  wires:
  reinterpret_out/1 -> dout/1
  din/1 -> reinterpret_out/1

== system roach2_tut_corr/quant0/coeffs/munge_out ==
  din : Inport
  reinterpret_out : xbsIndex_r4/Reinterpret  force_arith_type=on  arith_type=Unsigned  force_bin_pt=on  bin_pt=0  block_type=reinterpret
  dout : Outport
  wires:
  reinterpret_out/1 -> dout/1
  din/1 -> reinterpret_out/1

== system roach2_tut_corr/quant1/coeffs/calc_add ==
  note: Use behavioural HDL so that gets optimised to minimum logic
  note: If reading/writing words smaller than 32 bits, change address so that addressing is big endian instead of little, otherwise pass through
  in : Inport
  add_sub : xbsIndex_r4/AddSub  mode=Subtraction  use_carryin=off  use_carryout=off  en=off  latency=0  precision=User Defined  arith_type=Unsigned  n_bits=max(1, log2(32/data_width))  bin_pt=0  quantization=Truncate  overflow=Wrap  dbl_ovrd=off  use_behavioral_HDL=on  hw_selection=Fabric  pipelined=off  block_type=addsub
  concat : xbsIndex_r4/Concat  num_inputs=2  dbl_ovrd=off  block_type=concat
  const : xbsIndex_r4/Constant  const=max(0, 32/data_width-1)  gui_display_data_type=Fixed-point  arith_type=Unsigned  n_bits=max(1, log2(32/data_width))  bin_pt=0  preci_type=Single  exp_width=8  frac_width=24  explicit_period=on  period=sample_rate  equ=P=C  opselect=C  inp2=PCIN>>17  opr=+  inp1=P  carry=CIN  dbl_ovrd=off  block_type=constant
  convert_addr : xbsIndex_r4/Convert  gui_display_data_type=Fixed-point  arith_type=Unsigned  n_bits=addr_width  bin_pt=0  float_type=Single  exp_bits=8  fraction_bits=24  quantization=Truncate  overflow=Wrap  en=off  latency=0  dbl_ovrd=off  pipeline=off  block_type=convert
  lsw : xbsIndex_r4/Slice  nbits=max(1, log2(32/data_width))  boolean_output=off  mode=Lower Bit Location + Width  bit1=0  base1=MSB of Input  bit0=0  base0=LSB of Input  dbl_ovrd=off  block_type=slice
  manipulate : xbsIndex_r4/Constant  const=min(1, floor(32/data_width) - 1)  gui_display_data_type=Fixed-point  arith_type=Unsigned  n_bits=1  bin_pt=0  preci_type=Single  exp_width=8  frac_width=24  explicit_period=on  period=sample_rate  equ=P=C  opselect=C  inp2=PCIN>>17  opr=+  inp1=P  carry=CIN  dbl_ovrd=off  block_type=constant
  msw : xbsIndex_r4/Slice  nbits=addr_width - max(1, log2(32/data_width))  boolean_output=off  mode=Upper Bit Location + Width  bit1=0  base1=MSB of Input  bit0=0  base0=LSB of Input  dbl_ovrd=off  block_type=slice
  mux : xbsIndex_r4/Mux  inputs=2  en=off  latency=0  precision=Full  arith_type=Unsigned  n_bits=16  bin_pt=14  quantization=Truncate  overflow=Wrap  dbl_ovrd=off  block_type=mux
  out : Outport
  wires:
  convert_addr/1 -> mux/2, msw/1, lsw/1
  const/1 -> add_sub/1
  lsw/1 -> add_sub/2
  mux/1 -> out/1
  manipulate/1 -> mux/1
  concat/1 -> mux/3
  msw/1 -> concat/1
  add_sub/1 -> concat/2
  in/1 -> convert_addr/1
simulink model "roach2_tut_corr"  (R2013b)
settings: Solver=VariableStepDiscrete  SolverMode=SingleTasking  StartTime=0.0  StopTime=100  RelTol=1e-3
undefined symbols (not defined in the file): add_latency, addr_width, Bit, bitfield, BitWidth, bram_latency, burst_size, casper_library_scopes, conv_latency, data_width, DelayLen, fan_latency, FFTSize, FFTStage, getfield, increment, led, Location, Lower, mult_latency, mux_latency, n_bits, n_bits_data, n_inputs, n_streams, n_taps, neg_latency, negate_latency, nsamples, pfb_size, pulse_len, reset_period, ROACH, ROACH2, snapshot, sx475t, sync_period, sync_period_bits, Upper, UseCounter, Width
libraries: xbsIndex_r4 x24444, casper_library_misc x73, xbsReplacements_r4 x34, casper_library_delays x14, xps_library x7
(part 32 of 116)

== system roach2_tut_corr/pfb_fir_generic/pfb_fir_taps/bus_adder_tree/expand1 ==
  bus_in : Inport
  reinterpret{1..16} (16 alike) : xbsIndex_r4/Reinterpret  force_arith_type=on  arith_type="Signed  (2's comp)"  force_bin_pt=on  bin_pt=24  block_type=reinterpret
  slice1 : xbsIndex_r4/Slice  nbits=26  boolean_output=off  mode=Upper Bit Location + Width  bit1=-390  base1=MSB of Input  bit0=0  base0=LSB of Input  dbl_ovrd=off  block_type=slice
  slice10 : xbsIndex_r4/Slice  nbits=26  boolean_output=off  mode=Upper Bit Location + Width  bit1=-156  base1=MSB of Input  bit0=0  base0=LSB of Input  dbl_ovrd=off  block_type=slice
  slice11 : xbsIndex_r4/Slice  nbits=26  boolean_output=off  mode=Upper Bit Location + Width  bit1=-130  base1=MSB of Input  bit0=0  base0=LSB of Input  dbl_ovrd=off  block_type=slice
  slice12 : xbsIndex_r4/Slice  nbits=26  boolean_output=off  mode=Upper Bit Location + Width  bit1=-104  base1=MSB of Input  bit0=0  base0=LSB of Input  dbl_ovrd=off  block_type=slice
  slice13 : xbsIndex_r4/Slice  nbits=26  boolean_output=off  mode=Upper Bit Location + Width  bit1=-78  base1=MSB of Input  bit0=0  base0=LSB of Input  dbl_ovrd=off  block_type=slice
  slice14 : xbsIndex_r4/Slice  nbits=26  boolean_output=off  mode=Upper Bit Location + Width  bit1=-52  base1=MSB of Input  bit0=0  base0=LSB of Input  dbl_ovrd=off  block_type=slice
  slice15 : xbsIndex_r4/Slice  nbits=26  boolean_output=off  mode=Upper Bit Location + Width  bit1=-26  base1=MSB of Input  bit0=0  base0=LSB of Input  dbl_ovrd=off  block_type=slice
  slice16 : xbsIndex_r4/Slice  nbits=26  boolean_output=off  mode=Upper Bit Location + Width  bit1=0  base1=MSB of Input  bit0=0  base0=LSB of Input  dbl_ovrd=off  block_type=slice
  slice2 : xbsIndex_r4/Slice  nbits=26  boolean_output=off  mode=Upper Bit Location + Width  bit1=-364  base1=MSB of Input  bit0=0  base0=LSB of Input  dbl_ovrd=off  block_type=slice
  slice3 : xbsIndex_r4/Slice  nbits=26  boolean_output=off  mode=Upper Bit Location + Width  bit1=-338  base1=MSB of Input  bit0=0  base0=LSB of Input  dbl_ovrd=off  block_type=slice
  slice4 : xbsIndex_r4/Slice  nbits=26  boolean_output=off  mode=Upper Bit Location + Width  bit1=-312  base1=MSB of Input  bit0=0  base0=LSB of Input  dbl_ovrd=off  block_type=slice
  slice5 : xbsIndex_r4/Slice  nbits=26  boolean_output=off  mode=Upper Bit Location + Width  bit1=-286  base1=MSB of Input  bit0=0  base0=LSB of Input  dbl_ovrd=off  block_type=slice
  slice6 : xbsIndex_r4/Slice  nbits=26  boolean_output=off  mode=Upper Bit Location + Width  bit1=-260  base1=MSB of Input  bit0=0  base0=LSB of Input  dbl_ovrd=off  block_type=slice
  slice7 : xbsIndex_r4/Slice  nbits=26  boolean_output=off  mode=Upper Bit Location + Width  bit1=-234  base1=MSB of Input  bit0=0  base0=LSB of Input  dbl_ovrd=off  block_type=slice
  slice8 : xbsIndex_r4/Slice  nbits=26  boolean_output=off  mode=Upper Bit Location + Width  bit1=-208  base1=MSB of Input  bit0=0  base0=LSB of Input  dbl_ovrd=off  block_type=slice
  slice9 : xbsIndex_r4/Slice  nbits=26  boolean_output=off  mode=Upper Bit Location + Width  bit1=-182  base1=MSB of Input  bit0=0  base0=LSB of Input  dbl_ovrd=off  block_type=slice
  msb_out16 : Outport
  out15 : Outport  Port=2
  out14 : Outport  Port=3
  out13 : Outport  Port=4
  out12 : Outport  Port=5
  out11 : Outport  Port=6
  out10 : Outport  Port=7
  out9 : Outport  Port=8
  out8 : Outport  Port=9
  out7 : Outport  Port=10
  out6 : Outport  Port=11
  out5 : Outport  Port=12
  out4 : Outport  Port=13
  out3 : Outport  Port=14
  out2 : Outport  Port=15
  lsb_out1 : Outport  Port=16
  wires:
  bus_in/1 -> slice16/1, slice15/1, slice14/1, slice13/1, slice12/1, slice11/1, slice10/1, slice9/1, slice8/1, slice7/1, slice6/1, slice5/1, slice4/1, slice3/1, slice2/1, slice1/1
  slice16/1 -> reinterpret16/1
  reinterpret16/1 -> msb_out16/1
  slice15/1 -> reinterpret15/1
  reinterpret15/1 -> out15/1
  slice14/1 -> reinterpret14/1
  reinterpret14/1 -> out14/1
  slice13/1 -> reinterpret13/1
  reinterpret13/1 -> out13/1
  slice12/1 -> reinterpret12/1
  reinterpret12/1 -> out12/1
  slice11/1 -> reinterpret11/1
  reinterpret11/1 -> out11/1
  slice10/1 -> reinterpret10/1
  reinterpret10/1 -> out10/1
  slice9/1 -> reinterpret9/1
  reinterpret9/1 -> out9/1
  slice8/1 -> reinterpret8/1
  reinterpret8/1 -> out8/1
  slice7/1 -> reinterpret7/1
  reinterpret7/1 -> out7/1
  slice6/1 -> reinterpret6/1
  reinterpret6/1 -> out6/1
  slice5/1 -> reinterpret5/1
  reinterpret5/1 -> out5/1
  slice4/1 -> reinterpret4/1
  reinterpret4/1 -> out4/1
  slice3/1 -> reinterpret3/1
  reinterpret3/1 -> out3/1
  slice2/1 -> reinterpret2/1
  reinterpret2/1 -> out2/1
  slice1/1 -> reinterpret1/1
  reinterpret1/1 -> lsb_out1/1

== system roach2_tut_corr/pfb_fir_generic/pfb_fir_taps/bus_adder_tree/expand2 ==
  bus_in : Inport
  reinterpret{1..16} (16 alike) : xbsIndex_r4/Reinterpret  force_arith_type=on  arith_type="Signed  (2's comp)"  force_bin_pt=on  bin_pt=24  block_type=reinterpret
  slice1 : xbsIndex_r4/Slice  nbits=26  boolean_output=off  mode=Upper Bit Location + Width  bit1=-390  base1=MSB of Input  bit0=0  base0=LSB of Input  dbl_ovrd=off  block_type=slice
  slice10 : xbsIndex_r4/Slice  nbits=26  boolean_output=off  mode=Upper Bit Location + Width  bit1=-156  base1=MSB of Input  bit0=0  base0=LSB of Input  dbl_ovrd=off  block_type=slice
  slice11 : xbsIndex_r4/Slice  nbits=26  boolean_output=off  mode=Upper Bit Location + Width  bit1=-130  base1=MSB of Input  bit0=0  base0=LSB of Input  dbl_ovrd=off  block_type=slice
  slice12 : xbsIndex_r4/Slice  nbits=26  boolean_output=off  mode=Upper Bit Location + Width  bit1=-104  base1=MSB of Input  bit0=0  base0=LSB of Input  dbl_ovrd=off  block_type=slice
  slice13 : xbsIndex_r4/Slice  nbits=26  boolean_output=off  mode=Upper Bit Location + Width  bit1=-78  base1=MSB of Input  bit0=0  base0=LSB of Input  dbl_ovrd=off  block_type=slice
  slice14 : xbsIndex_r4/Slice  nbits=26  boolean_output=off  mode=Upper Bit Location + Width  bit1=-52  base1=MSB of Input  bit0=0  base0=LSB of Input  dbl_ovrd=off  block_type=slice
  slice15 : xbsIndex_r4/Slice  nbits=26  boolean_output=off  mode=Upper Bit Location + Width  bit1=-26  base1=MSB of Input  bit0=0  base0=LSB of Input  dbl_ovrd=off  block_type=slice
  slice16 : xbsIndex_r4/Slice  nbits=26  boolean_output=off  mode=Upper Bit Location + Width  bit1=0  base1=MSB of Input  bit0=0  base0=LSB of Input  dbl_ovrd=off  block_type=slice
  slice2 : xbsIndex_r4/Slice  nbits=26  boolean_output=off  mode=Upper Bit Location + Width  bit1=-364  base1=MSB of Input  bit0=0  base0=LSB of Input  dbl_ovrd=off  block_type=slice
  slice3 : xbsIndex_r4/Slice  nbits=26  boolean_output=off  mode=Upper Bit Location + Width  bit1=-338  base1=MSB of Input  bit0=0  base0=LSB of Input  dbl_ovrd=off  block_type=slice
  slice4 : xbsIndex_r4/Slice  nbits=26  boolean_output=off  mode=Upper Bit Location + Width  bit1=-312  base1=MSB of Input  bit0=0  base0=LSB of Input  dbl_ovrd=off  block_type=slice
  slice5 : xbsIndex_r4/Slice  nbits=26  boolean_output=off  mode=Upper Bit Location + Width  bit1=-286  base1=MSB of Input  bit0=0  base0=LSB of Input  dbl_ovrd=off  block_type=slice
  slice6 : xbsIndex_r4/Slice  nbits=26  boolean_output=off  mode=Upper Bit Location + Width  bit1=-260  base1=MSB of Input  bit0=0  base0=LSB of Input  dbl_ovrd=off  block_type=slice
  slice7 : xbsIndex_r4/Slice  nbits=26  boolean_output=off  mode=Upper Bit Location + Width  bit1=-234  base1=MSB of Input  bit0=0  base0=LSB of Input  dbl_ovrd=off  block_type=slice
  slice8 : xbsIndex_r4/Slice  nbits=26  boolean_output=off  mode=Upper Bit Location + Width  bit1=-208  base1=MSB of Input  bit0=0  base0=LSB of Input  dbl_ovrd=off  block_type=slice
  slice9 : xbsIndex_r4/Slice  nbits=26  boolean_output=off  mode=Upper Bit Location + Width  bit1=-182  base1=MSB of Input  bit0=0  base0=LSB of Input  dbl_ovrd=off  block_type=slice
  msb_out16 : Outport
  out15 : Outport  Port=2
  out14 : Outport  Port=3
  out13 : Outport  Port=4
  out12 : Outport  Port=5
  out11 : Outport  Port=6
  out10 : Outport  Port=7
  out9 : Outport  Port=8
  out8 : Outport  Port=9
  out7 : Outport  Port=10
  out6 : Outport  Port=11
  out5 : Outport  Port=12
  out4 : Outport  Port=13
  out3 : Outport  Port=14
  out2 : Outport  Port=15
  lsb_out1 : Outport  Port=16
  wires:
  bus_in/1 -> slice16/1, slice15/1, slice14/1, slice13/1, slice12/1, slice11/1, slice10/1, slice9/1, slice8/1, slice7/1, slice6/1, slice5/1, slice4/1, slice3/1, slice2/1, slice1/1
  slice16/1 -> reinterpret16/1
  reinterpret16/1 -> msb_out16/1
  slice15/1 -> reinterpret15/1
  reinterpret15/1 -> out15/1
  slice14/1 -> reinterpret14/1
  reinterpret14/1 -> out14/1
  slice13/1 -> reinterpret13/1
  reinterpret13/1 -> out13/1
  slice12/1 -> reinterpret12/1
  reinterpret12/1 -> out12/1
  slice11/1 -> reinterpret11/1
  reinterpret11/1 -> out11/1
  slice10/1 -> reinterpret10/1
  reinterpret10/1 -> out10/1
  slice9/1 -> reinterpret9/1
  reinterpret9/1 -> out9/1
  slice8/1 -> reinterpret8/1
  reinterpret8/1 -> out8/1
  slice7/1 -> reinterpret7/1
  reinterpret7/1 -> out7/1
  slice6/1 -> reinterpret6/1
  reinterpret6/1 -> out6/1
  slice5/1 -> reinterpret5/1
  reinterpret5/1 -> out5/1
  slice4/1 -> reinterpret4/1
  reinterpret4/1 -> out4/1
  slice3/1 -> reinterpret3/1
  reinterpret3/1 -> out3/1
  slice2/1 -> reinterpret2/1
  reinterpret2/1 -> out2/1
  slice1/1 -> reinterpret1/1
  reinterpret1/1 -> lsb_out1/1

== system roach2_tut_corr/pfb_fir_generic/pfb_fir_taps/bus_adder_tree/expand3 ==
  bus_in : Inport
  reinterpret{1..16} (16 alike) : xbsIndex_r4/Reinterpret  force_arith_type=on  arith_type="Signed  (2's comp)"  force_bin_pt=on  bin_pt=24  block_type=reinterpret
  slice1 : xbsIndex_r4/Slice  nbits=26  boolean_output=off  mode=Upper Bit Location + Width  bit1=-390  base1=MSB of Input  bit0=0  base0=LSB of Input  dbl_ovrd=off  block_type=slice
  slice10 : xbsIndex_r4/Slice  nbits=26  boolean_output=off  mode=Upper Bit Location + Width  bit1=-156  base1=MSB of Input  bit0=0  base0=LSB of Input  dbl_ovrd=off  block_type=slice
  slice11 : xbsIndex_r4/Slice  nbits=26  boolean_output=off  mode=Upper Bit Location + Width  bit1=-130  base1=MSB of Input  bit0=0  base0=LSB of Input  dbl_ovrd=off  block_type=slice
  slice12 : xbsIndex_r4/Slice  nbits=26  boolean_output=off  mode=Upper Bit Location + Width  bit1=-104  base1=MSB of Input  bit0=0  base0=LSB of Input  dbl_ovrd=off  block_type=slice
  slice13 : xbsIndex_r4/Slice  nbits=26  boolean_output=off  mode=Upper Bit Location + Width  bit1=-78  base1=MSB of Input  bit0=0  base0=LSB of Input  dbl_ovrd=off  block_type=slice
  slice14 : xbsIndex_r4/Slice  nbits=26  boolean_output=off  mode=Upper Bit Location + Width  bit1=-52  base1=MSB of Input  bit0=0  base0=LSB of Input  dbl_ovrd=off  block_type=slice
  slice15 : xbsIndex_r4/Slice  nbits=26  boolean_output=off  mode=Upper Bit Location + Width  bit1=-26  base1=MSB of Input  bit0=0  base0=LSB of Input  dbl_ovrd=off  block_type=slice
  slice16 : xbsIndex_r4/Slice  nbits=26  boolean_output=off  mode=Upper Bit Location + Width  bit1=0  base1=MSB of Input  bit0=0  base0=LSB of Input  dbl_ovrd=off  block_type=slice
  slice2 : xbsIndex_r4/Slice  nbits=26  boolean_output=off  mode=Upper Bit Location + Width  bit1=-364  base1=MSB of Input  bit0=0  base0=LSB of Input  dbl_ovrd=off  block_type=slice
  slice3 : xbsIndex_r4/Slice  nbits=26  boolean_output=off  mode=Upper Bit Location + Width  bit1=-338  base1=MSB of Input  bit0=0  base0=LSB of Input  dbl_ovrd=off  block_type=slice
  slice4 : xbsIndex_r4/Slice  nbits=26  boolean_output=off  mode=Upper Bit Location + Width  bit1=-312  base1=MSB of Input  bit0=0  base0=LSB of Input  dbl_ovrd=off  block_type=slice
  slice5 : xbsIndex_r4/Slice  nbits=26  boolean_output=off  mode=Upper Bit Location + Width  bit1=-286  base1=MSB of Input  bit0=0  base0=LSB of Input  dbl_ovrd=off  block_type=slice
  slice6 : xbsIndex_r4/Slice  nbits=26  boolean_output=off  mode=Upper Bit Location + Width  bit1=-260  base1=MSB of Input  bit0=0  base0=LSB of Input  dbl_ovrd=off  block_type=slice
  slice7 : xbsIndex_r4/Slice  nbits=26  boolean_output=off  mode=Upper Bit Location + Width  bit1=-234  base1=MSB of Input  bit0=0  base0=LSB of Input  dbl_ovrd=off  block_type=slice
  slice8 : xbsIndex_r4/Slice  nbits=26  boolean_output=off  mode=Upper Bit Location + Width  bit1=-208  base1=MSB of Input  bit0=0  base0=LSB of Input  dbl_ovrd=off  block_type=slice
  slice9 : xbsIndex_r4/Slice  nbits=26  boolean_output=off  mode=Upper Bit Location + Width  bit1=-182  base1=MSB of Input  bit0=0  base0=LSB of Input  dbl_ovrd=off  block_type=slice
  msb_out16 : Outport
  out15 : Outport  Port=2
  out14 : Outport  Port=3
  out13 : Outport  Port=4
  out12 : Outport  Port=5
  out11 : Outport  Port=6
  out10 : Outport  Port=7
  out9 : Outport  Port=8
  out8 : Outport  Port=9
  out7 : Outport  Port=10
  out6 : Outport  Port=11
  out5 : Outport  Port=12
  out4 : Outport  Port=13
  out3 : Outport  Port=14
  out2 : Outport  Port=15
  lsb_out1 : Outport  Port=16
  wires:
  bus_in/1 -> slice16/1, slice15/1, slice14/1, slice13/1, slice12/1, slice11/1, slice10/1, slice9/1, slice8/1, slice7/1, slice6/1, slice5/1, slice4/1, slice3/1, slice2/1, slice1/1
  slice16/1 -> reinterpret16/1
  reinterpret16/1 -> msb_out16/1
  slice15/1 -> reinterpret15/1
  reinterpret15/1 -> out15/1
  slice14/1 -> reinterpret14/1
  reinterpret14/1 -> out14/1
  slice13/1 -> reinterpret13/1
  reinterpret13/1 -> out13/1
  slice12/1 -> reinterpret12/1
  reinterpret12/1 -> out12/1
  slice11/1 -> reinterpret11/1
  reinterpret11/1 -> out11/1
  slice10/1 -> reinterpret10/1
  reinterpret10/1 -> out10/1
  slice9/1 -> reinterpret9/1
  reinterpret9/1 -> out9/1
  slice8/1 -> reinterpret8/1
  reinterpret8/1 -> out8/1
  slice7/1 -> reinterpret7/1
  reinterpret7/1 -> out7/1
  slice6/1 -> reinterpret6/1
  reinterpret6/1 -> out6/1
  slice5/1 -> reinterpret5/1
  reinterpret5/1 -> out5/1
  slice4/1 -> reinterpret4/1
  reinterpret4/1 -> out4/1
  slice3/1 -> reinterpret3/1
  reinterpret3/1 -> out3/1
  slice2/1 -> reinterpret2/1
  reinterpret2/1 -> out2/1
  slice1/1 -> reinterpret1/1
  reinterpret1/1 -> lsb_out1/1

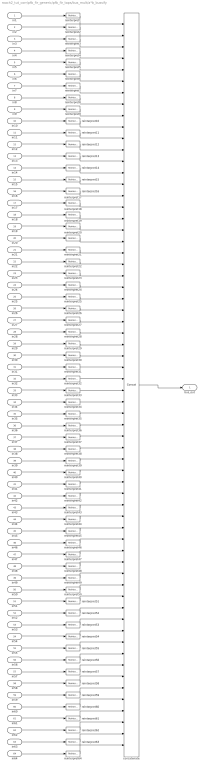
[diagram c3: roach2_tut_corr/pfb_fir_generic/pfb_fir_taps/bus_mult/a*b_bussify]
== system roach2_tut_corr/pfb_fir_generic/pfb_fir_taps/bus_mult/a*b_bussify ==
  in1 : Inport
  in2 : Inport  Port=2
  in3 : Inport  Port=3
  in4 : Inport  Port=4
  in5 : Inport  Port=5
  in6 : Inport  Port=6
  in7 : Inport  Port=7
  in8 : Inport  Port=8
  in9 : Inport  Port=9
  in10 : Inport  Port=10
  in11 : Inport  Port=11
  in12 : Inport  Port=12
  in13 : Inport  Port=13
  in14 : Inport  Port=14
  in15 : Inport  Port=15
  in16 : Inport  Port=16
  in17 : Inport  Port=17
  in18 : Inport  Port=18
  in19 : Inport  Port=19
  in20 : Inport  Port=20
  in21 : Inport  Port=21
  in22 : Inport  Port=22
  in23 : Inport  Port=23
  in24 : Inport  Port=24
  in25 : Inport  Port=25
  in26 : Inport  Port=26
  in27 : Inport  Port=27
  in28 : Inport  Port=28
  in29 : Inport  Port=29
  in30 : Inport  Port=30
  in31 : Inport  Port=31
  in32 : Inport  Port=32
  in33 : Inport  Port=33
  in34 : Inport  Port=34
  in35 : Inport  Port=35
  in36 : Inport  Port=36
  in37 : Inport  Port=37
  in38 : Inport  Port=38
  in39 : Inport  Port=39
  in40 : Inport  Port=40
  in41 : Inport  Port=41
  in42 : Inport  Port=42
  in43 : Inport  Port=43
  in44 : Inport  Port=44
  in45 : Inport  Port=45
  in46 : Inport  Port=46
  in47 : Inport  Port=47
  in48 : Inport  Port=48
  in49 : Inport  Port=49
  in50 : Inport  Port=50
  in51 : Inport  Port=51
  in52 : Inport  Port=52
  in53 : Inport  Port=53
  in54 : Inport  Port=54
  in55 : Inport  Port=55
  in56 : Inport  Port=56
  in57 : Inport  Port=57
  in58 : Inport  Port=58
  in59 : Inport  Port=59
  in60 : Inport  Port=60
  in61 : Inport  Port=61
  in62 : Inport  Port=62
  in63 : Inport  Port=63
  in64 : Inport  Port=64
  concatenate : xbsIndex_r4/Concat  num_inputs=64  dbl_ovrd=off  block_type=concat
  reinterpret{1..64} (64 alike) : xbsIndex_r4/Reinterpret  force_arith_type=on  arith_type=Unsigned  force_bin_pt=on  bin_pt=0  block_type=reinterpret
  bus_out : Outport
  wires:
  concatenate/1 -> bus_out/1
  in1/1 -> reinterpret1/1
  reinterpret1/1 -> concatenate/1
  in2/1 -> reinterpret2/1
  reinterpret2/1 -> concatenate/2
  in3/1 -> reinterpret3/1
  reinterpret3/1 -> concatenate/3
  in4/1 -> reinterpret4/1
  reinterpret4/1 -> concatenate/4
  in5/1 -> reinterpret5/1
  reinterpret5/1 -> concatenate/5
  in6/1 -> reinterpret6/1
  reinterpret6/1 -> concatenate/6
  in7/1 -> reinterpret7/1
  reinterpret7/1 -> concatenate/7
  in8/1 -> reinterpret8/1
  reinterpret8/1 -> concatenate/8
  in9/1 -> reinterpret9/1
  reinterpret9/1 -> concatenate/9
  in10/1 -> reinterpret10/1
  reinterpret10/1 -> concatenate/10
  in11/1 -> reinterpret11/1
  reinterpret11/1 -> concatenate/11
  in12/1 -> reinterpret12/1
  reinterpret12/1 -> concatenate/12
  in13/1 -> reinterpret13/1
  reinterpret13/1 -> concatenate/13
  in14/1 -> reinterpret14/1
  reinterpret14/1 -> concatenate/14
  in15/1 -> reinterpret15/1
  reinterpret15/1 -> concatenate/15
  in16/1 -> reinterpret16/1
  reinterpret16/1 -> concatenate/16
  in17/1 -> reinterpret17/1
  reinterpret17/1 -> concatenate/17
  in18/1 -> reinterpret18/1
  reinterpret18/1 -> concatenate/18
  in19/1 -> reinterpret19/1
  reinterpret19/1 -> concatenate/19
  in20/1 -> reinterpret20/1
  reinterpret20/1 -> concatenate/20
  in21/1 -> reinterpret21/1
  reinterpret21/1 -> concatenate/21
  in22/1 -> reinterpret22/1
  reinterpret22/1 -> concatenate/22
  in23/1 -> reinterpret23/1
  reinterpret23/1 -> concatenate/23
  in24/1 -> reinterpret24/1
  reinterpret24/1 -> concatenate/24
  in25/1 -> reinterpret25/1
  reinterpret25/1 -> concatenate/25
  in26/1 -> reinterpret26/1
  reinterpret26/1 -> concatenate/26
  in27/1 -> reinterpret27/1
  reinterpret27/1 -> concatenate/27
  in28/1 -> reinterpret28/1
  reinterpret28/1 -> concatenate/28
  in29/1 -> reinterpret29/1
  reinterpret29/1 -> concatenate/29
  in30/1 -> reinterpret30/1
  reinterpret30/1 -> concatenate/30
  in31/1 -> reinterpret31/1
  reinterpret31/1 -> concatenate/31
  in32/1 -> reinterpret32/1
  reinterpret32/1 -> concatenate/32
  in33/1 -> reinterpret33/1
  reinterpret33/1 -> concatenate/33
  in34/1 -> reinterpret34/1
  reinterpret34/1 -> concatenate/34
  in35/1 -> reinterpret35/1
  reinterpret35/1 -> concatenate/35
  in36/1 -> reinterpret36/1
  reinterpret36/1 -> concatenate/36
  in37/1 -> reinterpret37/1
  reinterpret37/1 -> concatenate/37
  in38/1 -> reinterpret38/1
  reinterpret38/1 -> concatenate/38
  in39/1 -> reinterpret39/1
  reinterpret39/1 -> concatenate/39
  in40/1 -> reinterpret40/1
  reinterpret40/1 -> concatenate/40
  in41/1 -> reinterpret41/1
  reinterpret41/1 -> concatenate/41
  in42/1 -> reinterpret42/1
  reinterpret42/1 -> concatenate/42
  in43/1 -> reinterpret43/1
  reinterpret43/1 -> concatenate/43
  in44/1 -> reinterpret44/1
  reinterpret44/1 -> concatenate/44
  in45/1 -> reinterpret45/1
  reinterpret45/1 -> concatenate/45
  in46/1 -> reinterpret46/1
  reinterpret46/1 -> concatenate/46
  in47/1 -> reinterpret47/1
  reinterpret47/1 -> concatenate/47
  in48/1 -> reinterpret48/1
  reinterpret48/1 -> concatenate/48
  in49/1 -> reinterpret49/1
  reinterpret49/1 -> concatenate/49
  in50/1 -> reinterpret50/1
  reinterpret50/1 -> concatenate/50
  in51/1 -> reinterpret51/1
  reinterpret51/1 -> concatenate/51
  in52/1 -> reinterpret52/1
  reinterpret52/1 -> concatenate/52
  in53/1 -> reinterpret53/1
  reinterpret53/1 -> concatenate/53
  in54/1 -> reinterpret54/1
  reinterpret54/1 -> concatenate/54
  in55/1 -> reinterpret55/1
  reinterpret55/1 -> concatenate/55
  in56/1 -> reinterpret56/1
  reinterpret56/1 -> concatenate/56
  in57/1 -> reinterpret57/1
  reinterpret57/1 -> concatenate/57
  in58/1 -> reinterpret58/1
  reinterpret58/1 -> concatenate/58
  in59/1 -> reinterpret59/1
  reinterpret59/1 -> concatenate/59
  in60/1 -> reinterpret60/1
  reinterpret60/1 -> concatenate/60
  in61/1 -> reinterpret61/1
  reinterpret61/1 -> concatenate/61
  in62/1 -> reinterpret62/1
  reinterpret62/1 -> concatenate/62
  in63/1 -> reinterpret63/1
  reinterpret63/1 -> concatenate/63
  in64/1 -> reinterpret64/1
  reinterpret64/1 -> concatenate/64

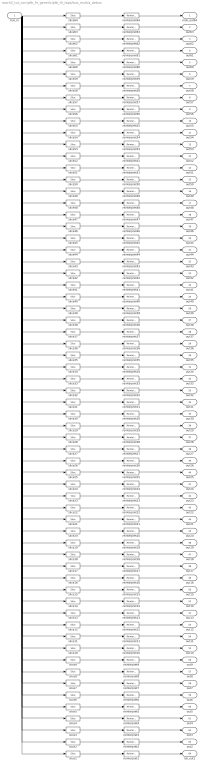
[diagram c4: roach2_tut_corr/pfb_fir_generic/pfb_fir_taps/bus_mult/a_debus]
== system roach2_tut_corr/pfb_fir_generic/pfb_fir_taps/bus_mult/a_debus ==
  bus_in : Inport
  reinterpret{1..64} (64 alike) : xbsIndex_r4/Reinterpret  force_arith_type=on  arith_type="Signed  (2's comp)"  force_bin_pt=on  bin_pt=7  block_type=reinterpret
  slice1 : xbsIndex_r4/Slice  nbits=8  boolean_output=off  mode=Upper Bit Location + Width  bit1=-504  base1=MSB of Input  bit0=0  base0=LSB of Input  dbl_ovrd=off  block_type=slice
  slice10 : xbsIndex_r4/Slice  nbits=8  boolean_output=off  mode=Upper Bit Location + Width  bit1=-432  base1=MSB of Input  bit0=0  base0=LSB of Input  dbl_ovrd=off  block_type=slice
  slice11 : xbsIndex_r4/Slice  nbits=8  boolean_output=off  mode=Upper Bit Location + Width  bit1=-424  base1=MSB of Input  bit0=0  base0=LSB of Input  dbl_ovrd=off  block_type=slice
  slice12 : xbsIndex_r4/Slice  nbits=8  boolean_output=off  mode=Upper Bit Location + Width  bit1=-416  base1=MSB of Input  bit0=0  base0=LSB of Input  dbl_ovrd=off  block_type=slice
  slice13 : xbsIndex_r4/Slice  nbits=8  boolean_output=off  mode=Upper Bit Location + Width  bit1=-408  base1=MSB of Input  bit0=0  base0=LSB of Input  dbl_ovrd=off  block_type=slice
  slice14 : xbsIndex_r4/Slice  nbits=8  boolean_output=off  mode=Upper Bit Location + Width  bit1=-400  base1=MSB of Input  bit0=0  base0=LSB of Input  dbl_ovrd=off  block_type=slice
  slice15 : xbsIndex_r4/Slice  nbits=8  boolean_output=off  mode=Upper Bit Location + Width  bit1=-392  base1=MSB of Input  bit0=0  base0=LSB of Input  dbl_ovrd=off  block_type=slice
  slice16 : xbsIndex_r4/Slice  nbits=8  boolean_output=off  mode=Upper Bit Location + Width  bit1=-384  base1=MSB of Input  bit0=0  base0=LSB of Input  dbl_ovrd=off  block_type=slice
  slice17 : xbsIndex_r4/Slice  nbits=8  boolean_output=off  mode=Upper Bit Location + Width  bit1=-376  base1=MSB of Input  bit0=0  base0=LSB of Input  dbl_ovrd=off  block_type=slice
  slice18 : xbsIndex_r4/Slice  nbits=8  boolean_output=off  mode=Upper Bit Location + Width  bit1=-368  base1=MSB of Input  bit0=0  base0=LSB of Input  dbl_ovrd=off  block_type=slice
  slice19 : xbsIndex_r4/Slice  nbits=8  boolean_output=off  mode=Upper Bit Location + Width  bit1=-360  base1=MSB of Input  bit0=0  base0=LSB of Input  dbl_ovrd=off  block_type=slice
  slice2 : xbsIndex_r4/Slice  nbits=8  boolean_output=off  mode=Upper Bit Location + Width  bit1=-496  base1=MSB of Input  bit0=0  base0=LSB of Input  dbl_ovrd=off  block_type=slice
  slice20 : xbsIndex_r4/Slice  nbits=8  boolean_output=off  mode=Upper Bit Location + Width  bit1=-352  base1=MSB of Input  bit0=0  base0=LSB of Input  dbl_ovrd=off  block_type=slice
  slice21 : xbsIndex_r4/Slice  nbits=8  boolean_output=off  mode=Upper Bit Location + Width  bit1=-344  base1=MSB of Input  bit0=0  base0=LSB of Input  dbl_ovrd=off  block_type=slice
  slice22 : xbsIndex_r4/Slice  nbits=8  boolean_output=off  mode=Upper Bit Location + Width  bit1=-336  base1=MSB of Input  bit0=0  base0=LSB of Input  dbl_ovrd=off  block_type=slice
  slice23 : xbsIndex_r4/Slice  nbits=8  boolean_output=off  mode=Upper Bit Location + Width  bit1=-328  base1=MSB of Input  bit0=0  base0=LSB of Input  dbl_ovrd=off  block_type=slice
  slice24 : xbsIndex_r4/Slice  nbits=8  boolean_output=off  mode=Upper Bit Location + Width  bit1=-320  base1=MSB of Input  bit0=0  base0=LSB of Input  dbl_ovrd=off  block_type=slice
  slice25 : xbsIndex_r4/Slice  nbits=8  boolean_output=off  mode=Upper Bit Location + Width  bit1=-312  base1=MSB of Input  bit0=0  base0=LSB of Input  dbl_ovrd=off  block_type=slice
  slice26 : xbsIndex_r4/Slice  nbits=8  boolean_output=off  mode=Upper Bit Location + Width  bit1=-304  base1=MSB of Input  bit0=0  base0=LSB of Input  dbl_ovrd=off  block_type=slice
  slice27 : xbsIndex_r4/Slice  nbits=8  boolean_output=off  mode=Upper Bit Location + Width  bit1=-296  base1=MSB of Input  bit0=0  base0=LSB of Input  dbl_ovrd=off  block_type=slice
  slice28 : xbsIndex_r4/Slice  nbits=8  boolean_output=off  mode=Upper Bit Location + Width  bit1=-288  base1=MSB of Input  bit0=0  base0=LSB of Input  dbl_ovrd=off  block_type=slice
  slice29 : xbsIndex_r4/Slice  nbits=8  boolean_output=off  mode=Upper Bit Location + Width  bit1=-280  base1=MSB of Input  bit0=0  base0=LSB of Input  dbl_ovrd=off  block_type=slice
  slice3 : xbsIndex_r4/Slice  nbits=8  boolean_output=off  mode=Upper Bit Location + Width  bit1=-488  base1=MSB of Input  bit0=0  base0=LSB of Input  dbl_ovrd=off  block_type=slice
  slice30 : xbsIndex_r4/Slice  nbits=8  boolean_output=off  mode=Upper Bit Location + Width  bit1=-272  base1=MSB of Input  bit0=0  base0=LSB of Input  dbl_ovrd=off  block_type=slice
  slice31 : xbsIndex_r4/Slice  nbits=8  boolean_output=off  mode=Upper Bit Location + Width  bit1=-264  base1=MSB of Input  bit0=0  base0=LSB of Input  dbl_ovrd=off  block_type=slice
  slice32 : xbsIndex_r4/Slice  nbits=8  boolean_output=off  mode=Upper Bit Location + Width  bit1=-256  base1=MSB of Input  bit0=0  base0=LSB of Input  dbl_ovrd=off  block_type=slice
  slice33 : xbsIndex_r4/Slice  nbits=8  boolean_output=off  mode=Upper Bit Location + Width  bit1=-248  base1=MSB of Input  bit0=0  base0=LSB of Input  dbl_ovrd=off  block_type=slice
  slice34 : xbsIndex_r4/Slice  nbits=8  boolean_output=off  mode=Upper Bit Location + Width  bit1=-240  base1=MSB of Input  bit0=0  base0=LSB of Input  dbl_ovrd=off  block_type=slice
  slice35 : xbsIndex_r4/Slice  nbits=8  boolean_output=off  mode=Upper Bit Location + Width  bit1=-232  base1=MSB of Input  bit0=0  base0=LSB of Input  dbl_ovrd=off  block_type=slice
  slice36 : xbsIndex_r4/Slice  nbits=8  boolean_output=off  mode=Upper Bit Location + Width  bit1=-224  base1=MSB of Input  bit0=0  base0=LSB of Input  dbl_ovrd=off  block_type=slice
  slice37 : xbsIndex_r4/Slice  nbits=8  boolean_output=off  mode=Upper Bit Location + Width  bit1=-216  base1=MSB of Input  bit0=0  base0=LSB of Input  dbl_ovrd=off  block_type=slice
  slice38 : xbsIndex_r4/Slice  nbits=8  boolean_output=off  mode=Upper Bit Location + Width  bit1=-208  base1=MSB of Input  bit0=0  base0=LSB of Input  dbl_ovrd=off  block_type=slice
  slice39 : xbsIndex_r4/Slice  nbits=8  boolean_output=off  mode=Upper Bit Location + Width  bit1=-200  base1=MSB of Input  bit0=0  base0=LSB of Input  dbl_ovrd=off  block_type=slice
  slice4 : xbsIndex_r4/Slice  nbits=8  boolean_output=off  mode=Upper Bit Location + Width  bit1=-480  base1=MSB of Input  bit0=0  base0=LSB of Input  dbl_ovrd=off  block_type=slice
  slice40 : xbsIndex_r4/Slice  nbits=8  boolean_output=off  mode=Upper Bit Location + Width  bit1=-192  base1=MSB of Input  bit0=0  base0=LSB of Input  dbl_ovrd=off  block_type=slice
  slice41 : xbsIndex_r4/Slice  nbits=8  boolean_output=off  mode=Upper Bit Location + Width  bit1=-184  base1=MSB of Input  bit0=0  base0=LSB of Input  dbl_ovrd=off  block_type=slice
  slice42 : xbsIndex_r4/Slice  nbits=8  boolean_output=off  mode=Upper Bit Location + Width  bit1=-176  base1=MSB of Input  bit0=0  base0=LSB of Input  dbl_ovrd=off  block_type=slice
  slice43 : xbsIndex_r4/Slice  nbits=8  boolean_output=off  mode=Upper Bit Location + Width  bit1=-168  base1=MSB of Input  bit0=0  base0=LSB of Input  dbl_ovrd=off  block_type=slice
  slice44 : xbsIndex_r4/Slice  nbits=8  boolean_output=off  mode=Upper Bit Location + Width  bit1=-160  base1=MSB of Input  bit0=0  base0=LSB of Input  dbl_ovrd=off  block_type=slice
  slice45 : xbsIndex_r4/Slice  nbits=8  boolean_output=off  mode=Upper Bit Location + Width  bit1=-152  base1=MSB of Input  bit0=0  base0=LSB of Input  dbl_ovrd=off  block_type=slice
  slice46 : xbsIndex_r4/Slice  nbits=8  boolean_output=off  mode=Upper Bit Location + Width  bit1=-144  base1=MSB of Input  bit0=0  base0=LSB of Input  dbl_ovrd=off  block_type=slice
  slice47 : xbsIndex_r4/Slice  nbits=8  boolean_output=off  mode=Upper Bit Location + Width  bit1=-136  base1=MSB of Input  bit0=0  base0=LSB of Input  dbl_ovrd=off  block_type=slice
  slice48 : xbsIndex_r4/Slice  nbits=8  boolean_output=off  mode=Upper Bit Location + Width  bit1=-128  base1=MSB of Input  bit0=0  base0=LSB of Input  dbl_ovrd=off  block_type=slice
  slice49 : xbsIndex_r4/Slice  nbits=8  boolean_output=off  mode=Upper Bit Location + Width  bit1=-120  base1=MSB of Input  bit0=0  base0=LSB of Input  dbl_ovrd=off  block_type=slice
  slice5 : xbsIndex_r4/Slice  nbits=8  boolean_output=off  mode=Upper Bit Location + Width  bit1=-472  base1=MSB of Input  bit0=0  base0=LSB of Input  dbl_ovrd=off  block_type=slice
  slice50 : xbsIndex_r4/Slice  nbits=8  boolean_output=off  mode=Upper Bit Location + Width  bit1=-112  base1=MSB of Input  bit0=0  base0=LSB of Input  dbl_ovrd=off  block_type=slice
  slice51 : xbsIndex_r4/Slice  nbits=8  boolean_output=off  mode=Upper Bit Location + Width  bit1=-104  base1=MSB of Input  bit0=0  base0=LSB of Input  dbl_ovrd=off  block_type=slice
  slice52 : xbsIndex_r4/Slice  nbits=8  boolean_output=off  mode=Upper Bit Location + Width  bit1=-96  base1=MSB of Input  bit0=0  base0=LSB of Input  dbl_ovrd=off  block_type=slice
  slice53 : xbsIndex_r4/Slice  nbits=8  boolean_output=off  mode=Upper Bit Location + Width  bit1=-88  base1=MSB of Input  bit0=0  base0=LSB of Input  dbl_ovrd=off  block_type=slice
  slice54 : xbsIndex_r4/Slice  nbits=8  boolean_output=off  mode=Upper Bit Location + Width  bit1=-80  base1=MSB of Input  bit0=0  base0=LSB of Input  dbl_ovrd=off  block_type=slice
  slice55 : xbsIndex_r4/Slice  nbits=8  boolean_output=off  mode=Upper Bit Location + Width  bit1=-72  base1=MSB of Input  bit0=0  base0=LSB of Input  dbl_ovrd=off  block_type=slice
  slice56 : xbsIndex_r4/Slice  nbits=8  boolean_output=off  mode=Upper Bit Location + Width  bit1=-64  base1=MSB of Input  bit0=0  base0=LSB of Input  dbl_ovrd=off  block_type=slice
  slice57 : xbsIndex_r4/Slice  nbits=8  boolean_output=off  mode=Upper Bit Location + Width  bit1=-56  base1=MSB of Input  bit0=0  base0=LSB of Input  dbl_ovrd=off  block_type=slice
  slice58 : xbsIndex_r4/Slice  nbits=8  boolean_output=off  mode=Upper Bit Location + Width  bit1=-48  base1=MSB of Input  bit0=0  base0=LSB of Input  dbl_ovrd=off  block_type=slice
  slice59 : xbsIndex_r4/Slice  nbits=8  boolean_output=off  mode=Upper Bit Location + Width  bit1=-40  base1=MSB of Input  bit0=0  base0=LSB of Input  dbl_ovrd=off  block_type=slice
  slice6 : xbsIndex_r4/Slice  nbits=8  boolean_output=off  mode=Upper Bit Location + Width  bit1=-464  base1=MSB of Input  bit0=0  base0=LSB of Input  dbl_ovrd=off  block_type=slice
  slice60 : xbsIndex_r4/Slice  nbits=8  boolean_output=off  mode=Upper Bit Location + Width  bit1=-32  base1=MSB of Input  bit0=0  base0=LSB of Input  dbl_ovrd=off  block_type=slice
  slice61 : xbsIndex_r4/Slice  nbits=8  boolean_output=off  mode=Upper Bit Location + Width  bit1=-24  base1=MSB of Input  bit0=0  base0=LSB of Input  dbl_ovrd=off  block_type=slice
  slice62 : xbsIndex_r4/Slice  nbits=8  boolean_output=off  mode=Upper Bit Location + Width  bit1=-16  base1=MSB of Input  bit0=0  base0=LSB of Input  dbl_ovrd=off  block_type=slice
  slice63 : xbsIndex_r4/Slice  nbits=8  boolean_output=off  mode=Upper Bit Location + Width  bit1=-8  base1=MSB of Input  bit0=0  base0=LSB of Input  dbl_ovrd=off  block_type=slice
  slice64 : xbsIndex_r4/Slice  nbits=8  boolean_output=off  mode=Upper Bit Location + Width  bit1=0  base1=MSB of Input  bit0=0  base0=LSB of Input  dbl_ovrd=off  block_type=slice
  slice7 : xbsIndex_r4/Slice  nbits=8  boolean_output=off  mode=Upper Bit Location + Width  bit1=-456  base1=MSB of Input  bit0=0  base0=LSB of Input  dbl_ovrd=off  block_type=slice
  slice8 : xbsIndex_r4/Slice  nbits=8  boolean_output=off  mode=Upper Bit Location + Width  bit1=-448  base1=MSB of Input  bit0=0  base0=LSB of Input  dbl_ovrd=off  block_type=slice
  slice9 : xbsIndex_r4/Slice  nbits=8  boolean_output=off  mode=Upper Bit Location + Width  bit1=-440  base1=MSB of Input  bit0=0  base0=LSB of Input  dbl_ovrd=off  block_type=slice
  msb_out64 : Outport
  out63 : Outport  Port=2
  out62 : Outport  Port=3
  out61 : Outport  Port=4
  out60 : Outport  Port=5
  out59 : Outport  Port=6
  out58 : Outport  Port=7
  out57 : Outport  Port=8
  out56 : Outport  Port=9
  out55 : Outport  Port=10
  out54 : Outport  Port=11
  out53 : Outport  Port=12
  out52 : Outport  Port=13
  out51 : Outport  Port=14
  out50 : Outport  Port=15
  out49 : Outport  Port=16
  out48 : Outport  Port=17
  out47 : Outport  Port=18
  out46 : Outport  Port=19
  out45 : Outport  Port=20
  out44 : Outport  Port=21
  out43 : Outport  Port=22
  out42 : Outport  Port=23
  out41 : Outport  Port=24
  out40 : Outport  Port=25
  out39 : Outport  Port=26
  out38 : Outport  Port=27
  out37 : Outport  Port=28
  out36 : Outport  Port=29
  out35 : Outport  Port=30
  out34 : Outport  Port=31
  out33 : Outport  Port=32
  out32 : Outport  Port=33
  out31 : Outport  Port=34
  out30 : Outport  Port=35
  out29 : Outport  Port=36
  out28 : Outport  Port=37
  out27 : Outport  Port=38
  out26 : Outport  Port=39
  out25 : Outport  Port=40
  out24 : Outport  Port=41
  out23 : Outport  Port=42
  out22 : Outport  Port=43
  out21 : Outport  Port=44
  out20 : Outport  Port=45
  out19 : Outport  Port=46
  out18 : Outport  Port=47
  out17 : Outport  Port=48
  out16 : Outport  Port=49
  out15 : Outport  Port=50
  out14 : Outport  Port=51
  out13 : Outport  Port=52
  out12 : Outport  Port=53
  out11 : Outport  Port=54
  out10 : Outport  Port=55
  out9 : Outport  Port=56
  out8 : Outport  Port=57
  out7 : Outport  Port=58
  out6 : Outport  Port=59
  out5 : Outport  Port=60
  out4 : Outport  Port=61
  out3 : Outport  Port=62
  out2 : Outport  Port=63
  lsb_out1 : Outport  Port=64
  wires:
  bus_in/1 -> slice64/1, slice63/1, slice62/1, slice61/1, slice60/1, slice59/1, slice58/1, slice57/1, slice56/1, slice55/1, slice54/1, slice53/1, slice52/1, slice51/1, slice50/1, slice49/1, slice48/1, slice47/1, slice46/1, slice45/1, slice44/1, slice43/1, slice42/1, slice41/1, slice40/1, slice39/1, slice38/1, slice37/1, slice36/1, slice35/1, slice34/1, slice33/1, slice32/1, slice31/1, slice30/1, slice29/1, slice28/1, slice27/1, slice26/1, slice25/1, slice24/1, slice23/1, slice22/1, slice21/1, slice20/1, slice19/1, slice18/1, slice17/1, slice16/1, slice15/1, slice14/1, slice13/1, slice12/1, slice11/1, slice10/1, slice9/1, slice8/1, slice7/1, slice6/1, slice5/1, slice4/1, slice3/1, slice2/1, slice1/1
  slice64/1 -> reinterpret64/1
  reinterpret64/1 -> msb_out64/1
  slice63/1 -> reinterpret63/1
  reinterpret63/1 -> out63/1
  slice62/1 -> reinterpret62/1
  reinterpret62/1 -> out62/1
  slice61/1 -> reinterpret61/1
  reinterpret61/1 -> out61/1
  slice60/1 -> reinterpret60/1
  reinterpret60/1 -> out60/1
  slice59/1 -> reinterpret59/1
  reinterpret59/1 -> out59/1
  slice58/1 -> reinterpret58/1
  reinterpret58/1 -> out58/1
  slice57/1 -> reinterpret57/1
  reinterpret57/1 -> out57/1
  slice56/1 -> reinterpret56/1
  reinterpret56/1 -> out56/1
  slice55/1 -> reinterpret55/1
  reinterpret55/1 -> out55/1
  slice54/1 -> reinterpret54/1
  reinterpret54/1 -> out54/1
  slice53/1 -> reinterpret53/1
  reinterpret53/1 -> out53/1
  slice52/1 -> reinterpret52/1
  reinterpret52/1 -> out52/1
  slice51/1 -> reinterpret51/1
  reinterpret51/1 -> out51/1
  slice50/1 -> reinterpret50/1
  reinterpret50/1 -> out50/1
  slice49/1 -> reinterpret49/1
  reinterpret49/1 -> out49/1
  slice48/1 -> reinterpret48/1
  reinterpret48/1 -> out48/1
  slice47/1 -> reinterpret47/1
  reinterpret47/1 -> out47/1
  slice46/1 -> reinterpret46/1
  reinterpret46/1 -> out46/1
  slice45/1 -> reinterpret45/1
  reinterpret45/1 -> out45/1
  slice44/1 -> reinterpret44/1
  reinterpret44/1 -> out44/1
  slice43/1 -> reinterpret43/1
  reinterpret43/1 -> out43/1
  slice42/1 -> reinterpret42/1
  reinterpret42/1 -> out42/1
  slice41/1 -> reinterpret41/1
  reinterpret41/1 -> out41/1
  slice40/1 -> reinterpret40/1
  reinterpret40/1 -> out40/1
  slice39/1 -> reinterpret39/1
  reinterpret39/1 -> out39/1
  slice38/1 -> reinterpret38/1
  reinterpret38/1 -> out38/1
  slice37/1 -> reinterpret37/1
  reinterpret37/1 -> out37/1
  slice36/1 -> reinterpret36/1
  reinterpret36/1 -> out36/1
  slice35/1 -> reinterpret35/1
  reinterpret35/1 -> out35/1
  slice34/1 -> reinterpret34/1
  reinterpret34/1 -> out34/1
  slice33/1 -> reinterpret33/1
  reinterpret33/1 -> out33/1
  slice32/1 -> reinterpret32/1
  reinterpret32/1 -> out32/1
  slice31/1 -> reinterpret31/1
  reinterpret31/1 -> out31/1
  slice30/1 -> reinterpret30/1
  reinterpret30/1 -> out30/1
  slice29/1 -> reinterpret29/1
  reinterpret29/1 -> out29/1
  slice28/1 -> reinterpret28/1
  reinterpret28/1 -> out28/1
  slice27/1 -> reinterpret27/1
  reinterpret27/1 -> out27/1
  slice26/1 -> reinterpret26/1
  reinterpret26/1 -> out26/1
  slice25/1 -> reinterpret25/1
  reinterpret25/1 -> out25/1
  slice24/1 -> reinterpret24/1
  reinterpret24/1 -> out24/1
  slice23/1 -> reinterpret23/1
  reinterpret23/1 -> out23/1
  slice22/1 -> reinterpret22/1
  reinterpret22/1 -> out22/1
  slice21/1 -> reinterpret21/1
  reinterpret21/1 -> out21/1
  slice20/1 -> reinterpret20/1
  reinterpret20/1 -> out20/1
  slice19/1 -> reinterpret19/1
  reinterpret19/1 -> out19/1
  slice18/1 -> reinterpret18/1
  reinterpret18/1 -> out18/1
  slice17/1 -> reinterpret17/1
  reinterpret17/1 -> out17/1
  slice16/1 -> reinterpret16/1
  reinterpret16/1 -> out16/1
  slice15/1 -> reinterpret15/1
  reinterpret15/1 -> out15/1
  slice14/1 -> reinterpret14/1
  reinterpret14/1 -> out14/1
  slice13/1 -> reinterpret13/1
  reinterpret13/1 -> out13/1
  slice12/1 -> reinterpret12/1
  reinterpret12/1 -> out12/1
  slice11/1 -> reinterpret11/1
  reinterpret11/1 -> out11/1
  slice10/1 -> reinterpret10/1
  reinterpret10/1 -> out10/1
  slice9/1 -> reinterpret9/1
  reinterpret9/1 -> out9/1
  slice8/1 -> reinterpret8/1
  reinterpret8/1 -> out8/1
  slice7/1 -> reinterpret7/1
  reinterpret7/1 -> out7/1
  slice6/1 -> reinterpret6/1
  reinterpret6/1 -> out6/1
  slice5/1 -> reinterpret5/1
  reinterpret5/1 -> out5/1
  slice4/1 -> reinterpret4/1
  reinterpret4/1 -> out4/1
  slice3/1 -> reinterpret3/1
  reinterpret3/1 -> out3/1
  slice2/1 -> reinterpret2/1
  reinterpret2/1 -> out2/1
  slice1/1 -> reinterpret1/1
  reinterpret1/1 -> lsb_out1/1
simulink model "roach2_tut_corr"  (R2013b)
settings: Solver=VariableStepDiscrete  SolverMode=SingleTasking  StartTime=0.0  StopTime=100  RelTol=1e-3
undefined symbols (not defined in the file): add_latency, addr_width, Bit, bitfield, BitWidth, bram_latency, burst_size, casper_library_scopes, conv_latency, data_width, DelayLen, fan_latency, FFTSize, FFTStage, getfield, increment, led, Location, Lower, mult_latency, mux_latency, n_bits, n_bits_data, n_inputs, n_streams, n_taps, neg_latency, negate_latency, nsamples, pfb_size, pulse_len, reset_period, ROACH, ROACH2, snapshot, sx475t, sync_period, sync_period_bits, Upper, UseCounter, Width
libraries: xbsIndex_r4 x24444, casper_library_misc x73, xbsReplacements_r4 x34, casper_library_delays x14, xps_library x7
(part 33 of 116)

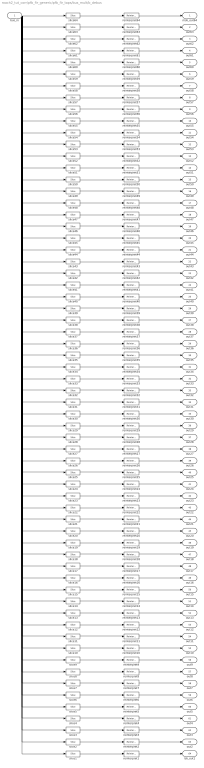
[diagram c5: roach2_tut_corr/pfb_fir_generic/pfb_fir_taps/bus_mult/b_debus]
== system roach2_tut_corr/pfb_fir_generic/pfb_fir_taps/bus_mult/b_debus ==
  bus_in : Inport
  reinterpret{1..64} (64 alike) : xbsIndex_r4/Reinterpret  force_arith_type=on  arith_type="Signed  (2's comp)"  force_bin_pt=on  bin_pt=17  block_type=reinterpret
  slice1 : xbsIndex_r4/Slice  nbits=18  boolean_output=off  mode=Upper Bit Location + Width  bit1=-1134  base1=MSB of Input  bit0=0  base0=LSB of Input  dbl_ovrd=off  block_type=slice
  slice10 : xbsIndex_r4/Slice  nbits=18  boolean_output=off  mode=Upper Bit Location + Width  bit1=-972  base1=MSB of Input  bit0=0  base0=LSB of Input  dbl_ovrd=off  block_type=slice
  slice11 : xbsIndex_r4/Slice  nbits=18  boolean_output=off  mode=Upper Bit Location + Width  bit1=-954  base1=MSB of Input  bit0=0  base0=LSB of Input  dbl_ovrd=off  block_type=slice
  slice12 : xbsIndex_r4/Slice  nbits=18  boolean_output=off  mode=Upper Bit Location + Width  bit1=-936  base1=MSB of Input  bit0=0  base0=LSB of Input  dbl_ovrd=off  block_type=slice
  slice13 : xbsIndex_r4/Slice  nbits=18  boolean_output=off  mode=Upper Bit Location + Width  bit1=-918  base1=MSB of Input  bit0=0  base0=LSB of Input  dbl_ovrd=off  block_type=slice
  slice14 : xbsIndex_r4/Slice  nbits=18  boolean_output=off  mode=Upper Bit Location + Width  bit1=-900  base1=MSB of Input  bit0=0  base0=LSB of Input  dbl_ovrd=off  block_type=slice
  slice15 : xbsIndex_r4/Slice  nbits=18  boolean_output=off  mode=Upper Bit Location + Width  bit1=-882  base1=MSB of Input  bit0=0  base0=LSB of Input  dbl_ovrd=off  block_type=slice
  slice16 : xbsIndex_r4/Slice  nbits=18  boolean_output=off  mode=Upper Bit Location + Width  bit1=-864  base1=MSB of Input  bit0=0  base0=LSB of Input  dbl_ovrd=off  block_type=slice
  slice17 : xbsIndex_r4/Slice  nbits=18  boolean_output=off  mode=Upper Bit Location + Width  bit1=-846  base1=MSB of Input  bit0=0  base0=LSB of Input  dbl_ovrd=off  block_type=slice
  slice18 : xbsIndex_r4/Slice  nbits=18  boolean_output=off  mode=Upper Bit Location + Width  bit1=-828  base1=MSB of Input  bit0=0  base0=LSB of Input  dbl_ovrd=off  block_type=slice
  slice19 : xbsIndex_r4/Slice  nbits=18  boolean_output=off  mode=Upper Bit Location + Width  bit1=-810  base1=MSB of Input  bit0=0  base0=LSB of Input  dbl_ovrd=off  block_type=slice
  slice2 : xbsIndex_r4/Slice  nbits=18  boolean_output=off  mode=Upper Bit Location + Width  bit1=-1116  base1=MSB of Input  bit0=0  base0=LSB of Input  dbl_ovrd=off  block_type=slice
  slice20 : xbsIndex_r4/Slice  nbits=18  boolean_output=off  mode=Upper Bit Location + Width  bit1=-792  base1=MSB of Input  bit0=0  base0=LSB of Input  dbl_ovrd=off  block_type=slice
  slice21 : xbsIndex_r4/Slice  nbits=18  boolean_output=off  mode=Upper Bit Location + Width  bit1=-774  base1=MSB of Input  bit0=0  base0=LSB of Input  dbl_ovrd=off  block_type=slice
  slice22 : xbsIndex_r4/Slice  nbits=18  boolean_output=off  mode=Upper Bit Location + Width  bit1=-756  base1=MSB of Input  bit0=0  base0=LSB of Input  dbl_ovrd=off  block_type=slice
  slice23 : xbsIndex_r4/Slice  nbits=18  boolean_output=off  mode=Upper Bit Location + Width  bit1=-738  base1=MSB of Input  bit0=0  base0=LSB of Input  dbl_ovrd=off  block_type=slice
  slice24 : xbsIndex_r4/Slice  nbits=18  boolean_output=off  mode=Upper Bit Location + Width  bit1=-720  base1=MSB of Input  bit0=0  base0=LSB of Input  dbl_ovrd=off  block_type=slice
  slice25 : xbsIndex_r4/Slice  nbits=18  boolean_output=off  mode=Upper Bit Location + Width  bit1=-702  base1=MSB of Input  bit0=0  base0=LSB of Input  dbl_ovrd=off  block_type=slice
  slice26 : xbsIndex_r4/Slice  nbits=18  boolean_output=off  mode=Upper Bit Location + Width  bit1=-684  base1=MSB of Input  bit0=0  base0=LSB of Input  dbl_ovrd=off  block_type=slice
  slice27 : xbsIndex_r4/Slice  nbits=18  boolean_output=off  mode=Upper Bit Location + Width  bit1=-666  base1=MSB of Input  bit0=0  base0=LSB of Input  dbl_ovrd=off  block_type=slice
  slice28 : xbsIndex_r4/Slice  nbits=18  boolean_output=off  mode=Upper Bit Location + Width  bit1=-648  base1=MSB of Input  bit0=0  base0=LSB of Input  dbl_ovrd=off  block_type=slice
  slice29 : xbsIndex_r4/Slice  nbits=18  boolean_output=off  mode=Upper Bit Location + Width  bit1=-630  base1=MSB of Input  bit0=0  base0=LSB of Input  dbl_ovrd=off  block_type=slice
  slice3 : xbsIndex_r4/Slice  nbits=18  boolean_output=off  mode=Upper Bit Location + Width  bit1=-1098  base1=MSB of Input  bit0=0  base0=LSB of Input  dbl_ovrd=off  block_type=slice
  slice30 : xbsIndex_r4/Slice  nbits=18  boolean_output=off  mode=Upper Bit Location + Width  bit1=-612  base1=MSB of Input  bit0=0  base0=LSB of Input  dbl_ovrd=off  block_type=slice
  slice31 : xbsIndex_r4/Slice  nbits=18  boolean_output=off  mode=Upper Bit Location + Width  bit1=-594  base1=MSB of Input  bit0=0  base0=LSB of Input  dbl_ovrd=off  block_type=slice
  slice32 : xbsIndex_r4/Slice  nbits=18  boolean_output=off  mode=Upper Bit Location + Width  bit1=-576  base1=MSB of Input  bit0=0  base0=LSB of Input  dbl_ovrd=off  block_type=slice
  slice33 : xbsIndex_r4/Slice  nbits=18  boolean_output=off  mode=Upper Bit Location + Width  bit1=-558  base1=MSB of Input  bit0=0  base0=LSB of Input  dbl_ovrd=off  block_type=slice
  slice34 : xbsIndex_r4/Slice  nbits=18  boolean_output=off  mode=Upper Bit Location + Width  bit1=-540  base1=MSB of Input  bit0=0  base0=LSB of Input  dbl_ovrd=off  block_type=slice
  slice35 : xbsIndex_r4/Slice  nbits=18  boolean_output=off  mode=Upper Bit Location + Width  bit1=-522  base1=MSB of Input  bit0=0  base0=LSB of Input  dbl_ovrd=off  block_type=slice
  slice36 : xbsIndex_r4/Slice  nbits=18  boolean_output=off  mode=Upper Bit Location + Width  bit1=-504  base1=MSB of Input  bit0=0  base0=LSB of Input  dbl_ovrd=off  block_type=slice
  slice37 : xbsIndex_r4/Slice  nbits=18  boolean_output=off  mode=Upper Bit Location + Width  bit1=-486  base1=MSB of Input  bit0=0  base0=LSB of Input  dbl_ovrd=off  block_type=slice
  slice38 : xbsIndex_r4/Slice  nbits=18  boolean_output=off  mode=Upper Bit Location + Width  bit1=-468  base1=MSB of Input  bit0=0  base0=LSB of Input  dbl_ovrd=off  block_type=slice
  slice39 : xbsIndex_r4/Slice  nbits=18  boolean_output=off  mode=Upper Bit Location + Width  bit1=-450  base1=MSB of Input  bit0=0  base0=LSB of Input  dbl_ovrd=off  block_type=slice
  slice4 : xbsIndex_r4/Slice  nbits=18  boolean_output=off  mode=Upper Bit Location + Width  bit1=-1080  base1=MSB of Input  bit0=0  base0=LSB of Input  dbl_ovrd=off  block_type=slice
  slice40 : xbsIndex_r4/Slice  nbits=18  boolean_output=off  mode=Upper Bit Location + Width  bit1=-432  base1=MSB of Input  bit0=0  base0=LSB of Input  dbl_ovrd=off  block_type=slice
  slice41 : xbsIndex_r4/Slice  nbits=18  boolean_output=off  mode=Upper Bit Location + Width  bit1=-414  base1=MSB of Input  bit0=0  base0=LSB of Input  dbl_ovrd=off  block_type=slice
  slice42 : xbsIndex_r4/Slice  nbits=18  boolean_output=off  mode=Upper Bit Location + Width  bit1=-396  base1=MSB of Input  bit0=0  base0=LSB of Input  dbl_ovrd=off  block_type=slice
  slice43 : xbsIndex_r4/Slice  nbits=18  boolean_output=off  mode=Upper Bit Location + Width  bit1=-378  base1=MSB of Input  bit0=0  base0=LSB of Input  dbl_ovrd=off  block_type=slice
  slice44 : xbsIndex_r4/Slice  nbits=18  boolean_output=off  mode=Upper Bit Location + Width  bit1=-360  base1=MSB of Input  bit0=0  base0=LSB of Input  dbl_ovrd=off  block_type=slice
  slice45 : xbsIndex_r4/Slice  nbits=18  boolean_output=off  mode=Upper Bit Location + Width  bit1=-342  base1=MSB of Input  bit0=0  base0=LSB of Input  dbl_ovrd=off  block_type=slice
  slice46 : xbsIndex_r4/Slice  nbits=18  boolean_output=off  mode=Upper Bit Location + Width  bit1=-324  base1=MSB of Input  bit0=0  base0=LSB of Input  dbl_ovrd=off  block_type=slice
  slice47 : xbsIndex_r4/Slice  nbits=18  boolean_output=off  mode=Upper Bit Location + Width  bit1=-306  base1=MSB of Input  bit0=0  base0=LSB of Input  dbl_ovrd=off  block_type=slice
  slice48 : xbsIndex_r4/Slice  nbits=18  boolean_output=off  mode=Upper Bit Location + Width  bit1=-288  base1=MSB of Input  bit0=0  base0=LSB of Input  dbl_ovrd=off  block_type=slice
  slice49 : xbsIndex_r4/Slice  nbits=18  boolean_output=off  mode=Upper Bit Location + Width  bit1=-270  base1=MSB of Input  bit0=0  base0=LSB of Input  dbl_ovrd=off  block_type=slice
  slice5 : xbsIndex_r4/Slice  nbits=18  boolean_output=off  mode=Upper Bit Location + Width  bit1=-1062  base1=MSB of Input  bit0=0  base0=LSB of Input  dbl_ovrd=off  block_type=slice
  slice50 : xbsIndex_r4/Slice  nbits=18  boolean_output=off  mode=Upper Bit Location + Width  bit1=-252  base1=MSB of Input  bit0=0  base0=LSB of Input  dbl_ovrd=off  block_type=slice
  slice51 : xbsIndex_r4/Slice  nbits=18  boolean_output=off  mode=Upper Bit Location + Width  bit1=-234  base1=MSB of Input  bit0=0  base0=LSB of Input  dbl_ovrd=off  block_type=slice
  slice52 : xbsIndex_r4/Slice  nbits=18  boolean_output=off  mode=Upper Bit Location + Width  bit1=-216  base1=MSB of Input  bit0=0  base0=LSB of Input  dbl_ovrd=off  block_type=slice
  slice53 : xbsIndex_r4/Slice  nbits=18  boolean_output=off  mode=Upper Bit Location + Width  bit1=-198  base1=MSB of Input  bit0=0  base0=LSB of Input  dbl_ovrd=off  block_type=slice
  slice54 : xbsIndex_r4/Slice  nbits=18  boolean_output=off  mode=Upper Bit Location + Width  bit1=-180  base1=MSB of Input  bit0=0  base0=LSB of Input  dbl_ovrd=off  block_type=slice
  slice55 : xbsIndex_r4/Slice  nbits=18  boolean_output=off  mode=Upper Bit Location + Width  bit1=-162  base1=MSB of Input  bit0=0  base0=LSB of Input  dbl_ovrd=off  block_type=slice
  slice56 : xbsIndex_r4/Slice  nbits=18  boolean_output=off  mode=Upper Bit Location + Width  bit1=-144  base1=MSB of Input  bit0=0  base0=LSB of Input  dbl_ovrd=off  block_type=slice
  slice57 : xbsIndex_r4/Slice  nbits=18  boolean_output=off  mode=Upper Bit Location + Width  bit1=-126  base1=MSB of Input  bit0=0  base0=LSB of Input  dbl_ovrd=off  block_type=slice
  slice58 : xbsIndex_r4/Slice  nbits=18  boolean_output=off  mode=Upper Bit Location + Width  bit1=-108  base1=MSB of Input  bit0=0  base0=LSB of Input  dbl_ovrd=off  block_type=slice
  slice59 : xbsIndex_r4/Slice  nbits=18  boolean_output=off  mode=Upper Bit Location + Width  bit1=-90  base1=MSB of Input  bit0=0  base0=LSB of Input  dbl_ovrd=off  block_type=slice
  slice6 : xbsIndex_r4/Slice  nbits=18  boolean_output=off  mode=Upper Bit Location + Width  bit1=-1044  base1=MSB of Input  bit0=0  base0=LSB of Input  dbl_ovrd=off  block_type=slice
  slice60 : xbsIndex_r4/Slice  nbits=18  boolean_output=off  mode=Upper Bit Location + Width  bit1=-72  base1=MSB of Input  bit0=0  base0=LSB of Input  dbl_ovrd=off  block_type=slice
  slice61 : xbsIndex_r4/Slice  nbits=18  boolean_output=off  mode=Upper Bit Location + Width  bit1=-54  base1=MSB of Input  bit0=0  base0=LSB of Input  dbl_ovrd=off  block_type=slice
  slice62 : xbsIndex_r4/Slice  nbits=18  boolean_output=off  mode=Upper Bit Location + Width  bit1=-36  base1=MSB of Input  bit0=0  base0=LSB of Input  dbl_ovrd=off  block_type=slice
  slice63 : xbsIndex_r4/Slice  nbits=18  boolean_output=off  mode=Upper Bit Location + Width  bit1=-18  base1=MSB of Input  bit0=0  base0=LSB of Input  dbl_ovrd=off  block_type=slice
  slice64 : xbsIndex_r4/Slice  nbits=18  boolean_output=off  mode=Upper Bit Location + Width  bit1=0  base1=MSB of Input  bit0=0  base0=LSB of Input  dbl_ovrd=off  block_type=slice
  slice7 : xbsIndex_r4/Slice  nbits=18  boolean_output=off  mode=Upper Bit Location + Width  bit1=-1026  base1=MSB of Input  bit0=0  base0=LSB of Input  dbl_ovrd=off  block_type=slice
  slice8 : xbsIndex_r4/Slice  nbits=18  boolean_output=off  mode=Upper Bit Location + Width  bit1=-1008  base1=MSB of Input  bit0=0  base0=LSB of Input  dbl_ovrd=off  block_type=slice
  slice9 : xbsIndex_r4/Slice  nbits=18  boolean_output=off  mode=Upper Bit Location + Width  bit1=-990  base1=MSB of Input  bit0=0  base0=LSB of Input  dbl_ovrd=off  block_type=slice
  msb_out64 : Outport
  out63 : Outport  Port=2
  out62 : Outport  Port=3
  out61 : Outport  Port=4
  out60 : Outport  Port=5
  out59 : Outport  Port=6
  out58 : Outport  Port=7
  out57 : Outport  Port=8
  out56 : Outport  Port=9
  out55 : Outport  Port=10
  out54 : Outport  Port=11
  out53 : Outport  Port=12
  out52 : Outport  Port=13
  out51 : Outport  Port=14
  out50 : Outport  Port=15
  out49 : Outport  Port=16
  out48 : Outport  Port=17
  out47 : Outport  Port=18
  out46 : Outport  Port=19
  out45 : Outport  Port=20
  out44 : Outport  Port=21
  out43 : Outport  Port=22
  out42 : Outport  Port=23
  out41 : Outport  Port=24
  out40 : Outport  Port=25
  out39 : Outport  Port=26
  out38 : Outport  Port=27
  out37 : Outport  Port=28
  out36 : Outport  Port=29
  out35 : Outport  Port=30
  out34 : Outport  Port=31
  out33 : Outport  Port=32
  out32 : Outport  Port=33
  out31 : Outport  Port=34
  out30 : Outport  Port=35
  out29 : Outport  Port=36
  out28 : Outport  Port=37
  out27 : Outport  Port=38
  out26 : Outport  Port=39
  out25 : Outport  Port=40
  out24 : Outport  Port=41
  out23 : Outport  Port=42
  out22 : Outport  Port=43
  out21 : Outport  Port=44
  out20 : Outport  Port=45
  out19 : Outport  Port=46
  out18 : Outport  Port=47
  out17 : Outport  Port=48
  out16 : Outport  Port=49
  out15 : Outport  Port=50
  out14 : Outport  Port=51
  out13 : Outport  Port=52
  out12 : Outport  Port=53
  out11 : Outport  Port=54
  out10 : Outport  Port=55
  out9 : Outport  Port=56
  out8 : Outport  Port=57
  out7 : Outport  Port=58
  out6 : Outport  Port=59
  out5 : Outport  Port=60
  out4 : Outport  Port=61
  out3 : Outport  Port=62
  out2 : Outport  Port=63
  lsb_out1 : Outport  Port=64
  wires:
  bus_in/1 -> slice64/1, slice63/1, slice62/1, slice61/1, slice60/1, slice59/1, slice58/1, slice57/1, slice56/1, slice55/1, slice54/1, slice53/1, slice52/1, slice51/1, slice50/1, slice49/1, slice48/1, slice47/1, slice46/1, slice45/1, slice44/1, slice43/1, slice42/1, slice41/1, slice40/1, slice39/1, slice38/1, slice37/1, slice36/1, slice35/1, slice34/1, slice33/1, slice32/1, slice31/1, slice30/1, slice29/1, slice28/1, slice27/1, slice26/1, slice25/1, slice24/1, slice23/1, slice22/1, slice21/1, slice20/1, slice19/1, slice18/1, slice17/1, slice16/1, slice15/1, slice14/1, slice13/1, slice12/1, slice11/1, slice10/1, slice9/1, slice8/1, slice7/1, slice6/1, slice5/1, slice4/1, slice3/1, slice2/1, slice1/1
  slice64/1 -> reinterpret64/1
  reinterpret64/1 -> msb_out64/1
  slice63/1 -> reinterpret63/1
  reinterpret63/1 -> out63/1
  slice62/1 -> reinterpret62/1
  reinterpret62/1 -> out62/1
  slice61/1 -> reinterpret61/1
  reinterpret61/1 -> out61/1
  slice60/1 -> reinterpret60/1
  reinterpret60/1 -> out60/1
  slice59/1 -> reinterpret59/1
  reinterpret59/1 -> out59/1
  slice58/1 -> reinterpret58/1
  reinterpret58/1 -> out58/1
  slice57/1 -> reinterpret57/1
  reinterpret57/1 -> out57/1
  slice56/1 -> reinterpret56/1
  reinterpret56/1 -> out56/1
  slice55/1 -> reinterpret55/1
  reinterpret55/1 -> out55/1
  slice54/1 -> reinterpret54/1
  reinterpret54/1 -> out54/1
  slice53/1 -> reinterpret53/1
  reinterpret53/1 -> out53/1
  slice52/1 -> reinterpret52/1
  reinterpret52/1 -> out52/1
  slice51/1 -> reinterpret51/1
  reinterpret51/1 -> out51/1
  slice50/1 -> reinterpret50/1
  reinterpret50/1 -> out50/1
  slice49/1 -> reinterpret49/1
  reinterpret49/1 -> out49/1
  slice48/1 -> reinterpret48/1
  reinterpret48/1 -> out48/1
  slice47/1 -> reinterpret47/1
  reinterpret47/1 -> out47/1
  slice46/1 -> reinterpret46/1
  reinterpret46/1 -> out46/1
  slice45/1 -> reinterpret45/1
  reinterpret45/1 -> out45/1
  slice44/1 -> reinterpret44/1
  reinterpret44/1 -> out44/1
  slice43/1 -> reinterpret43/1
  reinterpret43/1 -> out43/1
  slice42/1 -> reinterpret42/1
  reinterpret42/1 -> out42/1
  slice41/1 -> reinterpret41/1
  reinterpret41/1 -> out41/1
  slice40/1 -> reinterpret40/1
  reinterpret40/1 -> out40/1
  slice39/1 -> reinterpret39/1
  reinterpret39/1 -> out39/1
  slice38/1 -> reinterpret38/1
  reinterpret38/1 -> out38/1
  slice37/1 -> reinterpret37/1
  reinterpret37/1 -> out37/1
  slice36/1 -> reinterpret36/1
  reinterpret36/1 -> out36/1
  slice35/1 -> reinterpret35/1
  reinterpret35/1 -> out35/1
  slice34/1 -> reinterpret34/1
  reinterpret34/1 -> out34/1
  slice33/1 -> reinterpret33/1
  reinterpret33/1 -> out33/1
  slice32/1 -> reinterpret32/1
  reinterpret32/1 -> out32/1
  slice31/1 -> reinterpret31/1
  reinterpret31/1 -> out31/1
  slice30/1 -> reinterpret30/1
  reinterpret30/1 -> out30/1
  slice29/1 -> reinterpret29/1
  reinterpret29/1 -> out29/1
  slice28/1 -> reinterpret28/1
  reinterpret28/1 -> out28/1
  slice27/1 -> reinterpret27/1
  reinterpret27/1 -> out27/1
  slice26/1 -> reinterpret26/1
  reinterpret26/1 -> out26/1
  slice25/1 -> reinterpret25/1
  reinterpret25/1 -> out25/1
  slice24/1 -> reinterpret24/1
  reinterpret24/1 -> out24/1
  slice23/1 -> reinterpret23/1
  reinterpret23/1 -> out23/1
  slice22/1 -> reinterpret22/1
  reinterpret22/1 -> out22/1
  slice21/1 -> reinterpret21/1
  reinterpret21/1 -> out21/1
  slice20/1 -> reinterpret20/1
  reinterpret20/1 -> out20/1
  slice19/1 -> reinterpret19/1
  reinterpret19/1 -> out19/1
  slice18/1 -> reinterpret18/1
  reinterpret18/1 -> out18/1
  slice17/1 -> reinterpret17/1
  reinterpret17/1 -> out17/1
  slice16/1 -> reinterpret16/1
  reinterpret16/1 -> out16/1
  slice15/1 -> reinterpret15/1
  reinterpret15/1 -> out15/1
  slice14/1 -> reinterpret14/1
  reinterpret14/1 -> out14/1
  slice13/1 -> reinterpret13/1
  reinterpret13/1 -> out13/1
  slice12/1 -> reinterpret12/1
  reinterpret12/1 -> out12/1
  slice11/1 -> reinterpret11/1
  reinterpret11/1 -> out11/1
  slice10/1 -> reinterpret10/1
  reinterpret10/1 -> out10/1
  slice9/1 -> reinterpret9/1
  reinterpret9/1 -> out9/1
  slice8/1 -> reinterpret8/1
  reinterpret8/1 -> out8/1
  slice7/1 -> reinterpret7/1
  reinterpret7/1 -> out7/1
  slice6/1 -> reinterpret6/1
  reinterpret6/1 -> out6/1
  slice5/1 -> reinterpret5/1
  reinterpret5/1 -> out5/1
  slice4/1 -> reinterpret4/1
  reinterpret4/1 -> out4/1
  slice3/1 -> reinterpret3/1
  reinterpret3/1 -> out3/1
  slice2/1 -> reinterpret2/1
  reinterpret2/1 -> out2/1
  slice1/1 -> reinterpret1/1
  reinterpret1/1 -> lsb_out1/1

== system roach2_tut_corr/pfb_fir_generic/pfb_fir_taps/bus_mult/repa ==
  in : Inport
  bussify : Subsystem  AncestorBlock=casper_library_flow_control/bus_create
  out : Outport
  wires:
  in/1 -> bussify/1(in1)
  bussify/1(bus_out) -> out/1

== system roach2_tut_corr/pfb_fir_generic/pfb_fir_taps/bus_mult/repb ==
  in : Inport
  bussify : Subsystem  AncestorBlock=casper_library_flow_control/bus_create
  out : Outport
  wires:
  in/1 -> bussify/1(in1)
  bussify/1(bus_out) -> out/1

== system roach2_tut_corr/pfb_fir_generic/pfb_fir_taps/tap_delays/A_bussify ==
  in1 : Inport
  in2 : Inport  Port=2
  in3 : Inport  Port=3
  in4 : Inport  Port=4
  in5 : Inport  Port=5
  in6 : Inport  Port=6
  in7 : Inport  Port=7
  in8 : Inport  Port=8
  in9 : Inport  Port=9
  in10 : Inport  Port=10
  in11 : Inport  Port=11
  concatenate : xbsIndex_r4/Concat  num_inputs=11  dbl_ovrd=off  block_type=concat
  reinterpret{1..11} (11 alike) : xbsIndex_r4/Reinterpret  force_arith_type=on  arith_type=Unsigned  force_bin_pt=on  bin_pt=0  block_type=reinterpret
  bus_out : Outport
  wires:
  concatenate/1 -> bus_out/1
  in1/1 -> reinterpret1/1
  reinterpret1/1 -> concatenate/1
  in2/1 -> reinterpret2/1
  reinterpret2/1 -> concatenate/2
  in3/1 -> reinterpret3/1
  reinterpret3/1 -> concatenate/3
  in4/1 -> reinterpret4/1
  reinterpret4/1 -> concatenate/4
  in5/1 -> reinterpret5/1
  reinterpret5/1 -> concatenate/5
  in6/1 -> reinterpret6/1
  reinterpret6/1 -> concatenate/6
  in7/1 -> reinterpret7/1
  reinterpret7/1 -> concatenate/7
  in8/1 -> reinterpret8/1
  reinterpret8/1 -> concatenate/8
  in9/1 -> reinterpret9/1
  reinterpret9/1 -> concatenate/9
  in10/1 -> reinterpret10/1
  reinterpret10/1 -> concatenate/10
  in11/1 -> reinterpret11/1
  reinterpret11/1 -> concatenate/11

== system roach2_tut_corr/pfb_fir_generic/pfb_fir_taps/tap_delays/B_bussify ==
  in1 : Inport
  in2 : Inport  Port=2
  in3 : Inport  Port=3
  in4 : Inport  Port=4
  in5 : Inport  Port=5
  in6 : Inport  Port=6
  in7 : Inport  Port=7
  in8 : Inport  Port=8
  in9 : Inport  Port=9
  in10 : Inport  Port=10
  in11 : Inport  Port=11
  concatenate : xbsIndex_r4/Concat  num_inputs=11  dbl_ovrd=off  block_type=concat
  reinterpret{1..11} (11 alike) : xbsIndex_r4/Reinterpret  force_arith_type=on  arith_type=Unsigned  force_bin_pt=on  bin_pt=0  block_type=reinterpret
  bus_out : Outport
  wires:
  concatenate/1 -> bus_out/1
  in1/1 -> reinterpret1/1
  reinterpret1/1 -> concatenate/1
  in2/1 -> reinterpret2/1
  reinterpret2/1 -> concatenate/2
  in3/1 -> reinterpret3/1
  reinterpret3/1 -> concatenate/3
  in4/1 -> reinterpret4/1
  reinterpret4/1 -> concatenate/4
  in5/1 -> reinterpret5/1
  reinterpret5/1 -> concatenate/5
  in6/1 -> reinterpret6/1
  reinterpret6/1 -> concatenate/6
  in7/1 -> reinterpret7/1
  reinterpret7/1 -> concatenate/7
  in8/1 -> reinterpret8/1
  reinterpret8/1 -> concatenate/8
  in9/1 -> reinterpret9/1
  reinterpret9/1 -> concatenate/9
  in10/1 -> reinterpret10/1
  reinterpret10/1 -> concatenate/10
  in11/1 -> reinterpret11/1
  reinterpret11/1 -> concatenate/11

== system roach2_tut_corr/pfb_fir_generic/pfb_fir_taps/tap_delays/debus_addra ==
  bus_in : Inport
  reinterpret{1..11} (11 alike) : xbsIndex_r4/Reinterpret  force_arith_type=on  arith_type=Unsigned  force_bin_pt=on  bin_pt=0  block_type=reinterpret
  slice1 : xbsIndex_r4/Slice  nbits=9  boolean_output=off  mode=Upper Bit Location + Width  bit1=-90  base1=MSB of Input  bit0=0  base0=LSB of Input  dbl_ovrd=off  block_type=slice
  slice10 : xbsIndex_r4/Slice  nbits=9  boolean_output=off  mode=Upper Bit Location + Width  bit1=-9  base1=MSB of Input  bit0=0  base0=LSB of Input  dbl_ovrd=off  block_type=slice
  slice11 : xbsIndex_r4/Slice  nbits=9  boolean_output=off  mode=Upper Bit Location + Width  bit1=0  base1=MSB of Input  bit0=0  base0=LSB of Input  dbl_ovrd=off  block_type=slice
  slice2 : xbsIndex_r4/Slice  nbits=9  boolean_output=off  mode=Upper Bit Location + Width  bit1=-81  base1=MSB of Input  bit0=0  base0=LSB of Input  dbl_ovrd=off  block_type=slice
  slice3 : xbsIndex_r4/Slice  nbits=9  boolean_output=off  mode=Upper Bit Location + Width  bit1=-72  base1=MSB of Input  bit0=0  base0=LSB of Input  dbl_ovrd=off  block_type=slice
  slice4 : xbsIndex_r4/Slice  nbits=9  boolean_output=off  mode=Upper Bit Location + Width  bit1=-63  base1=MSB of Input  bit0=0  base0=LSB of Input  dbl_ovrd=off  block_type=slice
  slice5 : xbsIndex_r4/Slice  nbits=9  boolean_output=off  mode=Upper Bit Location + Width  bit1=-54  base1=MSB of Input  bit0=0  base0=LSB of Input  dbl_ovrd=off  block_type=slice
  slice6 : xbsIndex_r4/Slice  nbits=9  boolean_output=off  mode=Upper Bit Location + Width  bit1=-45  base1=MSB of Input  bit0=0  base0=LSB of Input  dbl_ovrd=off  block_type=slice
  slice7 : xbsIndex_r4/Slice  nbits=9  boolean_output=off  mode=Upper Bit Location + Width  bit1=-36  base1=MSB of Input  bit0=0  base0=LSB of Input  dbl_ovrd=off  block_type=slice
  slice8 : xbsIndex_r4/Slice  nbits=9  boolean_output=off  mode=Upper Bit Location + Width  bit1=-27  base1=MSB of Input  bit0=0  base0=LSB of Input  dbl_ovrd=off  block_type=slice
  slice9 : xbsIndex_r4/Slice  nbits=9  boolean_output=off  mode=Upper Bit Location + Width  bit1=-18  base1=MSB of Input  bit0=0  base0=LSB of Input  dbl_ovrd=off  block_type=slice
  msb_out11 : Outport
  out10 : Outport  Port=2
  out9 : Outport  Port=3
  out8 : Outport  Port=4
  out7 : Outport  Port=5
  out6 : Outport  Port=6
  out5 : Outport  Port=7
  out4 : Outport  Port=8
  out3 : Outport  Port=9
  out2 : Outport  Port=10
  lsb_out1 : Outport  Port=11
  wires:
  bus_in/1 -> slice11/1, slice10/1, slice9/1, slice8/1, slice7/1, slice6/1, slice5/1, slice4/1, slice3/1, slice2/1, slice1/1
  slice11/1 -> reinterpret11/1
  reinterpret11/1 -> msb_out11/1
  slice10/1 -> reinterpret10/1
  reinterpret10/1 -> out10/1
  slice9/1 -> reinterpret9/1
  reinterpret9/1 -> out9/1
  slice8/1 -> reinterpret8/1
  reinterpret8/1 -> out8/1
  slice7/1 -> reinterpret7/1
  reinterpret7/1 -> out7/1
  slice6/1 -> reinterpret6/1
  reinterpret6/1 -> out6/1
  slice5/1 -> reinterpret5/1
  reinterpret5/1 -> out5/1
  slice4/1 -> reinterpret4/1
  reinterpret4/1 -> out4/1
  slice3/1 -> reinterpret3/1
  reinterpret3/1 -> out3/1
  slice2/1 -> reinterpret2/1
  reinterpret2/1 -> out2/1
  slice1/1 -> reinterpret1/1
  reinterpret1/1 -> lsb_out1/1

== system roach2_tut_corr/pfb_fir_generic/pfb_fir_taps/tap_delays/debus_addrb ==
  bus_in : Inport
  reinterpret{1..11} (11 alike) : xbsIndex_r4/Reinterpret  force_arith_type=on  arith_type=Unsigned  force_bin_pt=on  bin_pt=0  block_type=reinterpret
  slice1 : xbsIndex_r4/Slice  nbits=9  boolean_output=off  mode=Upper Bit Location + Width  bit1=-90  base1=MSB of Input  bit0=0  base0=LSB of Input  dbl_ovrd=off  block_type=slice
  slice10 : xbsIndex_r4/Slice  nbits=9  boolean_output=off  mode=Upper Bit Location + Width  bit1=-9  base1=MSB of Input  bit0=0  base0=LSB of Input  dbl_ovrd=off  block_type=slice
  slice11 : xbsIndex_r4/Slice  nbits=9  boolean_output=off  mode=Upper Bit Location + Width  bit1=0  base1=MSB of Input  bit0=0  base0=LSB of Input  dbl_ovrd=off  block_type=slice
  slice2 : xbsIndex_r4/Slice  nbits=9  boolean_output=off  mode=Upper Bit Location + Width  bit1=-81  base1=MSB of Input  bit0=0  base0=LSB of Input  dbl_ovrd=off  block_type=slice
  slice3 : xbsIndex_r4/Slice  nbits=9  boolean_output=off  mode=Upper Bit Location + Width  bit1=-72  base1=MSB of Input  bit0=0  base0=LSB of Input  dbl_ovrd=off  block_type=slice
  slice4 : xbsIndex_r4/Slice  nbits=9  boolean_output=off  mode=Upper Bit Location + Width  bit1=-63  base1=MSB of Input  bit0=0  base0=LSB of Input  dbl_ovrd=off  block_type=slice
  slice5 : xbsIndex_r4/Slice  nbits=9  boolean_output=off  mode=Upper Bit Location + Width  bit1=-54  base1=MSB of Input  bit0=0  base0=LSB of Input  dbl_ovrd=off  block_type=slice
  slice6 : xbsIndex_r4/Slice  nbits=9  boolean_output=off  mode=Upper Bit Location + Width  bit1=-45  base1=MSB of Input  bit0=0  base0=LSB of Input  dbl_ovrd=off  block_type=slice
  slice7 : xbsIndex_r4/Slice  nbits=9  boolean_output=off  mode=Upper Bit Location + Width  bit1=-36  base1=MSB of Input  bit0=0  base0=LSB of Input  dbl_ovrd=off  block_type=slice
  slice8 : xbsIndex_r4/Slice  nbits=9  boolean_output=off  mode=Upper Bit Location + Width  bit1=-27  base1=MSB of Input  bit0=0  base0=LSB of Input  dbl_ovrd=off  block_type=slice
  slice9 : xbsIndex_r4/Slice  nbits=9  boolean_output=off  mode=Upper Bit Location + Width  bit1=-18  base1=MSB of Input  bit0=0  base0=LSB of Input  dbl_ovrd=off  block_type=slice
  msb_out11 : Outport
  out10 : Outport  Port=2
  out9 : Outport  Port=3
  out8 : Outport  Port=4
  out7 : Outport  Port=5
  out6 : Outport  Port=6
  out5 : Outport  Port=7
  out4 : Outport  Port=8
  out3 : Outport  Port=9
  out2 : Outport  Port=10
  lsb_out1 : Outport  Port=11
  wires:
  bus_in/1 -> slice11/1, slice10/1, slice9/1, slice8/1, slice7/1, slice6/1, slice5/1, slice4/1, slice3/1, slice2/1, slice1/1
  slice11/1 -> reinterpret11/1
  reinterpret11/1 -> msb_out11/1
  slice10/1 -> reinterpret10/1
  reinterpret10/1 -> out10/1
  slice9/1 -> reinterpret9/1
  reinterpret9/1 -> out9/1
  slice8/1 -> reinterpret8/1
  reinterpret8/1 -> out8/1
  slice7/1 -> reinterpret7/1
  reinterpret7/1 -> out7/1
  slice6/1 -> reinterpret6/1
  reinterpret6/1 -> out6/1
  slice5/1 -> reinterpret5/1
  reinterpret5/1 -> out5/1
  slice4/1 -> reinterpret4/1
  reinterpret4/1 -> out4/1
  slice3/1 -> reinterpret3/1
  reinterpret3/1 -> out3/1
  slice2/1 -> reinterpret2/1
  reinterpret2/1 -> out2/1
  slice1/1 -> reinterpret1/1
  reinterpret1/1 -> lsb_out1/1

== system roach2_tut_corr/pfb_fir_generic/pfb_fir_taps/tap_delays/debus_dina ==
  bus_in : Inport
  reinterpret{1..11} (11 alike) : xbsIndex_r4/Reinterpret  force_arith_type=on  arith_type=Unsigned  force_bin_pt=on  bin_pt=0  block_type=reinterpret
  slice1 : xbsIndex_r4/Slice  nbits=36  boolean_output=off  mode=Upper Bit Location + Width  bit1=-348  base1=MSB of Input  bit0=0  base0=LSB of Input  dbl_ovrd=off  block_type=slice
  slice10 : xbsIndex_r4/Slice  nbits=36  boolean_output=off  mode=Upper Bit Location + Width  bit1=-24  base1=MSB of Input  bit0=0  base0=LSB of Input  dbl_ovrd=off  block_type=slice
  slice11 : xbsIndex_r4/Slice  nbits=24  boolean_output=off  mode=Upper Bit Location + Width  bit1=0  base1=MSB of Input  bit0=0  base0=LSB of Input  dbl_ovrd=off  block_type=slice
  slice2 : xbsIndex_r4/Slice  nbits=36  boolean_output=off  mode=Upper Bit Location + Width  bit1=-312  base1=MSB of Input  bit0=0  base0=LSB of Input  dbl_ovrd=off  block_type=slice
  slice3 : xbsIndex_r4/Slice  nbits=36  boolean_output=off  mode=Upper Bit Location + Width  bit1=-276  base1=MSB of Input  bit0=0  base0=LSB of Input  dbl_ovrd=off  block_type=slice
  slice4 : xbsIndex_r4/Slice  nbits=36  boolean_output=off  mode=Upper Bit Location + Width  bit1=-240  base1=MSB of Input  bit0=0  base0=LSB of Input  dbl_ovrd=off  block_type=slice
  slice5 : xbsIndex_r4/Slice  nbits=36  boolean_output=off  mode=Upper Bit Location + Width  bit1=-204  base1=MSB of Input  bit0=0  base0=LSB of Input  dbl_ovrd=off  block_type=slice
  slice6 : xbsIndex_r4/Slice  nbits=36  boolean_output=off  mode=Upper Bit Location + Width  bit1=-168  base1=MSB of Input  bit0=0  base0=LSB of Input  dbl_ovrd=off  block_type=slice
  slice7 : xbsIndex_r4/Slice  nbits=36  boolean_output=off  mode=Upper Bit Location + Width  bit1=-132  base1=MSB of Input  bit0=0  base0=LSB of Input  dbl_ovrd=off  block_type=slice
  slice8 : xbsIndex_r4/Slice  nbits=36  boolean_output=off  mode=Upper Bit Location + Width  bit1=-96  base1=MSB of Input  bit0=0  base0=LSB of Input  dbl_ovrd=off  block_type=slice
  slice9 : xbsIndex_r4/Slice  nbits=36  boolean_output=off  mode=Upper Bit Location + Width  bit1=-60  base1=MSB of Input  bit0=0  base0=LSB of Input  dbl_ovrd=off  block_type=slice
  msb_out11 : Outport
  out10 : Outport  Port=2
  out9 : Outport  Port=3
  out8 : Outport  Port=4
  out7 : Outport  Port=5
  out6 : Outport  Port=6
  out5 : Outport  Port=7
  out4 : Outport  Port=8
  out3 : Outport  Port=9
  out2 : Outport  Port=10
  lsb_out1 : Outport  Port=11
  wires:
  bus_in/1 -> slice11/1, slice10/1, slice9/1, slice8/1, slice7/1, slice6/1, slice5/1, slice4/1, slice3/1, slice2/1, slice1/1
  slice11/1 -> reinterpret11/1
  reinterpret11/1 -> msb_out11/1
  slice10/1 -> reinterpret10/1
  reinterpret10/1 -> out10/1
  slice9/1 -> reinterpret9/1
  reinterpret9/1 -> out9/1
  slice8/1 -> reinterpret8/1
  reinterpret8/1 -> out8/1
  slice7/1 -> reinterpret7/1
  reinterpret7/1 -> out7/1
  slice6/1 -> reinterpret6/1
  reinterpret6/1 -> out6/1
  slice5/1 -> reinterpret5/1
  reinterpret5/1 -> out5/1
  slice4/1 -> reinterpret4/1
  reinterpret4/1 -> out4/1
  slice3/1 -> reinterpret3/1
  reinterpret3/1 -> out3/1
  slice2/1 -> reinterpret2/1
  reinterpret2/1 -> out2/1
  slice1/1 -> reinterpret1/1
  reinterpret1/1 -> lsb_out1/1

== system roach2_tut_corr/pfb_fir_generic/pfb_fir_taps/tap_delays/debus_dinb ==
  bus_in : Inport
  reinterpret{1..11} (11 alike) : xbsIndex_r4/Reinterpret  force_arith_type=on  arith_type=Unsigned  force_bin_pt=on  bin_pt=0  block_type=reinterpret
  slice1 : xbsIndex_r4/Slice  nbits=36  boolean_output=off  mode=Upper Bit Location + Width  bit1=-348  base1=MSB of Input  bit0=0  base0=LSB of Input  dbl_ovrd=off  block_type=slice
  slice10 : xbsIndex_r4/Slice  nbits=36  boolean_output=off  mode=Upper Bit Location + Width  bit1=-24  base1=MSB of Input  bit0=0  base0=LSB of Input  dbl_ovrd=off  block_type=slice
  slice11 : xbsIndex_r4/Slice  nbits=24  boolean_output=off  mode=Upper Bit Location + Width  bit1=0  base1=MSB of Input  bit0=0  base0=LSB of Input  dbl_ovrd=off  block_type=slice
  slice2 : xbsIndex_r4/Slice  nbits=36  boolean_output=off  mode=Upper Bit Location + Width  bit1=-312  base1=MSB of Input  bit0=0  base0=LSB of Input  dbl_ovrd=off  block_type=slice
  slice3 : xbsIndex_r4/Slice  nbits=36  boolean_output=off  mode=Upper Bit Location + Width  bit1=-276  base1=MSB of Input  bit0=0  base0=LSB of Input  dbl_ovrd=off  block_type=slice
  slice4 : xbsIndex_r4/Slice  nbits=36  boolean_output=off  mode=Upper Bit Location + Width  bit1=-240  base1=MSB of Input  bit0=0  base0=LSB of Input  dbl_ovrd=off  block_type=slice
  slice5 : xbsIndex_r4/Slice  nbits=36  boolean_output=off  mode=Upper Bit Location + Width  bit1=-204  base1=MSB of Input  bit0=0  base0=LSB of Input  dbl_ovrd=off  block_type=slice
  slice6 : xbsIndex_r4/Slice  nbits=36  boolean_output=off  mode=Upper Bit Location + Width  bit1=-168  base1=MSB of Input  bit0=0  base0=LSB of Input  dbl_ovrd=off  block_type=slice
  slice7 : xbsIndex_r4/Slice  nbits=36  boolean_output=off  mode=Upper Bit Location + Width  bit1=-132  base1=MSB of Input  bit0=0  base0=LSB of Input  dbl_ovrd=off  block_type=slice
  slice8 : xbsIndex_r4/Slice  nbits=36  boolean_output=off  mode=Upper Bit Location + Width  bit1=-96  base1=MSB of Input  bit0=0  base0=LSB of Input  dbl_ovrd=off  block_type=slice
  slice9 : xbsIndex_r4/Slice  nbits=36  boolean_output=off  mode=Upper Bit Location + Width  bit1=-60  base1=MSB of Input  bit0=0  base0=LSB of Input  dbl_ovrd=off  block_type=slice
  msb_out11 : Outport
  out10 : Outport  Port=2
  out9 : Outport  Port=3
  out8 : Outport  Port=4
  out7 : Outport  Port=5
  out6 : Outport  Port=6
  out5 : Outport  Port=7
  out4 : Outport  Port=8
  out3 : Outport  Port=9
  out2 : Outport  Port=10
  lsb_out1 : Outport  Port=11
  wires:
  bus_in/1 -> slice11/1, slice10/1, slice9/1, slice8/1, slice7/1, slice6/1, slice5/1, slice4/1, slice3/1, slice2/1, slice1/1
  slice11/1 -> reinterpret11/1
  reinterpret11/1 -> msb_out11/1
  slice10/1 -> reinterpret10/1
  reinterpret10/1 -> out10/1
  slice9/1 -> reinterpret9/1
  reinterpret9/1 -> out9/1
  slice8/1 -> reinterpret8/1
  reinterpret8/1 -> out8/1
  slice7/1 -> reinterpret7/1
  reinterpret7/1 -> out7/1
  slice6/1 -> reinterpret6/1
  reinterpret6/1 -> out6/1
  slice5/1 -> reinterpret5/1
  reinterpret5/1 -> out5/1
  slice4/1 -> reinterpret4/1
  reinterpret4/1 -> out4/1
  slice3/1 -> reinterpret3/1
  reinterpret3/1 -> out3/1
  slice2/1 -> reinterpret2/1
  reinterpret2/1 -> out2/1
  slice1/1 -> reinterpret1/1
  reinterpret1/1 -> lsb_out1/1

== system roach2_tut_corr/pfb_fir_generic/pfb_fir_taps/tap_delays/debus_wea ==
  bus_in : Inport
  slice1 : xbsIndex_r4/Slice  nbits=1  boolean_output=on  mode=Upper Bit Location + Width  bit1=-10  base1=MSB of Input  bit0=0  base0=LSB of Input  dbl_ovrd=off  block_type=slice
  slice10 : xbsIndex_r4/Slice  nbits=1  boolean_output=on  mode=Upper Bit Location + Width  bit1=-1  base1=MSB of Input  bit0=0  base0=LSB of Input  dbl_ovrd=off  block_type=slice
  slice11 : xbsIndex_r4/Slice  nbits=1  boolean_output=on  mode=Upper Bit Location + Width  bit1=0  base1=MSB of Input  bit0=0  base0=LSB of Input  dbl_ovrd=off  block_type=slice
  slice2 : xbsIndex_r4/Slice  nbits=1  boolean_output=on  mode=Upper Bit Location + Width  bit1=-9  base1=MSB of Input  bit0=0  base0=LSB of Input  dbl_ovrd=off  block_type=slice
  slice3 : xbsIndex_r4/Slice  nbits=1  boolean_output=on  mode=Upper Bit Location + Width  bit1=-8  base1=MSB of Input  bit0=0  base0=LSB of Input  dbl_ovrd=off  block_type=slice
  slice4 : xbsIndex_r4/Slice  nbits=1  boolean_output=on  mode=Upper Bit Location + Width  bit1=-7  base1=MSB of Input  bit0=0  base0=LSB of Input  dbl_ovrd=off  block_type=slice
  slice5 : xbsIndex_r4/Slice  nbits=1  boolean_output=on  mode=Upper Bit Location + Width  bit1=-6  base1=MSB of Input  bit0=0  base0=LSB of Input  dbl_ovrd=off  block_type=slice
  slice6 : xbsIndex_r4/Slice  nbits=1  boolean_output=on  mode=Upper Bit Location + Width  bit1=-5  base1=MSB of Input  bit0=0  base0=LSB of Input  dbl_ovrd=off  block_type=slice
  slice7 : xbsIndex_r4/Slice  nbits=1  boolean_output=on  mode=Upper Bit Location + Width  bit1=-4  base1=MSB of Input  bit0=0  base0=LSB of Input  dbl_ovrd=off  block_type=slice
  slice8 : xbsIndex_r4/Slice  nbits=1  boolean_output=on  mode=Upper Bit Location + Width  bit1=-3  base1=MSB of Input  bit0=0  base0=LSB of Input  dbl_ovrd=off  block_type=slice
  slice9 : xbsIndex_r4/Slice  nbits=1  boolean_output=on  mode=Upper Bit Location + Width  bit1=-2  base1=MSB of Input  bit0=0  base0=LSB of Input  dbl_ovrd=off  block_type=slice
  msb_out11 : Outport
  out10 : Outport  Port=2
  out9 : Outport  Port=3
  out8 : Outport  Port=4
  out7 : Outport  Port=5
  out6 : Outport  Port=6
  out5 : Outport  Port=7
  out4 : Outport  Port=8
  out3 : Outport  Port=9
  out2 : Outport  Port=10
  lsb_out1 : Outport  Port=11
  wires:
  bus_in/1 -> slice11/1, slice10/1, slice9/1, slice8/1, slice7/1, slice6/1, slice5/1, slice4/1, slice3/1, slice2/1, slice1/1
  slice11/1 -> msb_out11/1
  slice10/1 -> out10/1
  slice9/1 -> out9/1
  slice8/1 -> out8/1
  slice7/1 -> out7/1
  slice6/1 -> out6/1
  slice5/1 -> out5/1
  slice4/1 -> out4/1
  slice3/1 -> out3/1
  slice2/1 -> out2/1
  slice1/1 -> lsb_out1/1

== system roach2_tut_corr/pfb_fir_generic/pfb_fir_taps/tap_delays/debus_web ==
  bus_in : Inport
  slice1 : xbsIndex_r4/Slice  nbits=1  boolean_output=on  mode=Upper Bit Location + Width  bit1=-10  base1=MSB of Input  bit0=0  base0=LSB of Input  dbl_ovrd=off  block_type=slice
  slice10 : xbsIndex_r4/Slice  nbits=1  boolean_output=on  mode=Upper Bit Location + Width  bit1=-1  base1=MSB of Input  bit0=0  base0=LSB of Input  dbl_ovrd=off  block_type=slice
  slice11 : xbsIndex_r4/Slice  nbits=1  boolean_output=on  mode=Upper Bit Location + Width  bit1=0  base1=MSB of Input  bit0=0  base0=LSB of Input  dbl_ovrd=off  block_type=slice
  slice2 : xbsIndex_r4/Slice  nbits=1  boolean_output=on  mode=Upper Bit Location + Width  bit1=-9  base1=MSB of Input  bit0=0  base0=LSB of Input  dbl_ovrd=off  block_type=slice
  slice3 : xbsIndex_r4/Slice  nbits=1  boolean_output=on  mode=Upper Bit Location + Width  bit1=-8  base1=MSB of Input  bit0=0  base0=LSB of Input  dbl_ovrd=off  block_type=slice
  slice4 : xbsIndex_r4/Slice  nbits=1  boolean_output=on  mode=Upper Bit Location + Width  bit1=-7  base1=MSB of Input  bit0=0  base0=LSB of Input  dbl_ovrd=off  block_type=slice
  slice5 : xbsIndex_r4/Slice  nbits=1  boolean_output=on  mode=Upper Bit Location + Width  bit1=-6  base1=MSB of Input  bit0=0  base0=LSB of Input  dbl_ovrd=off  block_type=slice
  slice6 : xbsIndex_r4/Slice  nbits=1  boolean_output=on  mode=Upper Bit Location + Width  bit1=-5  base1=MSB of Input  bit0=0  base0=LSB of Input  dbl_ovrd=off  block_type=slice
  slice7 : xbsIndex_r4/Slice  nbits=1  boolean_output=on  mode=Upper Bit Location + Width  bit1=-4  base1=MSB of Input  bit0=0  base0=LSB of Input  dbl_ovrd=off  block_type=slice
  slice8 : xbsIndex_r4/Slice  nbits=1  boolean_output=on  mode=Upper Bit Location + Width  bit1=-3  base1=MSB of Input  bit0=0  base0=LSB of Input  dbl_ovrd=off  block_type=slice
  slice9 : xbsIndex_r4/Slice  nbits=1  boolean_output=on  mode=Upper Bit Location + Width  bit1=-2  base1=MSB of Input  bit0=0  base0=LSB of Input  dbl_ovrd=off  block_type=slice
  msb_out11 : Outport
  out10 : Outport  Port=2
  out9 : Outport  Port=3
  out8 : Outport  Port=4
  out7 : Outport  Port=5
  out6 : Outport  Port=6
  out5 : Outport  Port=7
  out4 : Outport  Port=8
  out3 : Outport  Port=9
  out2 : Outport  Port=10
  lsb_out1 : Outport  Port=11
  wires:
  bus_in/1 -> slice11/1, slice10/1, slice9/1, slice8/1, slice7/1, slice6/1, slice5/1, slice4/1, slice3/1, slice2/1, slice1/1
  slice11/1 -> msb_out11/1
  slice10/1 -> out10/1
  slice9/1 -> out9/1
  slice8/1 -> out8/1
  slice7/1 -> out7/1
  slice6/1 -> out6/1
  slice5/1 -> out5/1
  slice4/1 -> out4/1
  slice3/1 -> out3/1
  slice2/1 -> out2/1
  slice1/1 -> lsb_out1/1

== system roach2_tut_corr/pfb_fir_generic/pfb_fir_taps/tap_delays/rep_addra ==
  in : Inport
  bussify : Subsystem  AncestorBlock=casper_library_flow_control/bus_create
  din0_{0..10} (11 alike) : xbsIndex_r4/Delay  rst=off  infoeditControl=Selection of Reset will increase slice count due to use of real FFs and instead of SRLs  en=off  latency=1  dbl_ovrd=off  reg_retiming=off  block_type=delay
  out : Outport
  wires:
  in/1 -> din0_0/1, din0_1/1, din0_2/1, din0_3/1, din0_4/1, din0_5/1, din0_6/1, din0_7/1, din0_8/1, din0_9/1, din0_10/1
  din0_0/1 -> bussify/1(in1)
  din0_1/1 -> bussify/2(in2)
  din0_2/1 -> bussify/3(in3)
  din0_3/1 -> bussify/4(in4)
  din0_4/1 -> bussify/5(in5)
  din0_5/1 -> bussify/6(in6)
  din0_6/1 -> bussify/7(in7)
  din0_7/1 -> bussify/8(in8)
  din0_8/1 -> bussify/9(in9)
  din0_9/1 -> bussify/10(in10)
  din0_10/1 -> bussify/11(in11)
  bussify/1(bus_out) -> out/1

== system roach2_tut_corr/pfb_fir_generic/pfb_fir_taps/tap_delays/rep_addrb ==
  in : Inport
  bussify : Subsystem  AncestorBlock=casper_library_flow_control/bus_create
  din0_{0..10} (11 alike) : xbsIndex_r4/Delay  rst=off  infoeditControl=Selection of Reset will increase slice count due to use of real FFs and instead of SRLs  en=off  latency=1  dbl_ovrd=off  reg_retiming=off  block_type=delay
  out : Outport
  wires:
  in/1 -> din0_0/1, din0_1/1, din0_2/1, din0_3/1, din0_4/1, din0_5/1, din0_6/1, din0_7/1, din0_8/1, din0_9/1, din0_10/1
  din0_0/1 -> bussify/1(in1)
  din0_1/1 -> bussify/2(in2)
  din0_2/1 -> bussify/3(in3)
  din0_3/1 -> bussify/4(in4)
  din0_4/1 -> bussify/5(in5)
  din0_5/1 -> bussify/6(in6)
  din0_6/1 -> bussify/7(in7)
  din0_7/1 -> bussify/8(in8)
  din0_8/1 -> bussify/9(in9)
  din0_9/1 -> bussify/10(in10)
  din0_10/1 -> bussify/11(in11)
  bussify/1(bus_out) -> out/1

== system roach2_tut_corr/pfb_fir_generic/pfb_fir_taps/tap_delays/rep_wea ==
  in : Inport
  bussify : Subsystem  AncestorBlock=casper_library_flow_control/bus_create
  out : Outport
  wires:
  in/1 -> bussify/1(in1), bussify/2(in2), bussify/3(in3), bussify/4(in4), bussify/5(in5), bussify/6(in6), bussify/7(in7), bussify/8(in8), bussify/9(in9), bussify/10(in10), bussify/11(in11)
  bussify/1(bus_out) -> out/1

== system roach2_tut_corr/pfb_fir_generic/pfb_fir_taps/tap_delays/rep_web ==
  in : Inport
  bussify : Subsystem  AncestorBlock=casper_library_flow_control/bus_create
  din0_{0..10} (11 alike) : xbsIndex_r4/Delay  rst=off  infoeditControl=Selection of Reset will increase slice count due to use of real FFs and instead of SRLs  en=off  latency=1  dbl_ovrd=off  reg_retiming=off  block_type=delay
  out : Outport
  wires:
  in/1 -> din0_0/1, din0_1/1, din0_2/1, din0_3/1, din0_4/1, din0_5/1, din0_6/1, din0_7/1, din0_8/1, din0_9/1, din0_10/1
  din0_0/1 -> bussify/1(in1)
  din0_1/1 -> bussify/2(in2)
  din0_2/1 -> bussify/3(in3)
  din0_3/1 -> bussify/4(in4)
  din0_4/1 -> bussify/5(in5)
  din0_5/1 -> bussify/6(in6)
  din0_6/1 -> bussify/7(in7)
  din0_7/1 -> bussify/8(in8)
  din0_8/1 -> bussify/9(in9)
  din0_9/1 -> bussify/10(in10)
  din0_10/1 -> bussify/11(in11)
  bussify/1(bus_out) -> out/1

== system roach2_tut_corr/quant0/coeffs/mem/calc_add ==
  note: Use behavioural HDL so that gets optimised to minimum logic
  note: If reading/writing words smaller than 32 bits, change address so that addressing is big endian instead of little, otherwise pass through
  in : Inport
  add_sub : xbsIndex_r4/AddSub  mode=Subtraction  use_carryin=off  use_carryout=off  en=off  latency=0  precision=User Defined  arith_type=Unsigned  n_bits=max(1, log2(32/data_width))  bin_pt=0  quantization=Truncate  overflow=Wrap  dbl_ovrd=off  use_behavioral_HDL=on  hw_selection=Fabric  pipelined=off  block_type=addsub
  concat : xbsIndex_r4/Concat  num_inputs=2  dbl_ovrd=off  block_type=concat
  const : xbsIndex_r4/Constant  const=max(0, 32/data_width-1)  gui_display_data_type=Fixed-point  arith_type=Unsigned  n_bits=max(1, log2(32/data_width))  bin_pt=0  preci_type=Single  exp_width=8  frac_width=24  explicit_period=on  period=sample_rate  equ=P=C  opselect=C  inp2=PCIN>>17  opr=+  inp1=P  carry=CIN  dbl_ovrd=off  block_type=constant
  convert_addr : xbsIndex_r4/Convert  gui_display_data_type=Fixed-point  arith_type=Unsigned  n_bits=addr_width  bin_pt=0  float_type=Single  exp_bits=8  fraction_bits=24  quantization=Truncate  overflow=Wrap  en=off  latency=0  dbl_ovrd=off  pipeline=off  block_type=convert
  lsw : xbsIndex_r4/Slice  nbits=max(1, log2(32/data_width))  boolean_output=off  mode=Lower Bit Location + Width  bit1=0  base1=MSB of Input  bit0=0  base0=LSB of Input  dbl_ovrd=off  block_type=slice
  manipulate : xbsIndex_r4/Constant  const=min(1, floor(32/data_width) - 1)  gui_display_data_type=Fixed-point  arith_type=Unsigned  n_bits=1  bin_pt=0  preci_type=Single  exp_width=8  frac_width=24  explicit_period=on  period=sample_rate  equ=P=C  opselect=C  inp2=PCIN>>17  opr=+  inp1=P  carry=CIN  dbl_ovrd=off  block_type=constant
  msw : xbsIndex_r4/Slice  nbits=addr_width - max(1, log2(32/data_width))  boolean_output=off  mode=Upper Bit Location + Width  bit1=0  base1=MSB of Input  bit0=0  base0=LSB of Input  dbl_ovrd=off  block_type=slice
  mux : xbsIndex_r4/Mux  inputs=2  en=off  latency=0  precision=Full  arith_type=Unsigned  n_bits=16  bin_pt=14  quantization=Truncate  overflow=Wrap  dbl_ovrd=off  block_type=mux
  out : Outport
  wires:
  convert_addr/1 -> mux/2, msw/1, lsw/1
  const/1 -> add_sub/1
  lsw/1 -> add_sub/2
  mux/1 -> out/1
  manipulate/1 -> mux/1
  concat/1 -> mux/3
  msw/1 -> concat/1
  add_sub/1 -> concat/2
  in/1 -> convert_addr/1

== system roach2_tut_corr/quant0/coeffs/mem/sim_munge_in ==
  din : Inport
  reinterpret_out : xbsIndex_r4/Reinterpret  force_arith_type=on  arith_type=Unsigned  force_bin_pt=on  bin_pt=0  block_type=reinterpret
  dout : Outport
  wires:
  reinterpret_out/1 -> dout/1
  din/1 -> reinterpret_out/1

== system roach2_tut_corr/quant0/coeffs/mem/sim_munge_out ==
  din : Inport
  reinterpret_out : xbsIndex_r4/Reinterpret  force_arith_type=on  arith_type=Unsigned  force_bin_pt=on  bin_pt=0  block_type=reinterpret
  dout : Outport
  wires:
  reinterpret_out/1 -> dout/1
  din/1 -> reinterpret_out/1

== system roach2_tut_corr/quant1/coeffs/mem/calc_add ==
  note: Use behavioural HDL so that gets optimised to minimum logic
  note: If reading/writing words smaller than 32 bits, change address so that addressing is big endian instead of little, otherwise pass through
  in : Inport
  add_sub : xbsIndex_r4/AddSub  mode=Subtraction  use_carryin=off  use_carryout=off  en=off  latency=0  precision=User Defined  arith_type=Unsigned  n_bits=max(1, log2(32/data_width))  bin_pt=0  quantization=Truncate  overflow=Wrap  dbl_ovrd=off  use_behavioral_HDL=on  hw_selection=Fabric  pipelined=off  block_type=addsub
  concat : xbsIndex_r4/Concat  num_inputs=2  dbl_ovrd=off  block_type=concat
  const : xbsIndex_r4/Constant  const=max(0, 32/data_width-1)  gui_display_data_type=Fixed-point  arith_type=Unsigned  n_bits=max(1, log2(32/data_width))  bin_pt=0  preci_type=Single  exp_width=8  frac_width=24  explicit_period=on  period=sample_rate  equ=P=C  opselect=C  inp2=PCIN>>17  opr=+  inp1=P  carry=CIN  dbl_ovrd=off  block_type=constant
  convert_addr : xbsIndex_r4/Convert  gui_display_data_type=Fixed-point  arith_type=Unsigned  n_bits=addr_width  bin_pt=0  float_type=Single  exp_bits=8  fraction_bits=24  quantization=Truncate  overflow=Wrap  en=off  latency=0  dbl_ovrd=off  pipeline=off  block_type=convert
  lsw : xbsIndex_r4/Slice  nbits=max(1, log2(32/data_width))  boolean_output=off  mode=Lower Bit Location + Width  bit1=0  base1=MSB of Input  bit0=0  base0=LSB of Input  dbl_ovrd=off  block_type=slice
  manipulate : xbsIndex_r4/Constant  const=min(1, floor(32/data_width) - 1)  gui_display_data_type=Fixed-point  arith_type=Unsigned  n_bits=1  bin_pt=0  preci_type=Single  exp_width=8  frac_width=24  explicit_period=on  period=sample_rate  equ=P=C  opselect=C  inp2=PCIN>>17  opr=+  inp1=P  carry=CIN  dbl_ovrd=off  block_type=constant
  msw : xbsIndex_r4/Slice  nbits=addr_width - max(1, log2(32/data_width))  boolean_output=off  mode=Upper Bit Location + Width  bit1=0  base1=MSB of Input  bit0=0  base0=LSB of Input  dbl_ovrd=off  block_type=slice
  mux : xbsIndex_r4/Mux  inputs=2  en=off  latency=0  precision=Full  arith_type=Unsigned  n_bits=16  bin_pt=14  quantization=Truncate  overflow=Wrap  dbl_ovrd=off  block_type=mux
  out : Outport
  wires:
  convert_addr/1 -> mux/2, msw/1, lsw/1
  const/1 -> add_sub/1
  lsw/1 -> add_sub/2
  mux/1 -> out/1
  manipulate/1 -> mux/1
  concat/1 -> mux/3
  msw/1 -> concat/1
  add_sub/1 -> concat/2
  in/1 -> convert_addr/1

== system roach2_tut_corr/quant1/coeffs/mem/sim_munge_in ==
  din : Inport
  reinterpret_out : xbsIndex_r4/Reinterpret  force_arith_type=on  arith_type=Unsigned  force_bin_pt=on  bin_pt=0  block_type=reinterpret
  dout : Outport
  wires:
  reinterpret_out/1 -> dout/1
  din/1 -> reinterpret_out/1
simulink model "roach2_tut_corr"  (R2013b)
settings: Solver=VariableStepDiscrete  SolverMode=SingleTasking  StartTime=0.0  StopTime=100  RelTol=1e-3
undefined symbols (not defined in the file): add_latency, addr_width, Bit, bitfield, BitWidth, bram_latency, burst_size, casper_library_scopes, conv_latency, data_width, DelayLen, fan_latency, FFTSize, FFTStage, getfield, increment, led, Location, Lower, mult_latency, mux_latency, n_bits, n_bits_data, n_inputs, n_streams, n_taps, neg_latency, negate_latency, nsamples, pfb_size, pulse_len, reset_period, ROACH, ROACH2, snapshot, sx475t, sync_period, sync_period_bits, Upper, UseCounter, Width
libraries: xbsIndex_r4 x24444, casper_library_misc x73, xbsReplacements_r4 x34, casper_library_delays x14, xps_library x7
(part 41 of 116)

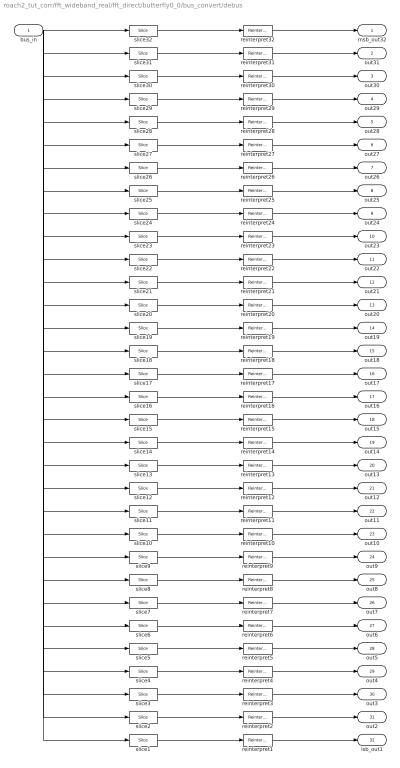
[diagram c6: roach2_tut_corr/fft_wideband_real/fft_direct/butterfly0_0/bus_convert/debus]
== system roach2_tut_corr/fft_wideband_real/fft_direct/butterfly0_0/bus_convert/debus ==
  bus_in : Inport
  reinterpret{1..32} (32 alike) : xbsIndex_r4/Reinterpret  force_arith_type=on  arith_type="Signed  (2's comp)"  force_bin_pt=on  bin_pt=18  block_type=reinterpret
  slice1 : xbsIndex_r4/Slice  nbits=21  boolean_output=off  mode=Upper Bit Location + Width  bit1=-651  base1=MSB of Input  bit0=0  base0=LSB of Input  dbl_ovrd=off  block_type=slice
  slice10 : xbsIndex_r4/Slice  nbits=21  boolean_output=off  mode=Upper Bit Location + Width  bit1=-462  base1=MSB of Input  bit0=0  base0=LSB of Input  dbl_ovrd=off  block_type=slice
  slice11 : xbsIndex_r4/Slice  nbits=21  boolean_output=off  mode=Upper Bit Location + Width  bit1=-441  base1=MSB of Input  bit0=0  base0=LSB of Input  dbl_ovrd=off  block_type=slice
  slice12 : xbsIndex_r4/Slice  nbits=21  boolean_output=off  mode=Upper Bit Location + Width  bit1=-420  base1=MSB of Input  bit0=0  base0=LSB of Input  dbl_ovrd=off  block_type=slice
  slice13 : xbsIndex_r4/Slice  nbits=21  boolean_output=off  mode=Upper Bit Location + Width  bit1=-399  base1=MSB of Input  bit0=0  base0=LSB of Input  dbl_ovrd=off  block_type=slice
  slice14 : xbsIndex_r4/Slice  nbits=21  boolean_output=off  mode=Upper Bit Location + Width  bit1=-378  base1=MSB of Input  bit0=0  base0=LSB of Input  dbl_ovrd=off  block_type=slice
  slice15 : xbsIndex_r4/Slice  nbits=21  boolean_output=off  mode=Upper Bit Location + Width  bit1=-357  base1=MSB of Input  bit0=0  base0=LSB of Input  dbl_ovrd=off  block_type=slice
  slice16 : xbsIndex_r4/Slice  nbits=21  boolean_output=off  mode=Upper Bit Location + Width  bit1=-336  base1=MSB of Input  bit0=0  base0=LSB of Input  dbl_ovrd=off  block_type=slice
  slice17 : xbsIndex_r4/Slice  nbits=21  boolean_output=off  mode=Upper Bit Location + Width  bit1=-315  base1=MSB of Input  bit0=0  base0=LSB of Input  dbl_ovrd=off  block_type=slice
  slice18 : xbsIndex_r4/Slice  nbits=21  boolean_output=off  mode=Upper Bit Location + Width  bit1=-294  base1=MSB of Input  bit0=0  base0=LSB of Input  dbl_ovrd=off  block_type=slice
  slice19 : xbsIndex_r4/Slice  nbits=21  boolean_output=off  mode=Upper Bit Location + Width  bit1=-273  base1=MSB of Input  bit0=0  base0=LSB of Input  dbl_ovrd=off  block_type=slice
  slice2 : xbsIndex_r4/Slice  nbits=21  boolean_output=off  mode=Upper Bit Location + Width  bit1=-630  base1=MSB of Input  bit0=0  base0=LSB of Input  dbl_ovrd=off  block_type=slice
  slice20 : xbsIndex_r4/Slice  nbits=21  boolean_output=off  mode=Upper Bit Location + Width  bit1=-252  base1=MSB of Input  bit0=0  base0=LSB of Input  dbl_ovrd=off  block_type=slice
  slice21 : xbsIndex_r4/Slice  nbits=21  boolean_output=off  mode=Upper Bit Location + Width  bit1=-231  base1=MSB of Input  bit0=0  base0=LSB of Input  dbl_ovrd=off  block_type=slice
  slice22 : xbsIndex_r4/Slice  nbits=21  boolean_output=off  mode=Upper Bit Location + Width  bit1=-210  base1=MSB of Input  bit0=0  base0=LSB of Input  dbl_ovrd=off  block_type=slice
  slice23 : xbsIndex_r4/Slice  nbits=21  boolean_output=off  mode=Upper Bit Location + Width  bit1=-189  base1=MSB of Input  bit0=0  base0=LSB of Input  dbl_ovrd=off  block_type=slice
  slice24 : xbsIndex_r4/Slice  nbits=21  boolean_output=off  mode=Upper Bit Location + Width  bit1=-168  base1=MSB of Input  bit0=0  base0=LSB of Input  dbl_ovrd=off  block_type=slice
  slice25 : xbsIndex_r4/Slice  nbits=21  boolean_output=off  mode=Upper Bit Location + Width  bit1=-147  base1=MSB of Input  bit0=0  base0=LSB of Input  dbl_ovrd=off  block_type=slice
  slice26 : xbsIndex_r4/Slice  nbits=21  boolean_output=off  mode=Upper Bit Location + Width  bit1=-126  base1=MSB of Input  bit0=0  base0=LSB of Input  dbl_ovrd=off  block_type=slice
  slice27 : xbsIndex_r4/Slice  nbits=21  boolean_output=off  mode=Upper Bit Location + Width  bit1=-105  base1=MSB of Input  bit0=0  base0=LSB of Input  dbl_ovrd=off  block_type=slice
  slice28 : xbsIndex_r4/Slice  nbits=21  boolean_output=off  mode=Upper Bit Location + Width  bit1=-84  base1=MSB of Input  bit0=0  base0=LSB of Input  dbl_ovrd=off  block_type=slice
  slice29 : xbsIndex_r4/Slice  nbits=21  boolean_output=off  mode=Upper Bit Location + Width  bit1=-63  base1=MSB of Input  bit0=0  base0=LSB of Input  dbl_ovrd=off  block_type=slice
  slice3 : xbsIndex_r4/Slice  nbits=21  boolean_output=off  mode=Upper Bit Location + Width  bit1=-609  base1=MSB of Input  bit0=0  base0=LSB of Input  dbl_ovrd=off  block_type=slice
  slice30 : xbsIndex_r4/Slice  nbits=21  boolean_output=off  mode=Upper Bit Location + Width  bit1=-42  base1=MSB of Input  bit0=0  base0=LSB of Input  dbl_ovrd=off  block_type=slice
  slice31 : xbsIndex_r4/Slice  nbits=21  boolean_output=off  mode=Upper Bit Location + Width  bit1=-21  base1=MSB of Input  bit0=0  base0=LSB of Input  dbl_ovrd=off  block_type=slice
  slice32 : xbsIndex_r4/Slice  nbits=21  boolean_output=off  mode=Upper Bit Location + Width  bit1=0  base1=MSB of Input  bit0=0  base0=LSB of Input  dbl_ovrd=off  block_type=slice
  slice4 : xbsIndex_r4/Slice  nbits=21  boolean_output=off  mode=Upper Bit Location + Width  bit1=-588  base1=MSB of Input  bit0=0  base0=LSB of Input  dbl_ovrd=off  block_type=slice
  slice5 : xbsIndex_r4/Slice  nbits=21  boolean_output=off  mode=Upper Bit Location + Width  bit1=-567  base1=MSB of Input  bit0=0  base0=LSB of Input  dbl_ovrd=off  block_type=slice
  slice6 : xbsIndex_r4/Slice  nbits=21  boolean_output=off  mode=Upper Bit Location + Width  bit1=-546  base1=MSB of Input  bit0=0  base0=LSB of Input  dbl_ovrd=off  block_type=slice
  slice7 : xbsIndex_r4/Slice  nbits=21  boolean_output=off  mode=Upper Bit Location + Width  bit1=-525  base1=MSB of Input  bit0=0  base0=LSB of Input  dbl_ovrd=off  block_type=slice
  slice8 : xbsIndex_r4/Slice  nbits=21  boolean_output=off  mode=Upper Bit Location + Width  bit1=-504  base1=MSB of Input  bit0=0  base0=LSB of Input  dbl_ovrd=off  block_type=slice
  slice9 : xbsIndex_r4/Slice  nbits=21  boolean_output=off  mode=Upper Bit Location + Width  bit1=-483  base1=MSB of Input  bit0=0  base0=LSB of Input  dbl_ovrd=off  block_type=slice
  msb_out32 : Outport
  out31 : Outport  Port=2
  out30 : Outport  Port=3
  out29 : Outport  Port=4
  out28 : Outport  Port=5
  out27 : Outport  Port=6
  out26 : Outport  Port=7
  out25 : Outport  Port=8
  out24 : Outport  Port=9
  out23 : Outport  Port=10
  out22 : Outport  Port=11
  out21 : Outport  Port=12
  out20 : Outport  Port=13
  out19 : Outport  Port=14
  out18 : Outport  Port=15
  out17 : Outport  Port=16
  out16 : Outport  Port=17
  out15 : Outport  Port=18
  out14 : Outport  Port=19
  out13 : Outport  Port=20
  out12 : Outport  Port=21
  out11 : Outport  Port=22
  out10 : Outport  Port=23
  out9 : Outport  Port=24
  out8 : Outport  Port=25
  out7 : Outport  Port=26
  out6 : Outport  Port=27
  out5 : Outport  Port=28
  out4 : Outport  Port=29
  out3 : Outport  Port=30
  out2 : Outport  Port=31
  lsb_out1 : Outport  Port=32
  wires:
  bus_in/1 -> slice32/1, slice31/1, slice30/1, slice29/1, slice28/1, slice27/1, slice26/1, slice25/1, slice24/1, slice23/1, slice22/1, slice21/1, slice20/1, slice19/1, slice18/1, slice17/1, slice16/1, slice15/1, slice14/1, slice13/1, slice12/1, slice11/1, slice10/1, slice9/1, slice8/1, slice7/1, slice6/1, slice5/1, slice4/1, slice3/1, slice2/1, slice1/1
  slice32/1 -> reinterpret32/1
  reinterpret32/1 -> msb_out32/1
  slice31/1 -> reinterpret31/1
  reinterpret31/1 -> out31/1
  slice30/1 -> reinterpret30/1
  reinterpret30/1 -> out30/1
  slice29/1 -> reinterpret29/1
  reinterpret29/1 -> out29/1
  slice28/1 -> reinterpret28/1
  reinterpret28/1 -> out28/1
  slice27/1 -> reinterpret27/1
  reinterpret27/1 -> out27/1
  slice26/1 -> reinterpret26/1
  reinterpret26/1 -> out26/1
  slice25/1 -> reinterpret25/1
  reinterpret25/1 -> out25/1
  slice24/1 -> reinterpret24/1
  reinterpret24/1 -> out24/1
  slice23/1 -> reinterpret23/1
  reinterpret23/1 -> out23/1
  slice22/1 -> reinterpret22/1
  reinterpret22/1 -> out22/1
  slice21/1 -> reinterpret21/1
  reinterpret21/1 -> out21/1
  slice20/1 -> reinterpret20/1
  reinterpret20/1 -> out20/1
  slice19/1 -> reinterpret19/1
  reinterpret19/1 -> out19/1
  slice18/1 -> reinterpret18/1
  reinterpret18/1 -> out18/1
  slice17/1 -> reinterpret17/1
  reinterpret17/1 -> out17/1
  slice16/1 -> reinterpret16/1
  reinterpret16/1 -> out16/1
  slice15/1 -> reinterpret15/1
  reinterpret15/1 -> out15/1
  slice14/1 -> reinterpret14/1
  reinterpret14/1 -> out14/1
  slice13/1 -> reinterpret13/1
  reinterpret13/1 -> out13/1
  slice12/1 -> reinterpret12/1
  reinterpret12/1 -> out12/1
  slice11/1 -> reinterpret11/1
  reinterpret11/1 -> out11/1
  slice10/1 -> reinterpret10/1
  reinterpret10/1 -> out10/1
  slice9/1 -> reinterpret9/1
  reinterpret9/1 -> out9/1
  slice8/1 -> reinterpret8/1
  reinterpret8/1 -> out8/1
  slice7/1 -> reinterpret7/1
  reinterpret7/1 -> out7/1
  slice6/1 -> reinterpret6/1
  reinterpret6/1 -> out6/1
  slice5/1 -> reinterpret5/1
  reinterpret5/1 -> out5/1
  slice4/1 -> reinterpret4/1
  reinterpret4/1 -> out4/1
  slice3/1 -> reinterpret3/1
  reinterpret3/1 -> out3/1
  slice2/1 -> reinterpret2/1
  reinterpret2/1 -> out2/1
  slice1/1 -> reinterpret1/1
  reinterpret1/1 -> lsb_out1/1

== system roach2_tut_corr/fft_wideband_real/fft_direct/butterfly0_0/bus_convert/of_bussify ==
  in1 : Inport
  in2 : Inport  Port=2
  in3 : Inport  Port=3
  in4 : Inport  Port=4
  in5 : Inport  Port=5
  in6 : Inport  Port=6
  in7 : Inport  Port=7
  in8 : Inport  Port=8
  in9 : Inport  Port=9
  in10 : Inport  Port=10
  in11 : Inport  Port=11
  in12 : Inport  Port=12
  in13 : Inport  Port=13
  in14 : Inport  Port=14
  in15 : Inport  Port=15
  in16 : Inport  Port=16
  in17 : Inport  Port=17
  in18 : Inport  Port=18
  in19 : Inport  Port=19
  in20 : Inport  Port=20
  in21 : Inport  Port=21
  in22 : Inport  Port=22
  in23 : Inport  Port=23
  in24 : Inport  Port=24
  in25 : Inport  Port=25
  in26 : Inport  Port=26
  in27 : Inport  Port=27
  in28 : Inport  Port=28
  in29 : Inport  Port=29
  in30 : Inport  Port=30
  in31 : Inport  Port=31
  in32 : Inport  Port=32
  concatenate : xbsIndex_r4/Concat  num_inputs=32  dbl_ovrd=off  block_type=concat
  reinterpret{1..32} (32 alike) : xbsIndex_r4/Reinterpret  force_arith_type=on  arith_type=Unsigned  force_bin_pt=on  bin_pt=0  block_type=reinterpret
  bus_out : Outport
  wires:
  concatenate/1 -> bus_out/1
  in1/1 -> reinterpret1/1
  reinterpret1/1 -> concatenate/1
  in2/1 -> reinterpret2/1
  reinterpret2/1 -> concatenate/2
  in3/1 -> reinterpret3/1
  reinterpret3/1 -> concatenate/3
  in4/1 -> reinterpret4/1
  reinterpret4/1 -> concatenate/4
  in5/1 -> reinterpret5/1
  reinterpret5/1 -> concatenate/5
  in6/1 -> reinterpret6/1
  reinterpret6/1 -> concatenate/6
  in7/1 -> reinterpret7/1
  reinterpret7/1 -> concatenate/7
  in8/1 -> reinterpret8/1
  reinterpret8/1 -> concatenate/8
  in9/1 -> reinterpret9/1
  reinterpret9/1 -> concatenate/9
  in10/1 -> reinterpret10/1
  reinterpret10/1 -> concatenate/10
  in11/1 -> reinterpret11/1
  reinterpret11/1 -> concatenate/11
  in12/1 -> reinterpret12/1
  reinterpret12/1 -> concatenate/12
  in13/1 -> reinterpret13/1
  reinterpret13/1 -> concatenate/13
  in14/1 -> reinterpret14/1
  reinterpret14/1 -> concatenate/14
  in15/1 -> reinterpret15/1
  reinterpret15/1 -> concatenate/15
  in16/1 -> reinterpret16/1
  reinterpret16/1 -> concatenate/16
  in17/1 -> reinterpret17/1
  reinterpret17/1 -> concatenate/17
  in18/1 -> reinterpret18/1
  reinterpret18/1 -> concatenate/18
  in19/1 -> reinterpret19/1
  reinterpret19/1 -> concatenate/19
  in20/1 -> reinterpret20/1
  reinterpret20/1 -> concatenate/20
  in21/1 -> reinterpret21/1
  reinterpret21/1 -> concatenate/21
  in22/1 -> reinterpret22/1
  reinterpret22/1 -> concatenate/22
  in23/1 -> reinterpret23/1
  reinterpret23/1 -> concatenate/23
  in24/1 -> reinterpret24/1
  reinterpret24/1 -> concatenate/24
  in25/1 -> reinterpret25/1
  reinterpret25/1 -> concatenate/25
  in26/1 -> reinterpret26/1
  reinterpret26/1 -> concatenate/26
  in27/1 -> reinterpret27/1
  reinterpret27/1 -> concatenate/27
  in28/1 -> reinterpret28/1
  reinterpret28/1 -> concatenate/28
  in29/1 -> reinterpret29/1
  reinterpret29/1 -> concatenate/29
  in30/1 -> reinterpret30/1
  reinterpret30/1 -> concatenate/30
  in31/1 -> reinterpret31/1
  reinterpret31/1 -> concatenate/31
  in32/1 -> reinterpret32/1
  reinterpret32/1 -> concatenate/32

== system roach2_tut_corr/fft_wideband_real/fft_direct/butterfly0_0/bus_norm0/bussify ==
  in1 : Inport
  in2 : Inport  Port=2
  in3 : Inport  Port=3
  in4 : Inport  Port=4
  in5 : Inport  Port=5
  in6 : Inport  Port=6
  in7 : Inport  Port=7
  in8 : Inport  Port=8
  in9 : Inport  Port=9
  in10 : Inport  Port=10
  in11 : Inport  Port=11
  in12 : Inport  Port=12
  in13 : Inport  Port=13
  in14 : Inport  Port=14
  in15 : Inport  Port=15
  in16 : Inport  Port=16
  in17 : Inport  Port=17
  in18 : Inport  Port=18
  in19 : Inport  Port=19
  in20 : Inport  Port=20
  in21 : Inport  Port=21
  in22 : Inport  Port=22
  in23 : Inport  Port=23
  in24 : Inport  Port=24
  in25 : Inport  Port=25
  in26 : Inport  Port=26
  in27 : Inport  Port=27
  in28 : Inport  Port=28
  in29 : Inport  Port=29
  in30 : Inport  Port=30
  in31 : Inport  Port=31
  in32 : Inport  Port=32
  concatenate : xbsIndex_r4/Concat  num_inputs=32  dbl_ovrd=off  block_type=concat
  reinterpret{1..32} (32 alike) : xbsIndex_r4/Reinterpret  force_arith_type=on  arith_type=Unsigned  force_bin_pt=on  bin_pt=0  block_type=reinterpret
  bus_out : Outport
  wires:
  concatenate/1 -> bus_out/1
  in1/1 -> reinterpret1/1
  reinterpret1/1 -> concatenate/1
  in2/1 -> reinterpret2/1
  reinterpret2/1 -> concatenate/2
  in3/1 -> reinterpret3/1
  reinterpret3/1 -> concatenate/3
  in4/1 -> reinterpret4/1
  reinterpret4/1 -> concatenate/4
  in5/1 -> reinterpret5/1
  reinterpret5/1 -> concatenate/5
  in6/1 -> reinterpret6/1
  reinterpret6/1 -> concatenate/6
  in7/1 -> reinterpret7/1
  reinterpret7/1 -> concatenate/7
  in8/1 -> reinterpret8/1
  reinterpret8/1 -> concatenate/8
  in9/1 -> reinterpret9/1
  reinterpret9/1 -> concatenate/9
  in10/1 -> reinterpret10/1
  reinterpret10/1 -> concatenate/10
  in11/1 -> reinterpret11/1
  reinterpret11/1 -> concatenate/11
  in12/1 -> reinterpret12/1
  reinterpret12/1 -> concatenate/12
  in13/1 -> reinterpret13/1
  reinterpret13/1 -> concatenate/13
  in14/1 -> reinterpret14/1
  reinterpret14/1 -> concatenate/14
  in15/1 -> reinterpret15/1
  reinterpret15/1 -> concatenate/15
  in16/1 -> reinterpret16/1
  reinterpret16/1 -> concatenate/16
  in17/1 -> reinterpret17/1
  reinterpret17/1 -> concatenate/17
  in18/1 -> reinterpret18/1
  reinterpret18/1 -> concatenate/18
  in19/1 -> reinterpret19/1
  reinterpret19/1 -> concatenate/19
  in20/1 -> reinterpret20/1
  reinterpret20/1 -> concatenate/20
  in21/1 -> reinterpret21/1
  reinterpret21/1 -> concatenate/21
  in22/1 -> reinterpret22/1
  reinterpret22/1 -> concatenate/22
  in23/1 -> reinterpret23/1
  reinterpret23/1 -> concatenate/23
  in24/1 -> reinterpret24/1
  reinterpret24/1 -> concatenate/24
  in25/1 -> reinterpret25/1
  reinterpret25/1 -> concatenate/25
  in26/1 -> reinterpret26/1
  reinterpret26/1 -> concatenate/26
  in27/1 -> reinterpret27/1
  reinterpret27/1 -> concatenate/27
  in28/1 -> reinterpret28/1
  reinterpret28/1 -> concatenate/28
  in29/1 -> reinterpret29/1
  reinterpret29/1 -> concatenate/29
  in30/1 -> reinterpret30/1
  reinterpret30/1 -> concatenate/30
  in31/1 -> reinterpret31/1
  reinterpret31/1 -> concatenate/31
  in32/1 -> reinterpret32/1
  reinterpret32/1 -> concatenate/32

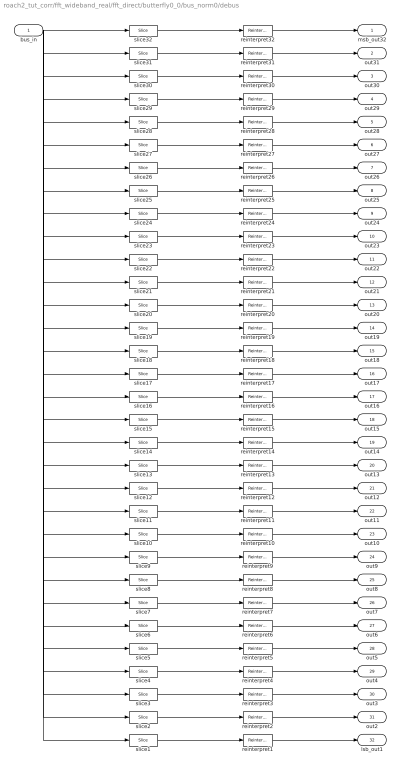
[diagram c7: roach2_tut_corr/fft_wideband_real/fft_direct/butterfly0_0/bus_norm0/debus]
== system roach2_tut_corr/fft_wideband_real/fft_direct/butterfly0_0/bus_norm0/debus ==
  bus_in : Inport
  reinterpret{1..32} (32 alike) : xbsIndex_r4/Reinterpret  force_arith_type=on  arith_type="Signed  (2's comp)"  force_bin_pt=on  bin_pt=17  block_type=reinterpret
  slice1 : xbsIndex_r4/Slice  nbits=20  boolean_output=off  mode=Upper Bit Location + Width  bit1=-620  base1=MSB of Input  bit0=0  base0=LSB of Input  dbl_ovrd=off  block_type=slice
  slice10 : xbsIndex_r4/Slice  nbits=20  boolean_output=off  mode=Upper Bit Location + Width  bit1=-440  base1=MSB of Input  bit0=0  base0=LSB of Input  dbl_ovrd=off  block_type=slice
  slice11 : xbsIndex_r4/Slice  nbits=20  boolean_output=off  mode=Upper Bit Location + Width  bit1=-420  base1=MSB of Input  bit0=0  base0=LSB of Input  dbl_ovrd=off  block_type=slice
  slice12 : xbsIndex_r4/Slice  nbits=20  boolean_output=off  mode=Upper Bit Location + Width  bit1=-400  base1=MSB of Input  bit0=0  base0=LSB of Input  dbl_ovrd=off  block_type=slice
  slice13 : xbsIndex_r4/Slice  nbits=20  boolean_output=off  mode=Upper Bit Location + Width  bit1=-380  base1=MSB of Input  bit0=0  base0=LSB of Input  dbl_ovrd=off  block_type=slice
  slice14 : xbsIndex_r4/Slice  nbits=20  boolean_output=off  mode=Upper Bit Location + Width  bit1=-360  base1=MSB of Input  bit0=0  base0=LSB of Input  dbl_ovrd=off  block_type=slice
  slice15 : xbsIndex_r4/Slice  nbits=20  boolean_output=off  mode=Upper Bit Location + Width  bit1=-340  base1=MSB of Input  bit0=0  base0=LSB of Input  dbl_ovrd=off  block_type=slice
  slice16 : xbsIndex_r4/Slice  nbits=20  boolean_output=off  mode=Upper Bit Location + Width  bit1=-320  base1=MSB of Input  bit0=0  base0=LSB of Input  dbl_ovrd=off  block_type=slice
  slice17 : xbsIndex_r4/Slice  nbits=20  boolean_output=off  mode=Upper Bit Location + Width  bit1=-300  base1=MSB of Input  bit0=0  base0=LSB of Input  dbl_ovrd=off  block_type=slice
  slice18 : xbsIndex_r4/Slice  nbits=20  boolean_output=off  mode=Upper Bit Location + Width  bit1=-280  base1=MSB of Input  bit0=0  base0=LSB of Input  dbl_ovrd=off  block_type=slice
  slice19 : xbsIndex_r4/Slice  nbits=20  boolean_output=off  mode=Upper Bit Location + Width  bit1=-260  base1=MSB of Input  bit0=0  base0=LSB of Input  dbl_ovrd=off  block_type=slice
  slice2 : xbsIndex_r4/Slice  nbits=20  boolean_output=off  mode=Upper Bit Location + Width  bit1=-600  base1=MSB of Input  bit0=0  base0=LSB of Input  dbl_ovrd=off  block_type=slice
  slice20 : xbsIndex_r4/Slice  nbits=20  boolean_output=off  mode=Upper Bit Location + Width  bit1=-240  base1=MSB of Input  bit0=0  base0=LSB of Input  dbl_ovrd=off  block_type=slice
  slice21 : xbsIndex_r4/Slice  nbits=20  boolean_output=off  mode=Upper Bit Location + Width  bit1=-220  base1=MSB of Input  bit0=0  base0=LSB of Input  dbl_ovrd=off  block_type=slice
  slice22 : xbsIndex_r4/Slice  nbits=20  boolean_output=off  mode=Upper Bit Location + Width  bit1=-200  base1=MSB of Input  bit0=0  base0=LSB of Input  dbl_ovrd=off  block_type=slice
  slice23 : xbsIndex_r4/Slice  nbits=20  boolean_output=off  mode=Upper Bit Location + Width  bit1=-180  base1=MSB of Input  bit0=0  base0=LSB of Input  dbl_ovrd=off  block_type=slice
  slice24 : xbsIndex_r4/Slice  nbits=20  boolean_output=off  mode=Upper Bit Location + Width  bit1=-160  base1=MSB of Input  bit0=0  base0=LSB of Input  dbl_ovrd=off  block_type=slice
  slice25 : xbsIndex_r4/Slice  nbits=20  boolean_output=off  mode=Upper Bit Location + Width  bit1=-140  base1=MSB of Input  bit0=0  base0=LSB of Input  dbl_ovrd=off  block_type=slice
  slice26 : xbsIndex_r4/Slice  nbits=20  boolean_output=off  mode=Upper Bit Location + Width  bit1=-120  base1=MSB of Input  bit0=0  base0=LSB of Input  dbl_ovrd=off  block_type=slice
  slice27 : xbsIndex_r4/Slice  nbits=20  boolean_output=off  mode=Upper Bit Location + Width  bit1=-100  base1=MSB of Input  bit0=0  base0=LSB of Input  dbl_ovrd=off  block_type=slice
  slice28 : xbsIndex_r4/Slice  nbits=20  boolean_output=off  mode=Upper Bit Location + Width  bit1=-80  base1=MSB of Input  bit0=0  base0=LSB of Input  dbl_ovrd=off  block_type=slice
  slice29 : xbsIndex_r4/Slice  nbits=20  boolean_output=off  mode=Upper Bit Location + Width  bit1=-60  base1=MSB of Input  bit0=0  base0=LSB of Input  dbl_ovrd=off  block_type=slice
  slice3 : xbsIndex_r4/Slice  nbits=20  boolean_output=off  mode=Upper Bit Location + Width  bit1=-580  base1=MSB of Input  bit0=0  base0=LSB of Input  dbl_ovrd=off  block_type=slice
  slice30 : xbsIndex_r4/Slice  nbits=20  boolean_output=off  mode=Upper Bit Location + Width  bit1=-40  base1=MSB of Input  bit0=0  base0=LSB of Input  dbl_ovrd=off  block_type=slice
  slice31 : xbsIndex_r4/Slice  nbits=20  boolean_output=off  mode=Upper Bit Location + Width  bit1=-20  base1=MSB of Input  bit0=0  base0=LSB of Input  dbl_ovrd=off  block_type=slice
  slice32 : xbsIndex_r4/Slice  nbits=20  boolean_output=off  mode=Upper Bit Location + Width  bit1=0  base1=MSB of Input  bit0=0  base0=LSB of Input  dbl_ovrd=off  block_type=slice
  slice4 : xbsIndex_r4/Slice  nbits=20  boolean_output=off  mode=Upper Bit Location + Width  bit1=-560  base1=MSB of Input  bit0=0  base0=LSB of Input  dbl_ovrd=off  block_type=slice
  slice5 : xbsIndex_r4/Slice  nbits=20  boolean_output=off  mode=Upper Bit Location + Width  bit1=-540  base1=MSB of Input  bit0=0  base0=LSB of Input  dbl_ovrd=off  block_type=slice
  slice6 : xbsIndex_r4/Slice  nbits=20  boolean_output=off  mode=Upper Bit Location + Width  bit1=-520  base1=MSB of Input  bit0=0  base0=LSB of Input  dbl_ovrd=off  block_type=slice
  slice7 : xbsIndex_r4/Slice  nbits=20  boolean_output=off  mode=Upper Bit Location + Width  bit1=-500  base1=MSB of Input  bit0=0  base0=LSB of Input  dbl_ovrd=off  block_type=slice
  slice8 : xbsIndex_r4/Slice  nbits=20  boolean_output=off  mode=Upper Bit Location + Width  bit1=-480  base1=MSB of Input  bit0=0  base0=LSB of Input  dbl_ovrd=off  block_type=slice
  slice9 : xbsIndex_r4/Slice  nbits=20  boolean_output=off  mode=Upper Bit Location + Width  bit1=-460  base1=MSB of Input  bit0=0  base0=LSB of Input  dbl_ovrd=off  block_type=slice
  msb_out32 : Outport
  out31 : Outport  Port=2
  out30 : Outport  Port=3
  out29 : Outport  Port=4
  out28 : Outport  Port=5
  out27 : Outport  Port=6
  out26 : Outport  Port=7
  out25 : Outport  Port=8
  out24 : Outport  Port=9
  out23 : Outport  Port=10
  out22 : Outport  Port=11
  out21 : Outport  Port=12
  out20 : Outport  Port=13
  out19 : Outport  Port=14
  out18 : Outport  Port=15
  out17 : Outport  Port=16
  out16 : Outport  Port=17
  out15 : Outport  Port=18
  out14 : Outport  Port=19
  out13 : Outport  Port=20
  out12 : Outport  Port=21
  out11 : Outport  Port=22
  out10 : Outport  Port=23
  out9 : Outport  Port=24
  out8 : Outport  Port=25
  out7 : Outport  Port=26
  out6 : Outport  Port=27
  out5 : Outport  Port=28
  out4 : Outport  Port=29
  out3 : Outport  Port=30
  out2 : Outport  Port=31
  lsb_out1 : Outport  Port=32
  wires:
  bus_in/1 -> slice32/1, slice31/1, slice30/1, slice29/1, slice28/1, slice27/1, slice26/1, slice25/1, slice24/1, slice23/1, slice22/1, slice21/1, slice20/1, slice19/1, slice18/1, slice17/1, slice16/1, slice15/1, slice14/1, slice13/1, slice12/1, slice11/1, slice10/1, slice9/1, slice8/1, slice7/1, slice6/1, slice5/1, slice4/1, slice3/1, slice2/1, slice1/1
  slice32/1 -> reinterpret32/1
  reinterpret32/1 -> msb_out32/1
  slice31/1 -> reinterpret31/1
  reinterpret31/1 -> out31/1
  slice30/1 -> reinterpret30/1
  reinterpret30/1 -> out30/1
  slice29/1 -> reinterpret29/1
  reinterpret29/1 -> out29/1
  slice28/1 -> reinterpret28/1
  reinterpret28/1 -> out28/1
  slice27/1 -> reinterpret27/1
  reinterpret27/1 -> out27/1
  slice26/1 -> reinterpret26/1
  reinterpret26/1 -> out26/1
  slice25/1 -> reinterpret25/1
  reinterpret25/1 -> out25/1
  slice24/1 -> reinterpret24/1
  reinterpret24/1 -> out24/1
  slice23/1 -> reinterpret23/1
  reinterpret23/1 -> out23/1
  slice22/1 -> reinterpret22/1
  reinterpret22/1 -> out22/1
  slice21/1 -> reinterpret21/1
  reinterpret21/1 -> out21/1
  slice20/1 -> reinterpret20/1
  reinterpret20/1 -> out20/1
  slice19/1 -> reinterpret19/1
  reinterpret19/1 -> out19/1
  slice18/1 -> reinterpret18/1
  reinterpret18/1 -> out18/1
  slice17/1 -> reinterpret17/1
  reinterpret17/1 -> out17/1
  slice16/1 -> reinterpret16/1
  reinterpret16/1 -> out16/1
  slice15/1 -> reinterpret15/1
  reinterpret15/1 -> out15/1
  slice14/1 -> reinterpret14/1
  reinterpret14/1 -> out14/1
  slice13/1 -> reinterpret13/1
  reinterpret13/1 -> out13/1
  slice12/1 -> reinterpret12/1
  reinterpret12/1 -> out12/1
  slice11/1 -> reinterpret11/1
  reinterpret11/1 -> out11/1
  slice10/1 -> reinterpret10/1
  reinterpret10/1 -> out10/1
  slice9/1 -> reinterpret9/1
  reinterpret9/1 -> out9/1
  slice8/1 -> reinterpret8/1
  reinterpret8/1 -> out8/1
  slice7/1 -> reinterpret7/1
  reinterpret7/1 -> out7/1
  slice6/1 -> reinterpret6/1
  reinterpret6/1 -> out6/1
  slice5/1 -> reinterpret5/1
  reinterpret5/1 -> out5/1
  slice4/1 -> reinterpret4/1
  reinterpret4/1 -> out4/1
  slice3/1 -> reinterpret3/1
  reinterpret3/1 -> out3/1
  slice2/1 -> reinterpret2/1
  reinterpret2/1 -> out2/1
  slice1/1 -> reinterpret1/1
  reinterpret1/1 -> lsb_out1/1

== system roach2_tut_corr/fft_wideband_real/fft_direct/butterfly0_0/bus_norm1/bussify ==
  in1 : Inport
  in2 : Inport  Port=2
  in3 : Inport  Port=3
  in4 : Inport  Port=4
  in5 : Inport  Port=5
  in6 : Inport  Port=6
  in7 : Inport  Port=7
  in8 : Inport  Port=8
  in9 : Inport  Port=9
  in10 : Inport  Port=10
  in11 : Inport  Port=11
  in12 : Inport  Port=12
  in13 : Inport  Port=13
  in14 : Inport  Port=14
  in15 : Inport  Port=15
  in16 : Inport  Port=16
  in17 : Inport  Port=17
  in18 : Inport  Port=18
  in19 : Inport  Port=19
  in20 : Inport  Port=20
  in21 : Inport  Port=21
  in22 : Inport  Port=22
  in23 : Inport  Port=23
  in24 : Inport  Port=24
  in25 : Inport  Port=25
  in26 : Inport  Port=26
  in27 : Inport  Port=27
  in28 : Inport  Port=28
  in29 : Inport  Port=29
  in30 : Inport  Port=30
  in31 : Inport  Port=31
  in32 : Inport  Port=32
  concatenate : xbsIndex_r4/Concat  num_inputs=32  dbl_ovrd=off  block_type=concat
  reinterpret{1..32} (32 alike) : xbsIndex_r4/Reinterpret  force_arith_type=on  arith_type=Unsigned  force_bin_pt=on  bin_pt=0  block_type=reinterpret
  bus_out : Outport
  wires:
  concatenate/1 -> bus_out/1
  in1/1 -> reinterpret1/1
  reinterpret1/1 -> concatenate/1
  in2/1 -> reinterpret2/1
  reinterpret2/1 -> concatenate/2
  in3/1 -> reinterpret3/1
  reinterpret3/1 -> concatenate/3
  in4/1 -> reinterpret4/1
  reinterpret4/1 -> concatenate/4
  in5/1 -> reinterpret5/1
  reinterpret5/1 -> concatenate/5
  in6/1 -> reinterpret6/1
  reinterpret6/1 -> concatenate/6
  in7/1 -> reinterpret7/1
  reinterpret7/1 -> concatenate/7
  in8/1 -> reinterpret8/1
  reinterpret8/1 -> concatenate/8
  in9/1 -> reinterpret9/1
  reinterpret9/1 -> concatenate/9
  in10/1 -> reinterpret10/1
  reinterpret10/1 -> concatenate/10
  in11/1 -> reinterpret11/1
  reinterpret11/1 -> concatenate/11
  in12/1 -> reinterpret12/1
  reinterpret12/1 -> concatenate/12
  in13/1 -> reinterpret13/1
  reinterpret13/1 -> concatenate/13
  in14/1 -> reinterpret14/1
  reinterpret14/1 -> concatenate/14
  in15/1 -> reinterpret15/1
  reinterpret15/1 -> concatenate/15
  in16/1 -> reinterpret16/1
  reinterpret16/1 -> concatenate/16
  in17/1 -> reinterpret17/1
  reinterpret17/1 -> concatenate/17
  in18/1 -> reinterpret18/1
  reinterpret18/1 -> concatenate/18
  in19/1 -> reinterpret19/1
  reinterpret19/1 -> concatenate/19
  in20/1 -> reinterpret20/1
  reinterpret20/1 -> concatenate/20
  in21/1 -> reinterpret21/1
  reinterpret21/1 -> concatenate/21
  in22/1 -> reinterpret22/1
  reinterpret22/1 -> concatenate/22
  in23/1 -> reinterpret23/1
  reinterpret23/1 -> concatenate/23
  in24/1 -> reinterpret24/1
  reinterpret24/1 -> concatenate/24
  in25/1 -> reinterpret25/1
  reinterpret25/1 -> concatenate/25
  in26/1 -> reinterpret26/1
  reinterpret26/1 -> concatenate/26
  in27/1 -> reinterpret27/1
  reinterpret27/1 -> concatenate/27
  in28/1 -> reinterpret28/1
  reinterpret28/1 -> concatenate/28
  in29/1 -> reinterpret29/1
  reinterpret29/1 -> concatenate/29
  in30/1 -> reinterpret30/1
  reinterpret30/1 -> concatenate/30
  in31/1 -> reinterpret31/1
  reinterpret31/1 -> concatenate/31
  in32/1 -> reinterpret32/1
  reinterpret32/1 -> concatenate/32

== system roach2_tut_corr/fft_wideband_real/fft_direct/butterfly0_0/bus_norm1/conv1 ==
  note: (ones_bit & 1) -> round-to-even (ones_bit ^ 1) -> round-to-odd (sign_bit & 1)-> round-to-zero (sign_bit ^ 1) -> round-to-inf (X ~| 1) -> round half down (X | 1) -> round half up
  in : Inport
  Concat : xbsIndex_r4/Concat  num_inputs=2  dbl_ovrd=off  block_type=concat
  Constant : xbsIndex_r4/Constant  const=1  gui_display_data_type=Fixed-point  arith_type=Unsigned  n_bits=1  bin_pt=0  preci_type=Single  exp_width=8  frac_width=24  explicit_period=off  period=1  equ=P=C  opselect=C  inp2=PCIN>>17  opr=+  inp1=P  carry=CIN  dbl_ovrd=off  block_type=constant
  Reinterpret : xbsIndex_r4/Reinterpret  force_arith_type=on  arith_type=Unsigned  force_bin_pt=on  bin_pt=0  block_type=reinterpret
  adder : xbsIndex_r4/AddSub  mode=Addition  use_carryin=off  use_carryout=off  en=off  latency=0  precision=User Defined  arith_type="Signed  (2's comp)"  n_bits=21  bin_pt=18  quantization=Truncate  overflow=Wrap  dbl_ovrd=off  use_behavioral_HDL=off  hw_selection=Fabric  pipelined=on  use_rpm=on  block_type=addsub
  almost_half : xbsIndex_r4/Constant  const=0  gui_display_data_type=Fixed-point  arith_type=Unsigned  n_bits=19  bin_pt=0  preci_type=Single  exp_width=8  frac_width=24  explicit_period=off  period=1  equ=P=C  opselect=C  inp2=PCIN>>17  opr=+  inp1=P  carry=CIN  dbl_ovrd=off  block_type=constant
  bit : xbsIndex_r4/Slice  nbits=1  boolean_output=off  mode=Lower Bit Location + Width  bit1=0  base1=MSB of Input  bit0=0  base0=LSB of Input  dbl_ovrd=off  block_type=slice
  force1 : xbsIndex_r4/Reinterpret  force_arith_type=on  arith_type="Signed  (2's comp)"  force_bin_pt=on  bin_pt=19  block_type=reinterpret
  force2 : xbsIndex_r4/Reinterpret  force_arith_type=off  arith_type="Signed  (2's comp)"  force_bin_pt=on  bin_pt=19  block_type=reinterpret
  tweak_op : xbsIndex_r4/Logical  logical_function=NOR  inputs=2  en=off  latency=0  precision=Full  arith_type=Unsigned  n_bits=8  bin_pt=2  align_bp=on  dbl_ovrd=off  block_type=logical
  out : Outport
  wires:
  tweak_op/1 -> Concat/2
  Constant/1 -> tweak_op/2
  bit/1 -> tweak_op/1
  almost_half/1 -> force2/1
  in/1 -> Reinterpret/1, bit/1
  Concat/1 -> force1/1
  Reinterpret/1 -> Concat/1
  force1/1 -> adder/1
  force2/1 -> adder/2
  adder/1 -> out/1

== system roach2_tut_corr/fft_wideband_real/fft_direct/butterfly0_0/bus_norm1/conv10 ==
  note: (ones_bit & 1) -> round-to-even (ones_bit ^ 1) -> round-to-odd (sign_bit & 1)-> round-to-zero (sign_bit ^ 1) -> round-to-inf (X ~| 1) -> round half down (X | 1) -> round half up
  in : Inport
  Concat : xbsIndex_r4/Concat  num_inputs=2  dbl_ovrd=off  block_type=concat
  Constant : xbsIndex_r4/Constant  const=1  gui_display_data_type=Fixed-point  arith_type=Unsigned  n_bits=1  bin_pt=0  preci_type=Single  exp_width=8  frac_width=24  explicit_period=off  period=1  equ=P=C  opselect=C  inp2=PCIN>>17  opr=+  inp1=P  carry=CIN  dbl_ovrd=off  block_type=constant
  Reinterpret : xbsIndex_r4/Reinterpret  force_arith_type=on  arith_type=Unsigned  force_bin_pt=on  bin_pt=0  block_type=reinterpret
  adder : xbsIndex_r4/AddSub  mode=Addition  use_carryin=off  use_carryout=off  en=off  latency=0  precision=User Defined  arith_type="Signed  (2's comp)"  n_bits=21  bin_pt=18  quantization=Truncate  overflow=Wrap  dbl_ovrd=off  use_behavioral_HDL=off  hw_selection=Fabric  pipelined=on  use_rpm=on  block_type=addsub
  almost_half : xbsIndex_r4/Constant  const=0  gui_display_data_type=Fixed-point  arith_type=Unsigned  n_bits=19  bin_pt=0  preci_type=Single  exp_width=8  frac_width=24  explicit_period=off  period=1  equ=P=C  opselect=C  inp2=PCIN>>17  opr=+  inp1=P  carry=CIN  dbl_ovrd=off  block_type=constant
  bit : xbsIndex_r4/Slice  nbits=1  boolean_output=off  mode=Lower Bit Location + Width  bit1=0  base1=MSB of Input  bit0=0  base0=LSB of Input  dbl_ovrd=off  block_type=slice
  force1 : xbsIndex_r4/Reinterpret  force_arith_type=on  arith_type="Signed  (2's comp)"  force_bin_pt=on  bin_pt=19  block_type=reinterpret
  force2 : xbsIndex_r4/Reinterpret  force_arith_type=off  arith_type="Signed  (2's comp)"  force_bin_pt=on  bin_pt=19  block_type=reinterpret
  tweak_op : xbsIndex_r4/Logical  logical_function=NOR  inputs=2  en=off  latency=0  precision=Full  arith_type=Unsigned  n_bits=8  bin_pt=2  align_bp=on  dbl_ovrd=off  block_type=logical
  out : Outport
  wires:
  tweak_op/1 -> Concat/2
  Constant/1 -> tweak_op/2
  bit/1 -> tweak_op/1
  almost_half/1 -> force2/1
  in/1 -> Reinterpret/1, bit/1
  Concat/1 -> force1/1
  Reinterpret/1 -> Concat/1
  force1/1 -> adder/1
  force2/1 -> adder/2
  adder/1 -> out/1

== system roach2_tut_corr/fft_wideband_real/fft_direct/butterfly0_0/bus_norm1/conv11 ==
  note: (ones_bit & 1) -> round-to-even (ones_bit ^ 1) -> round-to-odd (sign_bit & 1)-> round-to-zero (sign_bit ^ 1) -> round-to-inf (X ~| 1) -> round half down (X | 1) -> round half up
  in : Inport
  Concat : xbsIndex_r4/Concat  num_inputs=2  dbl_ovrd=off  block_type=concat
  Constant : xbsIndex_r4/Constant  const=1  gui_display_data_type=Fixed-point  arith_type=Unsigned  n_bits=1  bin_pt=0  preci_type=Single  exp_width=8  frac_width=24  explicit_period=off  period=1  equ=P=C  opselect=C  inp2=PCIN>>17  opr=+  inp1=P  carry=CIN  dbl_ovrd=off  block_type=constant
  Reinterpret : xbsIndex_r4/Reinterpret  force_arith_type=on  arith_type=Unsigned  force_bin_pt=on  bin_pt=0  block_type=reinterpret
  adder : xbsIndex_r4/AddSub  mode=Addition  use_carryin=off  use_carryout=off  en=off  latency=0  precision=User Defined  arith_type="Signed  (2's comp)"  n_bits=21  bin_pt=18  quantization=Truncate  overflow=Wrap  dbl_ovrd=off  use_behavioral_HDL=off  hw_selection=Fabric  pipelined=on  use_rpm=on  block_type=addsub
  almost_half : xbsIndex_r4/Constant  const=0  gui_display_data_type=Fixed-point  arith_type=Unsigned  n_bits=19  bin_pt=0  preci_type=Single  exp_width=8  frac_width=24  explicit_period=off  period=1  equ=P=C  opselect=C  inp2=PCIN>>17  opr=+  inp1=P  carry=CIN  dbl_ovrd=off  block_type=constant
  bit : xbsIndex_r4/Slice  nbits=1  boolean_output=off  mode=Lower Bit Location + Width  bit1=0  base1=MSB of Input  bit0=0  base0=LSB of Input  dbl_ovrd=off  block_type=slice
  force1 : xbsIndex_r4/Reinterpret  force_arith_type=on  arith_type="Signed  (2's comp)"  force_bin_pt=on  bin_pt=19  block_type=reinterpret
  force2 : xbsIndex_r4/Reinterpret  force_arith_type=off  arith_type="Signed  (2's comp)"  force_bin_pt=on  bin_pt=19  block_type=reinterpret
  tweak_op : xbsIndex_r4/Logical  logical_function=NOR  inputs=2  en=off  latency=0  precision=Full  arith_type=Unsigned  n_bits=8  bin_pt=2  align_bp=on  dbl_ovrd=off  block_type=logical
  out : Outport
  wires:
  tweak_op/1 -> Concat/2
  Constant/1 -> tweak_op/2
  bit/1 -> tweak_op/1
  almost_half/1 -> force2/1
  in/1 -> Reinterpret/1, bit/1
  Concat/1 -> force1/1
  Reinterpret/1 -> Concat/1
  force1/1 -> adder/1
  force2/1 -> adder/2
  adder/1 -> out/1

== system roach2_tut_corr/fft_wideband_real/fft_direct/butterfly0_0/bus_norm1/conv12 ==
  note: (ones_bit & 1) -> round-to-even (ones_bit ^ 1) -> round-to-odd (sign_bit & 1)-> round-to-zero (sign_bit ^ 1) -> round-to-inf (X ~| 1) -> round half down (X | 1) -> round half up
  in : Inport
  Concat : xbsIndex_r4/Concat  num_inputs=2  dbl_ovrd=off  block_type=concat
  Constant : xbsIndex_r4/Constant  const=1  gui_display_data_type=Fixed-point  arith_type=Unsigned  n_bits=1  bin_pt=0  preci_type=Single  exp_width=8  frac_width=24  explicit_period=off  period=1  equ=P=C  opselect=C  inp2=PCIN>>17  opr=+  inp1=P  carry=CIN  dbl_ovrd=off  block_type=constant
  Reinterpret : xbsIndex_r4/Reinterpret  force_arith_type=on  arith_type=Unsigned  force_bin_pt=on  bin_pt=0  block_type=reinterpret
  adder : xbsIndex_r4/AddSub  mode=Addition  use_carryin=off  use_carryout=off  en=off  latency=0  precision=User Defined  arith_type="Signed  (2's comp)"  n_bits=21  bin_pt=18  quantization=Truncate  overflow=Wrap  dbl_ovrd=off  use_behavioral_HDL=off  hw_selection=Fabric  pipelined=on  use_rpm=on  block_type=addsub
  almost_half : xbsIndex_r4/Constant  const=0  gui_display_data_type=Fixed-point  arith_type=Unsigned  n_bits=19  bin_pt=0  preci_type=Single  exp_width=8  frac_width=24  explicit_period=off  period=1  equ=P=C  opselect=C  inp2=PCIN>>17  opr=+  inp1=P  carry=CIN  dbl_ovrd=off  block_type=constant
  bit : xbsIndex_r4/Slice  nbits=1  boolean_output=off  mode=Lower Bit Location + Width  bit1=0  base1=MSB of Input  bit0=0  base0=LSB of Input  dbl_ovrd=off  block_type=slice
  force1 : xbsIndex_r4/Reinterpret  force_arith_type=on  arith_type="Signed  (2's comp)"  force_bin_pt=on  bin_pt=19  block_type=reinterpret
  force2 : xbsIndex_r4/Reinterpret  force_arith_type=off  arith_type="Signed  (2's comp)"  force_bin_pt=on  bin_pt=19  block_type=reinterpret
  tweak_op : xbsIndex_r4/Logical  logical_function=NOR  inputs=2  en=off  latency=0  precision=Full  arith_type=Unsigned  n_bits=8  bin_pt=2  align_bp=on  dbl_ovrd=off  block_type=logical
  out : Outport
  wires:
  tweak_op/1 -> Concat/2
  Constant/1 -> tweak_op/2
  bit/1 -> tweak_op/1
  almost_half/1 -> force2/1
  in/1 -> Reinterpret/1, bit/1
  Concat/1 -> force1/1
  Reinterpret/1 -> Concat/1
  force1/1 -> adder/1
  force2/1 -> adder/2
  adder/1 -> out/1

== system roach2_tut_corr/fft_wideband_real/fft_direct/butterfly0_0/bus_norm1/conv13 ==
  note: (ones_bit & 1) -> round-to-even (ones_bit ^ 1) -> round-to-odd (sign_bit & 1)-> round-to-zero (sign_bit ^ 1) -> round-to-inf (X ~| 1) -> round half down (X | 1) -> round half up
  in : Inport
  Concat : xbsIndex_r4/Concat  num_inputs=2  dbl_ovrd=off  block_type=concat
  Constant : xbsIndex_r4/Constant  const=1  gui_display_data_type=Fixed-point  arith_type=Unsigned  n_bits=1  bin_pt=0  preci_type=Single  exp_width=8  frac_width=24  explicit_period=off  period=1  equ=P=C  opselect=C  inp2=PCIN>>17  opr=+  inp1=P  carry=CIN  dbl_ovrd=off  block_type=constant
  Reinterpret : xbsIndex_r4/Reinterpret  force_arith_type=on  arith_type=Unsigned  force_bin_pt=on  bin_pt=0  block_type=reinterpret
  adder : xbsIndex_r4/AddSub  mode=Addition  use_carryin=off  use_carryout=off  en=off  latency=0  precision=User Defined  arith_type="Signed  (2's comp)"  n_bits=21  bin_pt=18  quantization=Truncate  overflow=Wrap  dbl_ovrd=off  use_behavioral_HDL=off  hw_selection=Fabric  pipelined=on  use_rpm=on  block_type=addsub
  almost_half : xbsIndex_r4/Constant  const=0  gui_display_data_type=Fixed-point  arith_type=Unsigned  n_bits=19  bin_pt=0  preci_type=Single  exp_width=8  frac_width=24  explicit_period=off  period=1  equ=P=C  opselect=C  inp2=PCIN>>17  opr=+  inp1=P  carry=CIN  dbl_ovrd=off  block_type=constant
  bit : xbsIndex_r4/Slice  nbits=1  boolean_output=off  mode=Lower Bit Location + Width  bit1=0  base1=MSB of Input  bit0=0  base0=LSB of Input  dbl_ovrd=off  block_type=slice
  force1 : xbsIndex_r4/Reinterpret  force_arith_type=on  arith_type="Signed  (2's comp)"  force_bin_pt=on  bin_pt=19  block_type=reinterpret
  force2 : xbsIndex_r4/Reinterpret  force_arith_type=off  arith_type="Signed  (2's comp)"  force_bin_pt=on  bin_pt=19  block_type=reinterpret
  tweak_op : xbsIndex_r4/Logical  logical_function=NOR  inputs=2  en=off  latency=0  precision=Full  arith_type=Unsigned  n_bits=8  bin_pt=2  align_bp=on  dbl_ovrd=off  block_type=logical
  out : Outport
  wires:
  tweak_op/1 -> Concat/2
  Constant/1 -> tweak_op/2
  bit/1 -> tweak_op/1
  almost_half/1 -> force2/1
  in/1 -> Reinterpret/1, bit/1
  Concat/1 -> force1/1
  Reinterpret/1 -> Concat/1
  force1/1 -> adder/1
  force2/1 -> adder/2
  adder/1 -> out/1

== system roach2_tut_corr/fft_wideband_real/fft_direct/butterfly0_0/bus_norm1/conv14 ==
  note: (ones_bit & 1) -> round-to-even (ones_bit ^ 1) -> round-to-odd (sign_bit & 1)-> round-to-zero (sign_bit ^ 1) -> round-to-inf (X ~| 1) -> round half down (X | 1) -> round half up
  in : Inport
  Concat : xbsIndex_r4/Concat  num_inputs=2  dbl_ovrd=off  block_type=concat
  Constant : xbsIndex_r4/Constant  const=1  gui_display_data_type=Fixed-point  arith_type=Unsigned  n_bits=1  bin_pt=0  preci_type=Single  exp_width=8  frac_width=24  explicit_period=off  period=1  equ=P=C  opselect=C  inp2=PCIN>>17  opr=+  inp1=P  carry=CIN  dbl_ovrd=off  block_type=constant
  Reinterpret : xbsIndex_r4/Reinterpret  force_arith_type=on  arith_type=Unsigned  force_bin_pt=on  bin_pt=0  block_type=reinterpret
  adder : xbsIndex_r4/AddSub  mode=Addition  use_carryin=off  use_carryout=off  en=off  latency=0  precision=User Defined  arith_type="Signed  (2's comp)"  n_bits=21  bin_pt=18  quantization=Truncate  overflow=Wrap  dbl_ovrd=off  use_behavioral_HDL=off  hw_selection=Fabric  pipelined=on  use_rpm=on  block_type=addsub
  almost_half : xbsIndex_r4/Constant  const=0  gui_display_data_type=Fixed-point  arith_type=Unsigned  n_bits=19  bin_pt=0  preci_type=Single  exp_width=8  frac_width=24  explicit_period=off  period=1  equ=P=C  opselect=C  inp2=PCIN>>17  opr=+  inp1=P  carry=CIN  dbl_ovrd=off  block_type=constant
  bit : xbsIndex_r4/Slice  nbits=1  boolean_output=off  mode=Lower Bit Location + Width  bit1=0  base1=MSB of Input  bit0=0  base0=LSB of Input  dbl_ovrd=off  block_type=slice
  force1 : xbsIndex_r4/Reinterpret  force_arith_type=on  arith_type="Signed  (2's comp)"  force_bin_pt=on  bin_pt=19  block_type=reinterpret
  force2 : xbsIndex_r4/Reinterpret  force_arith_type=off  arith_type="Signed  (2's comp)"  force_bin_pt=on  bin_pt=19  block_type=reinterpret
  tweak_op : xbsIndex_r4/Logical  logical_function=NOR  inputs=2  en=off  latency=0  precision=Full  arith_type=Unsigned  n_bits=8  bin_pt=2  align_bp=on  dbl_ovrd=off  block_type=logical
  out : Outport
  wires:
  tweak_op/1 -> Concat/2
  Constant/1 -> tweak_op/2
  bit/1 -> tweak_op/1
  almost_half/1 -> force2/1
  in/1 -> Reinterpret/1, bit/1
  Concat/1 -> force1/1
  Reinterpret/1 -> Concat/1
  force1/1 -> adder/1
  force2/1 -> adder/2
  adder/1 -> out/1

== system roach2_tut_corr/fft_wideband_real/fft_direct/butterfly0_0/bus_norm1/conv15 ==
  note: (ones_bit & 1) -> round-to-even (ones_bit ^ 1) -> round-to-odd (sign_bit & 1)-> round-to-zero (sign_bit ^ 1) -> round-to-inf (X ~| 1) -> round half down (X | 1) -> round half up
  in : Inport
  Concat : xbsIndex_r4/Concat  num_inputs=2  dbl_ovrd=off  block_type=concat
  Constant : xbsIndex_r4/Constant  const=1  gui_display_data_type=Fixed-point  arith_type=Unsigned  n_bits=1  bin_pt=0  preci_type=Single  exp_width=8  frac_width=24  explicit_period=off  period=1  equ=P=C  opselect=C  inp2=PCIN>>17  opr=+  inp1=P  carry=CIN  dbl_ovrd=off  block_type=constant
  Reinterpret : xbsIndex_r4/Reinterpret  force_arith_type=on  arith_type=Unsigned  force_bin_pt=on  bin_pt=0  block_type=reinterpret
  adder : xbsIndex_r4/AddSub  mode=Addition  use_carryin=off  use_carryout=off  en=off  latency=0  precision=User Defined  arith_type="Signed  (2's comp)"  n_bits=21  bin_pt=18  quantization=Truncate  overflow=Wrap  dbl_ovrd=off  use_behavioral_HDL=off  hw_selection=Fabric  pipelined=on  use_rpm=on  block_type=addsub
  almost_half : xbsIndex_r4/Constant  const=0  gui_display_data_type=Fixed-point  arith_type=Unsigned  n_bits=19  bin_pt=0  preci_type=Single  exp_width=8  frac_width=24  explicit_period=off  period=1  equ=P=C  opselect=C  inp2=PCIN>>17  opr=+  inp1=P  carry=CIN  dbl_ovrd=off  block_type=constant
  bit : xbsIndex_r4/Slice  nbits=1  boolean_output=off  mode=Lower Bit Location + Width  bit1=0  base1=MSB of Input  bit0=0  base0=LSB of Input  dbl_ovrd=off  block_type=slice
  force1 : xbsIndex_r4/Reinterpret  force_arith_type=on  arith_type="Signed  (2's comp)"  force_bin_pt=on  bin_pt=19  block_type=reinterpret
  force2 : xbsIndex_r4/Reinterpret  force_arith_type=off  arith_type="Signed  (2's comp)"  force_bin_pt=on  bin_pt=19  block_type=reinterpret
  tweak_op : xbsIndex_r4/Logical  logical_function=NOR  inputs=2  en=off  latency=0  precision=Full  arith_type=Unsigned  n_bits=8  bin_pt=2  align_bp=on  dbl_ovrd=off  block_type=logical
  out : Outport
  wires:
  tweak_op/1 -> Concat/2
  Constant/1 -> tweak_op/2
  bit/1 -> tweak_op/1
  almost_half/1 -> force2/1
  in/1 -> Reinterpret/1, bit/1
  Concat/1 -> force1/1
  Reinterpret/1 -> Concat/1
  force1/1 -> adder/1
  force2/1 -> adder/2
  adder/1 -> out/1

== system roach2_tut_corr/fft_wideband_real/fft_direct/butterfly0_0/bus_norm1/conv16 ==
  note: (ones_bit & 1) -> round-to-even (ones_bit ^ 1) -> round-to-odd (sign_bit & 1)-> round-to-zero (sign_bit ^ 1) -> round-to-inf (X ~| 1) -> round half down (X | 1) -> round half up
  in : Inport
  Concat : xbsIndex_r4/Concat  num_inputs=2  dbl_ovrd=off  block_type=concat
  Constant : xbsIndex_r4/Constant  const=1  gui_display_data_type=Fixed-point  arith_type=Unsigned  n_bits=1  bin_pt=0  preci_type=Single  exp_width=8  frac_width=24  explicit_period=off  period=1  equ=P=C  opselect=C  inp2=PCIN>>17  opr=+  inp1=P  carry=CIN  dbl_ovrd=off  block_type=constant
  Reinterpret : xbsIndex_r4/Reinterpret  force_arith_type=on  arith_type=Unsigned  force_bin_pt=on  bin_pt=0  block_type=reinterpret
  adder : xbsIndex_r4/AddSub  mode=Addition  use_carryin=off  use_carryout=off  en=off  latency=0  precision=User Defined  arith_type="Signed  (2's comp)"  n_bits=21  bin_pt=18  quantization=Truncate  overflow=Wrap  dbl_ovrd=off  use_behavioral_HDL=off  hw_selection=Fabric  pipelined=on  use_rpm=on  block_type=addsub
  almost_half : xbsIndex_r4/Constant  const=0  gui_display_data_type=Fixed-point  arith_type=Unsigned  n_bits=19  bin_pt=0  preci_type=Single  exp_width=8  frac_width=24  explicit_period=off  period=1  equ=P=C  opselect=C  inp2=PCIN>>17  opr=+  inp1=P  carry=CIN  dbl_ovrd=off  block_type=constant
  bit : xbsIndex_r4/Slice  nbits=1  boolean_output=off  mode=Lower Bit Location + Width  bit1=0  base1=MSB of Input  bit0=0  base0=LSB of Input  dbl_ovrd=off  block_type=slice
  force1 : xbsIndex_r4/Reinterpret  force_arith_type=on  arith_type="Signed  (2's comp)"  force_bin_pt=on  bin_pt=19  block_type=reinterpret
  force2 : xbsIndex_r4/Reinterpret  force_arith_type=off  arith_type="Signed  (2's comp)"  force_bin_pt=on  bin_pt=19  block_type=reinterpret
  tweak_op : xbsIndex_r4/Logical  logical_function=NOR  inputs=2  en=off  latency=0  precision=Full  arith_type=Unsigned  n_bits=8  bin_pt=2  align_bp=on  dbl_ovrd=off  block_type=logical
  out : Outport
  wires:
  tweak_op/1 -> Concat/2
  Constant/1 -> tweak_op/2
  bit/1 -> tweak_op/1
  almost_half/1 -> force2/1
  in/1 -> Reinterpret/1, bit/1
  Concat/1 -> force1/1
  Reinterpret/1 -> Concat/1
  force1/1 -> adder/1
  force2/1 -> adder/2
  adder/1 -> out/1

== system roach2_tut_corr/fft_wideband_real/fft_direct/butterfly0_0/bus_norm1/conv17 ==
  note: (ones_bit & 1) -> round-to-even (ones_bit ^ 1) -> round-to-odd (sign_bit & 1)-> round-to-zero (sign_bit ^ 1) -> round-to-inf (X ~| 1) -> round half down (X | 1) -> round half up
  in : Inport
  Concat : xbsIndex_r4/Concat  num_inputs=2  dbl_ovrd=off  block_type=concat
  Constant : xbsIndex_r4/Constant  const=1  gui_display_data_type=Fixed-point  arith_type=Unsigned  n_bits=1  bin_pt=0  preci_type=Single  exp_width=8  frac_width=24  explicit_period=off  period=1  equ=P=C  opselect=C  inp2=PCIN>>17  opr=+  inp1=P  carry=CIN  dbl_ovrd=off  block_type=constant
  Reinterpret : xbsIndex_r4/Reinterpret  force_arith_type=on  arith_type=Unsigned  force_bin_pt=on  bin_pt=0  block_type=reinterpret
  adder : xbsIndex_r4/AddSub  mode=Addition  use_carryin=off  use_carryout=off  en=off  latency=0  precision=User Defined  arith_type="Signed  (2's comp)"  n_bits=21  bin_pt=18  quantization=Truncate  overflow=Wrap  dbl_ovrd=off  use_behavioral_HDL=off  hw_selection=Fabric  pipelined=on  use_rpm=on  block_type=addsub
  almost_half : xbsIndex_r4/Constant  const=0  gui_display_data_type=Fixed-point  arith_type=Unsigned  n_bits=19  bin_pt=0  preci_type=Single  exp_width=8  frac_width=24  explicit_period=off  period=1  equ=P=C  opselect=C  inp2=PCIN>>17  opr=+  inp1=P  carry=CIN  dbl_ovrd=off  block_type=constant
  bit : xbsIndex_r4/Slice  nbits=1  boolean_output=off  mode=Lower Bit Location + Width  bit1=0  base1=MSB of Input  bit0=0  base0=LSB of Input  dbl_ovrd=off  block_type=slice
  force1 : xbsIndex_r4/Reinterpret  force_arith_type=on  arith_type="Signed  (2's comp)"  force_bin_pt=on  bin_pt=19  block_type=reinterpret
  force2 : xbsIndex_r4/Reinterpret  force_arith_type=off  arith_type="Signed  (2's comp)"  force_bin_pt=on  bin_pt=19  block_type=reinterpret
  tweak_op : xbsIndex_r4/Logical  logical_function=NOR  inputs=2  en=off  latency=0  precision=Full  arith_type=Unsigned  n_bits=8  bin_pt=2  align_bp=on  dbl_ovrd=off  block_type=logical
  out : Outport
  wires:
  tweak_op/1 -> Concat/2
  Constant/1 -> tweak_op/2
  bit/1 -> tweak_op/1
  almost_half/1 -> force2/1
  in/1 -> Reinterpret/1, bit/1
  Concat/1 -> force1/1
  Reinterpret/1 -> Concat/1
  force1/1 -> adder/1
  force2/1 -> adder/2
  adder/1 -> out/1
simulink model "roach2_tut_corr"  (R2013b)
settings: Solver=VariableStepDiscrete  SolverMode=SingleTasking  StartTime=0.0  StopTime=100  RelTol=1e-3
undefined symbols (not defined in the file): add_latency, addr_width, Bit, bitfield, BitWidth, bram_latency, burst_size, casper_library_scopes, conv_latency, data_width, DelayLen, fan_latency, FFTSize, FFTStage, getfield, increment, led, Location, Lower, mult_latency, mux_latency, n_bits, n_bits_data, n_inputs, n_streams, n_taps, neg_latency, negate_latency, nsamples, pfb_size, pulse_len, reset_period, ROACH, ROACH2, snapshot, sx475t, sync_period, sync_period_bits, Upper, UseCounter, Width
libraries: xbsIndex_r4 x24444, casper_library_misc x73, xbsReplacements_r4 x34, casper_library_delays x14, xps_library x7
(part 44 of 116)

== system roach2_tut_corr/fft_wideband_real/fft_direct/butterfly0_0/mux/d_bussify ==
  in1 : Inport
  in2 : Inport  Port=2
  in3 : Inport  Port=3
  in4 : Inport  Port=4
  in5 : Inport  Port=5
  in6 : Inport  Port=6
  in7 : Inport  Port=7
  in8 : Inport  Port=8
  in9 : Inport  Port=9
  in10 : Inport  Port=10
  in11 : Inport  Port=11
  in12 : Inport  Port=12
  in13 : Inport  Port=13
  in14 : Inport  Port=14
  in15 : Inport  Port=15
  in16 : Inport  Port=16
  in17 : Inport  Port=17
  in18 : Inport  Port=18
  in19 : Inport  Port=19
  in20 : Inport  Port=20
  in21 : Inport  Port=21
  in22 : Inport  Port=22
  in23 : Inport  Port=23
  in24 : Inport  Port=24
  in25 : Inport  Port=25
  in26 : Inport  Port=26
  in27 : Inport  Port=27
  in28 : Inport  Port=28
  in29 : Inport  Port=29
  in30 : Inport  Port=30
  in31 : Inport  Port=31
  in32 : Inport  Port=32
  concatenate : xbsIndex_r4/Concat  num_inputs=32  dbl_ovrd=off  block_type=concat
  reinterpret{1..32} (32 alike) : xbsIndex_r4/Reinterpret  force_arith_type=on  arith_type=Unsigned  force_bin_pt=on  bin_pt=0  block_type=reinterpret
  bus_out : Outport
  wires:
  concatenate/1 -> bus_out/1
  in1/1 -> reinterpret1/1
  reinterpret1/1 -> concatenate/1
  in2/1 -> reinterpret2/1
  reinterpret2/1 -> concatenate/2
  in3/1 -> reinterpret3/1
  reinterpret3/1 -> concatenate/3
  in4/1 -> reinterpret4/1
  reinterpret4/1 -> concatenate/4
  in5/1 -> reinterpret5/1
  reinterpret5/1 -> concatenate/5
  in6/1 -> reinterpret6/1
  reinterpret6/1 -> concatenate/6
  in7/1 -> reinterpret7/1
  reinterpret7/1 -> concatenate/7
  in8/1 -> reinterpret8/1
  reinterpret8/1 -> concatenate/8
  in9/1 -> reinterpret9/1
  reinterpret9/1 -> concatenate/9
  in10/1 -> reinterpret10/1
  reinterpret10/1 -> concatenate/10
  in11/1 -> reinterpret11/1
  reinterpret11/1 -> concatenate/11
  in12/1 -> reinterpret12/1
  reinterpret12/1 -> concatenate/12
  in13/1 -> reinterpret13/1
  reinterpret13/1 -> concatenate/13
  in14/1 -> reinterpret14/1
  reinterpret14/1 -> concatenate/14
  in15/1 -> reinterpret15/1
  reinterpret15/1 -> concatenate/15
  in16/1 -> reinterpret16/1
  reinterpret16/1 -> concatenate/16
  in17/1 -> reinterpret17/1
  reinterpret17/1 -> concatenate/17
  in18/1 -> reinterpret18/1
  reinterpret18/1 -> concatenate/18
  in19/1 -> reinterpret19/1
  reinterpret19/1 -> concatenate/19
  in20/1 -> reinterpret20/1
  reinterpret20/1 -> concatenate/20
  in21/1 -> reinterpret21/1
  reinterpret21/1 -> concatenate/21
  in22/1 -> reinterpret22/1
  reinterpret22/1 -> concatenate/22
  in23/1 -> reinterpret23/1
  reinterpret23/1 -> concatenate/23
  in24/1 -> reinterpret24/1
  reinterpret24/1 -> concatenate/24
  in25/1 -> reinterpret25/1
  reinterpret25/1 -> concatenate/25
  in26/1 -> reinterpret26/1
  reinterpret26/1 -> concatenate/26
  in27/1 -> reinterpret27/1
  reinterpret27/1 -> concatenate/27
  in28/1 -> reinterpret28/1
  reinterpret28/1 -> concatenate/28
  in29/1 -> reinterpret29/1
  reinterpret29/1 -> concatenate/29
  in30/1 -> reinterpret30/1
  reinterpret30/1 -> concatenate/30
  in31/1 -> reinterpret31/1
  reinterpret31/1 -> concatenate/31
  in32/1 -> reinterpret32/1
  reinterpret32/1 -> concatenate/32

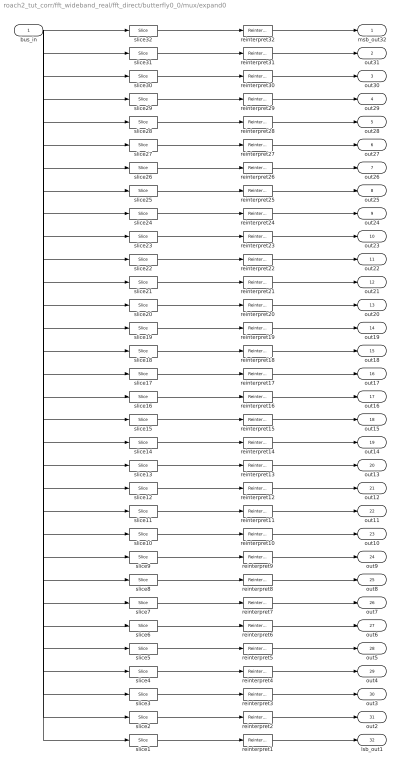
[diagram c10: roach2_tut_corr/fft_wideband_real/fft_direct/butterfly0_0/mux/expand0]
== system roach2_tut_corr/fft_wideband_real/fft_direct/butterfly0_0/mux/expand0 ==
  bus_in : Inport
  reinterpret{1..32} (32 alike) : xbsIndex_r4/Reinterpret  force_arith_type=on  arith_type=Unsigned  force_bin_pt=on  bin_pt=0  block_type=reinterpret
  slice1 : xbsIndex_r4/Slice  nbits=21  boolean_output=off  mode=Upper Bit Location + Width  bit1=-651  base1=MSB of Input  bit0=0  base0=LSB of Input  dbl_ovrd=off  block_type=slice
  slice10 : xbsIndex_r4/Slice  nbits=21  boolean_output=off  mode=Upper Bit Location + Width  bit1=-462  base1=MSB of Input  bit0=0  base0=LSB of Input  dbl_ovrd=off  block_type=slice
  slice11 : xbsIndex_r4/Slice  nbits=21  boolean_output=off  mode=Upper Bit Location + Width  bit1=-441  base1=MSB of Input  bit0=0  base0=LSB of Input  dbl_ovrd=off  block_type=slice
  slice12 : xbsIndex_r4/Slice  nbits=21  boolean_output=off  mode=Upper Bit Location + Width  bit1=-420  base1=MSB of Input  bit0=0  base0=LSB of Input  dbl_ovrd=off  block_type=slice
  slice13 : xbsIndex_r4/Slice  nbits=21  boolean_output=off  mode=Upper Bit Location + Width  bit1=-399  base1=MSB of Input  bit0=0  base0=LSB of Input  dbl_ovrd=off  block_type=slice
  slice14 : xbsIndex_r4/Slice  nbits=21  boolean_output=off  mode=Upper Bit Location + Width  bit1=-378  base1=MSB of Input  bit0=0  base0=LSB of Input  dbl_ovrd=off  block_type=slice
  slice15 : xbsIndex_r4/Slice  nbits=21  boolean_output=off  mode=Upper Bit Location + Width  bit1=-357  base1=MSB of Input  bit0=0  base0=LSB of Input  dbl_ovrd=off  block_type=slice
  slice16 : xbsIndex_r4/Slice  nbits=21  boolean_output=off  mode=Upper Bit Location + Width  bit1=-336  base1=MSB of Input  bit0=0  base0=LSB of Input  dbl_ovrd=off  block_type=slice
  slice17 : xbsIndex_r4/Slice  nbits=21  boolean_output=off  mode=Upper Bit Location + Width  bit1=-315  base1=MSB of Input  bit0=0  base0=LSB of Input  dbl_ovrd=off  block_type=slice
  slice18 : xbsIndex_r4/Slice  nbits=21  boolean_output=off  mode=Upper Bit Location + Width  bit1=-294  base1=MSB of Input  bit0=0  base0=LSB of Input  dbl_ovrd=off  block_type=slice
  slice19 : xbsIndex_r4/Slice  nbits=21  boolean_output=off  mode=Upper Bit Location + Width  bit1=-273  base1=MSB of Input  bit0=0  base0=LSB of Input  dbl_ovrd=off  block_type=slice
  slice2 : xbsIndex_r4/Slice  nbits=21  boolean_output=off  mode=Upper Bit Location + Width  bit1=-630  base1=MSB of Input  bit0=0  base0=LSB of Input  dbl_ovrd=off  block_type=slice
  slice20 : xbsIndex_r4/Slice  nbits=21  boolean_output=off  mode=Upper Bit Location + Width  bit1=-252  base1=MSB of Input  bit0=0  base0=LSB of Input  dbl_ovrd=off  block_type=slice
  slice21 : xbsIndex_r4/Slice  nbits=21  boolean_output=off  mode=Upper Bit Location + Width  bit1=-231  base1=MSB of Input  bit0=0  base0=LSB of Input  dbl_ovrd=off  block_type=slice
  slice22 : xbsIndex_r4/Slice  nbits=21  boolean_output=off  mode=Upper Bit Location + Width  bit1=-210  base1=MSB of Input  bit0=0  base0=LSB of Input  dbl_ovrd=off  block_type=slice
  slice23 : xbsIndex_r4/Slice  nbits=21  boolean_output=off  mode=Upper Bit Location + Width  bit1=-189  base1=MSB of Input  bit0=0  base0=LSB of Input  dbl_ovrd=off  block_type=slice
  slice24 : xbsIndex_r4/Slice  nbits=21  boolean_output=off  mode=Upper Bit Location + Width  bit1=-168  base1=MSB of Input  bit0=0  base0=LSB of Input  dbl_ovrd=off  block_type=slice
  slice25 : xbsIndex_r4/Slice  nbits=21  boolean_output=off  mode=Upper Bit Location + Width  bit1=-147  base1=MSB of Input  bit0=0  base0=LSB of Input  dbl_ovrd=off  block_type=slice
  slice26 : xbsIndex_r4/Slice  nbits=21  boolean_output=off  mode=Upper Bit Location + Width  bit1=-126  base1=MSB of Input  bit0=0  base0=LSB of Input  dbl_ovrd=off  block_type=slice
  slice27 : xbsIndex_r4/Slice  nbits=21  boolean_output=off  mode=Upper Bit Location + Width  bit1=-105  base1=MSB of Input  bit0=0  base0=LSB of Input  dbl_ovrd=off  block_type=slice
  slice28 : xbsIndex_r4/Slice  nbits=21  boolean_output=off  mode=Upper Bit Location + Width  bit1=-84  base1=MSB of Input  bit0=0  base0=LSB of Input  dbl_ovrd=off  block_type=slice
  slice29 : xbsIndex_r4/Slice  nbits=21  boolean_output=off  mode=Upper Bit Location + Width  bit1=-63  base1=MSB of Input  bit0=0  base0=LSB of Input  dbl_ovrd=off  block_type=slice
  slice3 : xbsIndex_r4/Slice  nbits=21  boolean_output=off  mode=Upper Bit Location + Width  bit1=-609  base1=MSB of Input  bit0=0  base0=LSB of Input  dbl_ovrd=off  block_type=slice
  slice30 : xbsIndex_r4/Slice  nbits=21  boolean_output=off  mode=Upper Bit Location + Width  bit1=-42  base1=MSB of Input  bit0=0  base0=LSB of Input  dbl_ovrd=off  block_type=slice
  slice31 : xbsIndex_r4/Slice  nbits=21  boolean_output=off  mode=Upper Bit Location + Width  bit1=-21  base1=MSB of Input  bit0=0  base0=LSB of Input  dbl_ovrd=off  block_type=slice
  slice32 : xbsIndex_r4/Slice  nbits=21  boolean_output=off  mode=Upper Bit Location + Width  bit1=0  base1=MSB of Input  bit0=0  base0=LSB of Input  dbl_ovrd=off  block_type=slice
  slice4 : xbsIndex_r4/Slice  nbits=21  boolean_output=off  mode=Upper Bit Location + Width  bit1=-588  base1=MSB of Input  bit0=0  base0=LSB of Input  dbl_ovrd=off  block_type=slice
  slice5 : xbsIndex_r4/Slice  nbits=21  boolean_output=off  mode=Upper Bit Location + Width  bit1=-567  base1=MSB of Input  bit0=0  base0=LSB of Input  dbl_ovrd=off  block_type=slice
  slice6 : xbsIndex_r4/Slice  nbits=21  boolean_output=off  mode=Upper Bit Location + Width  bit1=-546  base1=MSB of Input  bit0=0  base0=LSB of Input  dbl_ovrd=off  block_type=slice
  slice7 : xbsIndex_r4/Slice  nbits=21  boolean_output=off  mode=Upper Bit Location + Width  bit1=-525  base1=MSB of Input  bit0=0  base0=LSB of Input  dbl_ovrd=off  block_type=slice
  slice8 : xbsIndex_r4/Slice  nbits=21  boolean_output=off  mode=Upper Bit Location + Width  bit1=-504  base1=MSB of Input  bit0=0  base0=LSB of Input  dbl_ovrd=off  block_type=slice
  slice9 : xbsIndex_r4/Slice  nbits=21  boolean_output=off  mode=Upper Bit Location + Width  bit1=-483  base1=MSB of Input  bit0=0  base0=LSB of Input  dbl_ovrd=off  block_type=slice
  msb_out32 : Outport
  out31 : Outport  Port=2
  out30 : Outport  Port=3
  out29 : Outport  Port=4
  out28 : Outport  Port=5
  out27 : Outport  Port=6
  out26 : Outport  Port=7
  out25 : Outport  Port=8
  out24 : Outport  Port=9
  out23 : Outport  Port=10
  out22 : Outport  Port=11
  out21 : Outport  Port=12
  out20 : Outport  Port=13
  out19 : Outport  Port=14
  out18 : Outport  Port=15
  out17 : Outport  Port=16
  out16 : Outport  Port=17
  out15 : Outport  Port=18
  out14 : Outport  Port=19
  out13 : Outport  Port=20
  out12 : Outport  Port=21
  out11 : Outport  Port=22
  out10 : Outport  Port=23
  out9 : Outport  Port=24
  out8 : Outport  Port=25
  out7 : Outport  Port=26
  out6 : Outport  Port=27
  out5 : Outport  Port=28
  out4 : Outport  Port=29
  out3 : Outport  Port=30
  out2 : Outport  Port=31
  lsb_out1 : Outport  Port=32
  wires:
  bus_in/1 -> slice32/1, slice31/1, slice30/1, slice29/1, slice28/1, slice27/1, slice26/1, slice25/1, slice24/1, slice23/1, slice22/1, slice21/1, slice20/1, slice19/1, slice18/1, slice17/1, slice16/1, slice15/1, slice14/1, slice13/1, slice12/1, slice11/1, slice10/1, slice9/1, slice8/1, slice7/1, slice6/1, slice5/1, slice4/1, slice3/1, slice2/1, slice1/1
  slice32/1 -> reinterpret32/1
  reinterpret32/1 -> msb_out32/1
  slice31/1 -> reinterpret31/1
  reinterpret31/1 -> out31/1
  slice30/1 -> reinterpret30/1
  reinterpret30/1 -> out30/1
  slice29/1 -> reinterpret29/1
  reinterpret29/1 -> out29/1
  slice28/1 -> reinterpret28/1
  reinterpret28/1 -> out28/1
  slice27/1 -> reinterpret27/1
  reinterpret27/1 -> out27/1
  slice26/1 -> reinterpret26/1
  reinterpret26/1 -> out26/1
  slice25/1 -> reinterpret25/1
  reinterpret25/1 -> out25/1
  slice24/1 -> reinterpret24/1
  reinterpret24/1 -> out24/1
  slice23/1 -> reinterpret23/1
  reinterpret23/1 -> out23/1
  slice22/1 -> reinterpret22/1
  reinterpret22/1 -> out22/1
  slice21/1 -> reinterpret21/1
  reinterpret21/1 -> out21/1
  slice20/1 -> reinterpret20/1
  reinterpret20/1 -> out20/1
  slice19/1 -> reinterpret19/1
  reinterpret19/1 -> out19/1
  slice18/1 -> reinterpret18/1
  reinterpret18/1 -> out18/1
  slice17/1 -> reinterpret17/1
  reinterpret17/1 -> out17/1
  slice16/1 -> reinterpret16/1
  reinterpret16/1 -> out16/1
  slice15/1 -> reinterpret15/1
  reinterpret15/1 -> out15/1
  slice14/1 -> reinterpret14/1
  reinterpret14/1 -> out14/1
  slice13/1 -> reinterpret13/1
  reinterpret13/1 -> out13/1
  slice12/1 -> reinterpret12/1
  reinterpret12/1 -> out12/1
  slice11/1 -> reinterpret11/1
  reinterpret11/1 -> out11/1
  slice10/1 -> reinterpret10/1
  reinterpret10/1 -> out10/1
  slice9/1 -> reinterpret9/1
  reinterpret9/1 -> out9/1
  slice8/1 -> reinterpret8/1
  reinterpret8/1 -> out8/1
  slice7/1 -> reinterpret7/1
  reinterpret7/1 -> out7/1
  slice6/1 -> reinterpret6/1
  reinterpret6/1 -> out6/1
  slice5/1 -> reinterpret5/1
  reinterpret5/1 -> out5/1
  slice4/1 -> reinterpret4/1
  reinterpret4/1 -> out4/1
  slice3/1 -> reinterpret3/1
  reinterpret3/1 -> out3/1
  slice2/1 -> reinterpret2/1
  reinterpret2/1 -> out2/1
  slice1/1 -> reinterpret1/1
  reinterpret1/1 -> lsb_out1/1

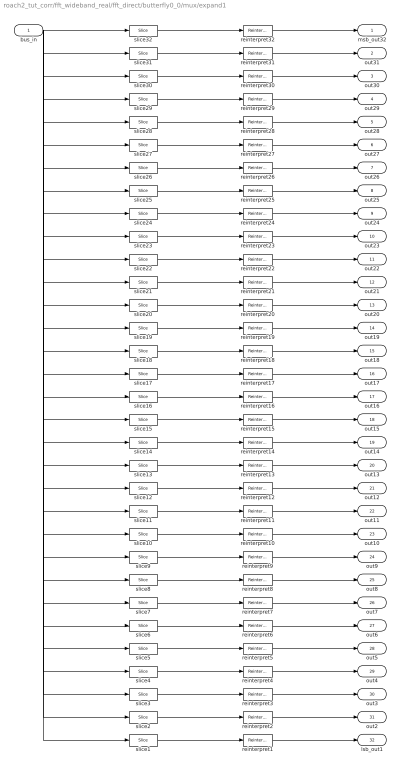
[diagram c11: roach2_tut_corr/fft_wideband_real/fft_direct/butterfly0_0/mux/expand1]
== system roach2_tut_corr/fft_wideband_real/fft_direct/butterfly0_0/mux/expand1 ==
  bus_in : Inport
  reinterpret{1..32} (32 alike) : xbsIndex_r4/Reinterpret  force_arith_type=on  arith_type=Unsigned  force_bin_pt=on  bin_pt=0  block_type=reinterpret
  slice1 : xbsIndex_r4/Slice  nbits=21  boolean_output=off  mode=Upper Bit Location + Width  bit1=-651  base1=MSB of Input  bit0=0  base0=LSB of Input  dbl_ovrd=off  block_type=slice
  slice10 : xbsIndex_r4/Slice  nbits=21  boolean_output=off  mode=Upper Bit Location + Width  bit1=-462  base1=MSB of Input  bit0=0  base0=LSB of Input  dbl_ovrd=off  block_type=slice
  slice11 : xbsIndex_r4/Slice  nbits=21  boolean_output=off  mode=Upper Bit Location + Width  bit1=-441  base1=MSB of Input  bit0=0  base0=LSB of Input  dbl_ovrd=off  block_type=slice
  slice12 : xbsIndex_r4/Slice  nbits=21  boolean_output=off  mode=Upper Bit Location + Width  bit1=-420  base1=MSB of Input  bit0=0  base0=LSB of Input  dbl_ovrd=off  block_type=slice
  slice13 : xbsIndex_r4/Slice  nbits=21  boolean_output=off  mode=Upper Bit Location + Width  bit1=-399  base1=MSB of Input  bit0=0  base0=LSB of Input  dbl_ovrd=off  block_type=slice
  slice14 : xbsIndex_r4/Slice  nbits=21  boolean_output=off  mode=Upper Bit Location + Width  bit1=-378  base1=MSB of Input  bit0=0  base0=LSB of Input  dbl_ovrd=off  block_type=slice
  slice15 : xbsIndex_r4/Slice  nbits=21  boolean_output=off  mode=Upper Bit Location + Width  bit1=-357  base1=MSB of Input  bit0=0  base0=LSB of Input  dbl_ovrd=off  block_type=slice
  slice16 : xbsIndex_r4/Slice  nbits=21  boolean_output=off  mode=Upper Bit Location + Width  bit1=-336  base1=MSB of Input  bit0=0  base0=LSB of Input  dbl_ovrd=off  block_type=slice
  slice17 : xbsIndex_r4/Slice  nbits=21  boolean_output=off  mode=Upper Bit Location + Width  bit1=-315  base1=MSB of Input  bit0=0  base0=LSB of Input  dbl_ovrd=off  block_type=slice
  slice18 : xbsIndex_r4/Slice  nbits=21  boolean_output=off  mode=Upper Bit Location + Width  bit1=-294  base1=MSB of Input  bit0=0  base0=LSB of Input  dbl_ovrd=off  block_type=slice
  slice19 : xbsIndex_r4/Slice  nbits=21  boolean_output=off  mode=Upper Bit Location + Width  bit1=-273  base1=MSB of Input  bit0=0  base0=LSB of Input  dbl_ovrd=off  block_type=slice
  slice2 : xbsIndex_r4/Slice  nbits=21  boolean_output=off  mode=Upper Bit Location + Width  bit1=-630  base1=MSB of Input  bit0=0  base0=LSB of Input  dbl_ovrd=off  block_type=slice
  slice20 : xbsIndex_r4/Slice  nbits=21  boolean_output=off  mode=Upper Bit Location + Width  bit1=-252  base1=MSB of Input  bit0=0  base0=LSB of Input  dbl_ovrd=off  block_type=slice
  slice21 : xbsIndex_r4/Slice  nbits=21  boolean_output=off  mode=Upper Bit Location + Width  bit1=-231  base1=MSB of Input  bit0=0  base0=LSB of Input  dbl_ovrd=off  block_type=slice
  slice22 : xbsIndex_r4/Slice  nbits=21  boolean_output=off  mode=Upper Bit Location + Width  bit1=-210  base1=MSB of Input  bit0=0  base0=LSB of Input  dbl_ovrd=off  block_type=slice
  slice23 : xbsIndex_r4/Slice  nbits=21  boolean_output=off  mode=Upper Bit Location + Width  bit1=-189  base1=MSB of Input  bit0=0  base0=LSB of Input  dbl_ovrd=off  block_type=slice
  slice24 : xbsIndex_r4/Slice  nbits=21  boolean_output=off  mode=Upper Bit Location + Width  bit1=-168  base1=MSB of Input  bit0=0  base0=LSB of Input  dbl_ovrd=off  block_type=slice
  slice25 : xbsIndex_r4/Slice  nbits=21  boolean_output=off  mode=Upper Bit Location + Width  bit1=-147  base1=MSB of Input  bit0=0  base0=LSB of Input  dbl_ovrd=off  block_type=slice
  slice26 : xbsIndex_r4/Slice  nbits=21  boolean_output=off  mode=Upper Bit Location + Width  bit1=-126  base1=MSB of Input  bit0=0  base0=LSB of Input  dbl_ovrd=off  block_type=slice
  slice27 : xbsIndex_r4/Slice  nbits=21  boolean_output=off  mode=Upper Bit Location + Width  bit1=-105  base1=MSB of Input  bit0=0  base0=LSB of Input  dbl_ovrd=off  block_type=slice
  slice28 : xbsIndex_r4/Slice  nbits=21  boolean_output=off  mode=Upper Bit Location + Width  bit1=-84  base1=MSB of Input  bit0=0  base0=LSB of Input  dbl_ovrd=off  block_type=slice
  slice29 : xbsIndex_r4/Slice  nbits=21  boolean_output=off  mode=Upper Bit Location + Width  bit1=-63  base1=MSB of Input  bit0=0  base0=LSB of Input  dbl_ovrd=off  block_type=slice
  slice3 : xbsIndex_r4/Slice  nbits=21  boolean_output=off  mode=Upper Bit Location + Width  bit1=-609  base1=MSB of Input  bit0=0  base0=LSB of Input  dbl_ovrd=off  block_type=slice
  slice30 : xbsIndex_r4/Slice  nbits=21  boolean_output=off  mode=Upper Bit Location + Width  bit1=-42  base1=MSB of Input  bit0=0  base0=LSB of Input  dbl_ovrd=off  block_type=slice
  slice31 : xbsIndex_r4/Slice  nbits=21  boolean_output=off  mode=Upper Bit Location + Width  bit1=-21  base1=MSB of Input  bit0=0  base0=LSB of Input  dbl_ovrd=off  block_type=slice
  slice32 : xbsIndex_r4/Slice  nbits=21  boolean_output=off  mode=Upper Bit Location + Width  bit1=0  base1=MSB of Input  bit0=0  base0=LSB of Input  dbl_ovrd=off  block_type=slice
  slice4 : xbsIndex_r4/Slice  nbits=21  boolean_output=off  mode=Upper Bit Location + Width  bit1=-588  base1=MSB of Input  bit0=0  base0=LSB of Input  dbl_ovrd=off  block_type=slice
  slice5 : xbsIndex_r4/Slice  nbits=21  boolean_output=off  mode=Upper Bit Location + Width  bit1=-567  base1=MSB of Input  bit0=0  base0=LSB of Input  dbl_ovrd=off  block_type=slice
  slice6 : xbsIndex_r4/Slice  nbits=21  boolean_output=off  mode=Upper Bit Location + Width  bit1=-546  base1=MSB of Input  bit0=0  base0=LSB of Input  dbl_ovrd=off  block_type=slice
  slice7 : xbsIndex_r4/Slice  nbits=21  boolean_output=off  mode=Upper Bit Location + Width  bit1=-525  base1=MSB of Input  bit0=0  base0=LSB of Input  dbl_ovrd=off  block_type=slice
  slice8 : xbsIndex_r4/Slice  nbits=21  boolean_output=off  mode=Upper Bit Location + Width  bit1=-504  base1=MSB of Input  bit0=0  base0=LSB of Input  dbl_ovrd=off  block_type=slice
  slice9 : xbsIndex_r4/Slice  nbits=21  boolean_output=off  mode=Upper Bit Location + Width  bit1=-483  base1=MSB of Input  bit0=0  base0=LSB of Input  dbl_ovrd=off  block_type=slice
  msb_out32 : Outport
  out31 : Outport  Port=2
  out30 : Outport  Port=3
  out29 : Outport  Port=4
  out28 : Outport  Port=5
  out27 : Outport  Port=6
  out26 : Outport  Port=7
  out25 : Outport  Port=8
  out24 : Outport  Port=9
  out23 : Outport  Port=10
  out22 : Outport  Port=11
  out21 : Outport  Port=12
  out20 : Outport  Port=13
  out19 : Outport  Port=14
  out18 : Outport  Port=15
  out17 : Outport  Port=16
  out16 : Outport  Port=17
  out15 : Outport  Port=18
  out14 : Outport  Port=19
  out13 : Outport  Port=20
  out12 : Outport  Port=21
  out11 : Outport  Port=22
  out10 : Outport  Port=23
  out9 : Outport  Port=24
  out8 : Outport  Port=25
  out7 : Outport  Port=26
  out6 : Outport  Port=27
  out5 : Outport  Port=28
  out4 : Outport  Port=29
  out3 : Outport  Port=30
  out2 : Outport  Port=31
  lsb_out1 : Outport  Port=32
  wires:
  bus_in/1 -> slice32/1, slice31/1, slice30/1, slice29/1, slice28/1, slice27/1, slice26/1, slice25/1, slice24/1, slice23/1, slice22/1, slice21/1, slice20/1, slice19/1, slice18/1, slice17/1, slice16/1, slice15/1, slice14/1, slice13/1, slice12/1, slice11/1, slice10/1, slice9/1, slice8/1, slice7/1, slice6/1, slice5/1, slice4/1, slice3/1, slice2/1, slice1/1
  slice32/1 -> reinterpret32/1
  reinterpret32/1 -> msb_out32/1
  slice31/1 -> reinterpret31/1
  reinterpret31/1 -> out31/1
  slice30/1 -> reinterpret30/1
  reinterpret30/1 -> out30/1
  slice29/1 -> reinterpret29/1
  reinterpret29/1 -> out29/1
  slice28/1 -> reinterpret28/1
  reinterpret28/1 -> out28/1
  slice27/1 -> reinterpret27/1
  reinterpret27/1 -> out27/1
  slice26/1 -> reinterpret26/1
  reinterpret26/1 -> out26/1
  slice25/1 -> reinterpret25/1
  reinterpret25/1 -> out25/1
  slice24/1 -> reinterpret24/1
  reinterpret24/1 -> out24/1
  slice23/1 -> reinterpret23/1
  reinterpret23/1 -> out23/1
  slice22/1 -> reinterpret22/1
  reinterpret22/1 -> out22/1
  slice21/1 -> reinterpret21/1
  reinterpret21/1 -> out21/1
  slice20/1 -> reinterpret20/1
  reinterpret20/1 -> out20/1
  slice19/1 -> reinterpret19/1
  reinterpret19/1 -> out19/1
  slice18/1 -> reinterpret18/1
  reinterpret18/1 -> out18/1
  slice17/1 -> reinterpret17/1
  reinterpret17/1 -> out17/1
  slice16/1 -> reinterpret16/1
  reinterpret16/1 -> out16/1
  slice15/1 -> reinterpret15/1
  reinterpret15/1 -> out15/1
  slice14/1 -> reinterpret14/1
  reinterpret14/1 -> out14/1
  slice13/1 -> reinterpret13/1
  reinterpret13/1 -> out13/1
  slice12/1 -> reinterpret12/1
  reinterpret12/1 -> out12/1
  slice11/1 -> reinterpret11/1
  reinterpret11/1 -> out11/1
  slice10/1 -> reinterpret10/1
  reinterpret10/1 -> out10/1
  slice9/1 -> reinterpret9/1
  reinterpret9/1 -> out9/1
  slice8/1 -> reinterpret8/1
  reinterpret8/1 -> out8/1
  slice7/1 -> reinterpret7/1
  reinterpret7/1 -> out7/1
  slice6/1 -> reinterpret6/1
  reinterpret6/1 -> out6/1
  slice5/1 -> reinterpret5/1
  reinterpret5/1 -> out5/1
  slice4/1 -> reinterpret4/1
  reinterpret4/1 -> out4/1
  slice3/1 -> reinterpret3/1
  reinterpret3/1 -> out3/1
  slice2/1 -> reinterpret2/1
  reinterpret2/1 -> out2/1
  slice1/1 -> reinterpret1/1
  reinterpret1/1 -> lsb_out1/1

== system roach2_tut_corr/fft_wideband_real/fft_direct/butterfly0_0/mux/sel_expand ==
  bus_in : Inport
  reinterpret{1..32} (32 alike) : xbsIndex_r4/Reinterpret  force_arith_type=on  arith_type=Unsigned  force_bin_pt=on  bin_pt=0  block_type=reinterpret
  slice1 : xbsIndex_r4/Slice  nbits=1  boolean_output=off  mode=Upper Bit Location + Width  bit1=-31  base1=MSB of Input  bit0=0  base0=LSB of Input  dbl_ovrd=off  block_type=slice
  slice10 : xbsIndex_r4/Slice  nbits=1  boolean_output=off  mode=Upper Bit Location + Width  bit1=-22  base1=MSB of Input  bit0=0  base0=LSB of Input  dbl_ovrd=off  block_type=slice
  slice11 : xbsIndex_r4/Slice  nbits=1  boolean_output=off  mode=Upper Bit Location + Width  bit1=-21  base1=MSB of Input  bit0=0  base0=LSB of Input  dbl_ovrd=off  block_type=slice
  slice12 : xbsIndex_r4/Slice  nbits=1  boolean_output=off  mode=Upper Bit Location + Width  bit1=-20  base1=MSB of Input  bit0=0  base0=LSB of Input  dbl_ovrd=off  block_type=slice
  slice13 : xbsIndex_r4/Slice  nbits=1  boolean_output=off  mode=Upper Bit Location + Width  bit1=-19  base1=MSB of Input  bit0=0  base0=LSB of Input  dbl_ovrd=off  block_type=slice
  slice14 : xbsIndex_r4/Slice  nbits=1  boolean_output=off  mode=Upper Bit Location + Width  bit1=-18  base1=MSB of Input  bit0=0  base0=LSB of Input  dbl_ovrd=off  block_type=slice
  slice15 : xbsIndex_r4/Slice  nbits=1  boolean_output=off  mode=Upper Bit Location + Width  bit1=-17  base1=MSB of Input  bit0=0  base0=LSB of Input  dbl_ovrd=off  block_type=slice
  slice16 : xbsIndex_r4/Slice  nbits=1  boolean_output=off  mode=Upper Bit Location + Width  bit1=-16  base1=MSB of Input  bit0=0  base0=LSB of Input  dbl_ovrd=off  block_type=slice
  slice17 : xbsIndex_r4/Slice  nbits=1  boolean_output=off  mode=Upper Bit Location + Width  bit1=-15  base1=MSB of Input  bit0=0  base0=LSB of Input  dbl_ovrd=off  block_type=slice
  slice18 : xbsIndex_r4/Slice  nbits=1  boolean_output=off  mode=Upper Bit Location + Width  bit1=-14  base1=MSB of Input  bit0=0  base0=LSB of Input  dbl_ovrd=off  block_type=slice
  slice19 : xbsIndex_r4/Slice  nbits=1  boolean_output=off  mode=Upper Bit Location + Width  bit1=-13  base1=MSB of Input  bit0=0  base0=LSB of Input  dbl_ovrd=off  block_type=slice
  slice2 : xbsIndex_r4/Slice  nbits=1  boolean_output=off  mode=Upper Bit Location + Width  bit1=-30  base1=MSB of Input  bit0=0  base0=LSB of Input  dbl_ovrd=off  block_type=slice
  slice20 : xbsIndex_r4/Slice  nbits=1  boolean_output=off  mode=Upper Bit Location + Width  bit1=-12  base1=MSB of Input  bit0=0  base0=LSB of Input  dbl_ovrd=off  block_type=slice
  slice21 : xbsIndex_r4/Slice  nbits=1  boolean_output=off  mode=Upper Bit Location + Width  bit1=-11  base1=MSB of Input  bit0=0  base0=LSB of Input  dbl_ovrd=off  block_type=slice
  slice22 : xbsIndex_r4/Slice  nbits=1  boolean_output=off  mode=Upper Bit Location + Width  bit1=-10  base1=MSB of Input  bit0=0  base0=LSB of Input  dbl_ovrd=off  block_type=slice
  slice23 : xbsIndex_r4/Slice  nbits=1  boolean_output=off  mode=Upper Bit Location + Width  bit1=-9  base1=MSB of Input  bit0=0  base0=LSB of Input  dbl_ovrd=off  block_type=slice
  slice24 : xbsIndex_r4/Slice  nbits=1  boolean_output=off  mode=Upper Bit Location + Width  bit1=-8  base1=MSB of Input  bit0=0  base0=LSB of Input  dbl_ovrd=off  block_type=slice
  slice25 : xbsIndex_r4/Slice  nbits=1  boolean_output=off  mode=Upper Bit Location + Width  bit1=-7  base1=MSB of Input  bit0=0  base0=LSB of Input  dbl_ovrd=off  block_type=slice
  slice26 : xbsIndex_r4/Slice  nbits=1  boolean_output=off  mode=Upper Bit Location + Width  bit1=-6  base1=MSB of Input  bit0=0  base0=LSB of Input  dbl_ovrd=off  block_type=slice
  slice27 : xbsIndex_r4/Slice  nbits=1  boolean_output=off  mode=Upper Bit Location + Width  bit1=-5  base1=MSB of Input  bit0=0  base0=LSB of Input  dbl_ovrd=off  block_type=slice
  slice28 : xbsIndex_r4/Slice  nbits=1  boolean_output=off  mode=Upper Bit Location + Width  bit1=-4  base1=MSB of Input  bit0=0  base0=LSB of Input  dbl_ovrd=off  block_type=slice
  slice29 : xbsIndex_r4/Slice  nbits=1  boolean_output=off  mode=Upper Bit Location + Width  bit1=-3  base1=MSB of Input  bit0=0  base0=LSB of Input  dbl_ovrd=off  block_type=slice
  slice3 : xbsIndex_r4/Slice  nbits=1  boolean_output=off  mode=Upper Bit Location + Width  bit1=-29  base1=MSB of Input  bit0=0  base0=LSB of Input  dbl_ovrd=off  block_type=slice
  slice30 : xbsIndex_r4/Slice  nbits=1  boolean_output=off  mode=Upper Bit Location + Width  bit1=-2  base1=MSB of Input  bit0=0  base0=LSB of Input  dbl_ovrd=off  block_type=slice
  slice31 : xbsIndex_r4/Slice  nbits=1  boolean_output=off  mode=Upper Bit Location + Width  bit1=-1  base1=MSB of Input  bit0=0  base0=LSB of Input  dbl_ovrd=off  block_type=slice
  slice32 : xbsIndex_r4/Slice  nbits=1  boolean_output=off  mode=Upper Bit Location + Width  bit1=0  base1=MSB of Input  bit0=0  base0=LSB of Input  dbl_ovrd=off  block_type=slice
  slice4 : xbsIndex_r4/Slice  nbits=1  boolean_output=off  mode=Upper Bit Location + Width  bit1=-28  base1=MSB of Input  bit0=0  base0=LSB of Input  dbl_ovrd=off  block_type=slice
  slice5 : xbsIndex_r4/Slice  nbits=1  boolean_output=off  mode=Upper Bit Location + Width  bit1=-27  base1=MSB of Input  bit0=0  base0=LSB of Input  dbl_ovrd=off  block_type=slice
  slice6 : xbsIndex_r4/Slice  nbits=1  boolean_output=off  mode=Upper Bit Location + Width  bit1=-26  base1=MSB of Input  bit0=0  base0=LSB of Input  dbl_ovrd=off  block_type=slice
  slice7 : xbsIndex_r4/Slice  nbits=1  boolean_output=off  mode=Upper Bit Location + Width  bit1=-25  base1=MSB of Input  bit0=0  base0=LSB of Input  dbl_ovrd=off  block_type=slice
  slice8 : xbsIndex_r4/Slice  nbits=1  boolean_output=off  mode=Upper Bit Location + Width  bit1=-24  base1=MSB of Input  bit0=0  base0=LSB of Input  dbl_ovrd=off  block_type=slice
  slice9 : xbsIndex_r4/Slice  nbits=1  boolean_output=off  mode=Upper Bit Location + Width  bit1=-23  base1=MSB of Input  bit0=0  base0=LSB of Input  dbl_ovrd=off  block_type=slice
  msb_out32 : Outport
  out31 : Outport  Port=2
  out30 : Outport  Port=3
  out29 : Outport  Port=4
  out28 : Outport  Port=5
  out27 : Outport  Port=6
  out26 : Outport  Port=7
  out25 : Outport  Port=8
  out24 : Outport  Port=9
  out23 : Outport  Port=10
  out22 : Outport  Port=11
  out21 : Outport  Port=12
  out20 : Outport  Port=13
  out19 : Outport  Port=14
  out18 : Outport  Port=15
  out17 : Outport  Port=16
  out16 : Outport  Port=17
  out15 : Outport  Port=18
  out14 : Outport  Port=19
  out13 : Outport  Port=20
  out12 : Outport  Port=21
  out11 : Outport  Port=22
  out10 : Outport  Port=23
  out9 : Outport  Port=24
  out8 : Outport  Port=25
  out7 : Outport  Port=26
  out6 : Outport  Port=27
  out5 : Outport  Port=28
  out4 : Outport  Port=29
  out3 : Outport  Port=30
  out2 : Outport  Port=31
  lsb_out1 : Outport  Port=32
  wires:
  bus_in/1 -> slice32/1, slice31/1, slice30/1, slice29/1, slice28/1, slice27/1, slice26/1, slice25/1, slice24/1, slice23/1, slice22/1, slice21/1, slice20/1, slice19/1, slice18/1, slice17/1, slice16/1, slice15/1, slice14/1, slice13/1, slice12/1, slice11/1, slice10/1, slice9/1, slice8/1, slice7/1, slice6/1, slice5/1, slice4/1, slice3/1, slice2/1, slice1/1
  slice32/1 -> reinterpret32/1
  reinterpret32/1 -> msb_out32/1
  slice31/1 -> reinterpret31/1
  reinterpret31/1 -> out31/1
  slice30/1 -> reinterpret30/1
  reinterpret30/1 -> out30/1
  slice29/1 -> reinterpret29/1
  reinterpret29/1 -> out29/1
  slice28/1 -> reinterpret28/1
  reinterpret28/1 -> out28/1
  slice27/1 -> reinterpret27/1
  reinterpret27/1 -> out27/1
  slice26/1 -> reinterpret26/1
  reinterpret26/1 -> out26/1
  slice25/1 -> reinterpret25/1
  reinterpret25/1 -> out25/1
  slice24/1 -> reinterpret24/1
  reinterpret24/1 -> out24/1
  slice23/1 -> reinterpret23/1
  reinterpret23/1 -> out23/1
  slice22/1 -> reinterpret22/1
  reinterpret22/1 -> out22/1
  slice21/1 -> reinterpret21/1
  reinterpret21/1 -> out21/1
  slice20/1 -> reinterpret20/1
  reinterpret20/1 -> out20/1
  slice19/1 -> reinterpret19/1
  reinterpret19/1 -> out19/1
  slice18/1 -> reinterpret18/1
  reinterpret18/1 -> out18/1
  slice17/1 -> reinterpret17/1
  reinterpret17/1 -> out17/1
  slice16/1 -> reinterpret16/1
  reinterpret16/1 -> out16/1
  slice15/1 -> reinterpret15/1
  reinterpret15/1 -> out15/1
  slice14/1 -> reinterpret14/1
  reinterpret14/1 -> out14/1
  slice13/1 -> reinterpret13/1
  reinterpret13/1 -> out13/1
  slice12/1 -> reinterpret12/1
  reinterpret12/1 -> out12/1
  slice11/1 -> reinterpret11/1
  reinterpret11/1 -> out11/1
  slice10/1 -> reinterpret10/1
  reinterpret10/1 -> out10/1
  slice9/1 -> reinterpret9/1
  reinterpret9/1 -> out9/1
  slice8/1 -> reinterpret8/1
  reinterpret8/1 -> out8/1
  slice7/1 -> reinterpret7/1
  reinterpret7/1 -> out7/1
  slice6/1 -> reinterpret6/1
  reinterpret6/1 -> out6/1
  slice5/1 -> reinterpret5/1
  reinterpret5/1 -> out5/1
  slice4/1 -> reinterpret4/1
  reinterpret4/1 -> out4/1
  slice3/1 -> reinterpret3/1
  reinterpret3/1 -> out3/1
  slice2/1 -> reinterpret2/1
  reinterpret2/1 -> out2/1
  slice1/1 -> reinterpret1/1
  reinterpret1/1 -> lsb_out1/1

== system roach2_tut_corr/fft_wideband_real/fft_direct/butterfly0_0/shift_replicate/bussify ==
  in1 : Inport
  in2 : Inport  Port=2
  in3 : Inport  Port=3
  in4 : Inport  Port=4
  in5 : Inport  Port=5
  in6 : Inport  Port=6
  in7 : Inport  Port=7
  in8 : Inport  Port=8
  in9 : Inport  Port=9
  in10 : Inport  Port=10
  in11 : Inport  Port=11
  in12 : Inport  Port=12
  in13 : Inport  Port=13
  in14 : Inport  Port=14
  in15 : Inport  Port=15
  in16 : Inport  Port=16
  in17 : Inport  Port=17
  in18 : Inport  Port=18
  in19 : Inport  Port=19
  in20 : Inport  Port=20
  in21 : Inport  Port=21
  in22 : Inport  Port=22
  in23 : Inport  Port=23
  in24 : Inport  Port=24
  in25 : Inport  Port=25
  in26 : Inport  Port=26
  in27 : Inport  Port=27
  in28 : Inport  Port=28
  in29 : Inport  Port=29
  in30 : Inport  Port=30
  in31 : Inport  Port=31
  in32 : Inport  Port=32
  concatenate : xbsIndex_r4/Concat  num_inputs=32  dbl_ovrd=off  block_type=concat
  reinterpret{1..32} (32 alike) : xbsIndex_r4/Reinterpret  force_arith_type=on  arith_type=Unsigned  force_bin_pt=on  bin_pt=0  block_type=reinterpret
  bus_out : Outport
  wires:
  concatenate/1 -> bus_out/1
  in1/1 -> reinterpret1/1
  reinterpret1/1 -> concatenate/1
  in2/1 -> reinterpret2/1
  reinterpret2/1 -> concatenate/2
  in3/1 -> reinterpret3/1
  reinterpret3/1 -> concatenate/3
  in4/1 -> reinterpret4/1
  reinterpret4/1 -> concatenate/4
  in5/1 -> reinterpret5/1
  reinterpret5/1 -> concatenate/5
  in6/1 -> reinterpret6/1
  reinterpret6/1 -> concatenate/6
  in7/1 -> reinterpret7/1
  reinterpret7/1 -> concatenate/7
  in8/1 -> reinterpret8/1
  reinterpret8/1 -> concatenate/8
  in9/1 -> reinterpret9/1
  reinterpret9/1 -> concatenate/9
  in10/1 -> reinterpret10/1
  reinterpret10/1 -> concatenate/10
  in11/1 -> reinterpret11/1
  reinterpret11/1 -> concatenate/11
  in12/1 -> reinterpret12/1
  reinterpret12/1 -> concatenate/12
  in13/1 -> reinterpret13/1
  reinterpret13/1 -> concatenate/13
  in14/1 -> reinterpret14/1
  reinterpret14/1 -> concatenate/14
  in15/1 -> reinterpret15/1
  reinterpret15/1 -> concatenate/15
  in16/1 -> reinterpret16/1
  reinterpret16/1 -> concatenate/16
  in17/1 -> reinterpret17/1
  reinterpret17/1 -> concatenate/17
  in18/1 -> reinterpret18/1
  reinterpret18/1 -> concatenate/18
  in19/1 -> reinterpret19/1
  reinterpret19/1 -> concatenate/19
  in20/1 -> reinterpret20/1
  reinterpret20/1 -> concatenate/20
  in21/1 -> reinterpret21/1
  reinterpret21/1 -> concatenate/21
  in22/1 -> reinterpret22/1
  reinterpret22/1 -> concatenate/22
  in23/1 -> reinterpret23/1
  reinterpret23/1 -> concatenate/23
  in24/1 -> reinterpret24/1
  reinterpret24/1 -> concatenate/24
  in25/1 -> reinterpret25/1
  reinterpret25/1 -> concatenate/25
  in26/1 -> reinterpret26/1
  reinterpret26/1 -> concatenate/26
  in27/1 -> reinterpret27/1
  reinterpret27/1 -> concatenate/27
  in28/1 -> reinterpret28/1
  reinterpret28/1 -> concatenate/28
  in29/1 -> reinterpret29/1
  reinterpret29/1 -> concatenate/29
  in30/1 -> reinterpret30/1
  reinterpret30/1 -> concatenate/30
  in31/1 -> reinterpret31/1
  reinterpret31/1 -> concatenate/31
  in32/1 -> reinterpret32/1
  reinterpret32/1 -> concatenate/32

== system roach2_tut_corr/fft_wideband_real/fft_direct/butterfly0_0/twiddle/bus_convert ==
  din : Inport
  misci : Inport  Port=2
  bussify : Subsystem  AncestorBlock=casper_library_flow_control/bus_create
  conv1 : Subsystem  AncestorBlock=casper_library_misc/convert
  conv10 : Subsystem  AncestorBlock=casper_library_misc/convert
  conv11 : Subsystem  AncestorBlock=casper_library_misc/convert
  conv12 : Subsystem  AncestorBlock=casper_library_misc/convert
  conv13 : Subsystem  AncestorBlock=casper_library_misc/convert
  conv14 : Subsystem  AncestorBlock=casper_library_misc/convert
  conv15 : Subsystem  AncestorBlock=casper_library_misc/convert
  conv16 : Subsystem  AncestorBlock=casper_library_misc/convert
  conv2 : Subsystem  AncestorBlock=casper_library_misc/convert
  conv3 : Subsystem  AncestorBlock=casper_library_misc/convert
  conv4 : Subsystem  AncestorBlock=casper_library_misc/convert
  conv5 : Subsystem  AncestorBlock=casper_library_misc/convert
  conv6 : Subsystem  AncestorBlock=casper_library_misc/convert
  conv7 : Subsystem  AncestorBlock=casper_library_misc/convert
  conv8 : Subsystem  AncestorBlock=casper_library_misc/convert
  conv9 : Subsystem  AncestorBlock=casper_library_misc/convert
  debus : Subsystem  AncestorBlock=casper_library_flow_control/bus_expand
  dmisc : xbsIndex_r4/Delay  rst=off  infoeditControl=Selection of Reset will increase slice count due to use of real FFs and instead of SRLs  en=off  latency=latency  dbl_ovrd=off  reg_retiming=on  block_type=delay
  dout : Outport
  misco : Outport  Port=2
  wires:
  din/1 -> debus/1(bus_in)
  debus/1(msb_out16) -> conv1/1(in)
  debus/2(out15) -> conv2/1(in)
  debus/3(out14) -> conv3/1(in)
  debus/4(out13) -> conv4/1(in)
  debus/5(out12) -> conv5/1(in)
  debus/6(out11) -> conv6/1(in)
  debus/7(out10) -> conv7/1(in)
  debus/8(out9) -> conv8/1(in)
  debus/9(out8) -> conv9/1(in)
  debus/10(out7) -> conv10/1(in)
  debus/11(out6) -> conv11/1(in)
  debus/12(out5) -> conv12/1(in)
  debus/13(out4) -> conv13/1(in)
  debus/14(out3) -> conv14/1(in)
  debus/15(out2) -> conv15/1(in)
  debus/16(lsb_out1) -> conv16/1(in)
  misci/1 -> dmisc/1
  conv1/1(out) -> bussify/1(in1)
  conv2/1(out) -> bussify/2(in2)
  conv3/1(out) -> bussify/3(in3)
  conv4/1(out) -> bussify/4(in4)
  conv5/1(out) -> bussify/5(in5)
  conv6/1(out) -> bussify/6(in6)
  conv7/1(out) -> bussify/7(in7)
  conv8/1(out) -> bussify/8(in8)
  conv9/1(out) -> bussify/9(in9)
  conv10/1(out) -> bussify/10(in10)
  conv11/1(out) -> bussify/11(in11)
  conv12/1(out) -> bussify/12(in12)
  conv13/1(out) -> bussify/13(in13)
  conv14/1(out) -> bussify/14(in14)
  conv15/1(out) -> bussify/15(in15)
  conv16/1(out) -> bussify/16(in16)
  bussify/1(bus_out) -> dout/1
  dmisc/1 -> misco/1

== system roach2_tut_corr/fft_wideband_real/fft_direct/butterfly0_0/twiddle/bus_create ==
  in1 : Inport
  in2 : Inport  Port=2
  in3 : Inport  Port=3
  concatenate : xbsIndex_r4/Concat  num_inputs=3  dbl_ovrd=off  block_type=concat
  reinterpret1 : xbsIndex_r4/Reinterpret  force_arith_type=on  arith_type=Unsigned  force_bin_pt=on  bin_pt=0  block_type=reinterpret
  reinterpret2 : xbsIndex_r4/Reinterpret  force_arith_type=on  arith_type=Unsigned  force_bin_pt=on  bin_pt=0  block_type=reinterpret
  reinterpret3 : xbsIndex_r4/Reinterpret  force_arith_type=on  arith_type=Unsigned  force_bin_pt=on  bin_pt=0  block_type=reinterpret
  bus_out : Outport
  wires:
  concatenate/1 -> bus_out/1
  in1/1 -> reinterpret1/1
  reinterpret1/1 -> concatenate/1
  in2/1 -> reinterpret2/1
  reinterpret2/1 -> concatenate/2
  in3/1 -> reinterpret3/1
  reinterpret3/1 -> concatenate/3

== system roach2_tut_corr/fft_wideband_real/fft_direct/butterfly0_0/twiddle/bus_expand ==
  bus_in : Inport
  reinterpret1 : xbsIndex_r4/Reinterpret  force_arith_type=on  arith_type=Unsigned  force_bin_pt=on  bin_pt=0  block_type=reinterpret
  reinterpret2 : xbsIndex_r4/Reinterpret  force_arith_type=on  arith_type=Unsigned  force_bin_pt=on  bin_pt=0  block_type=reinterpret
  slice1 : xbsIndex_r4/Slice  nbits=289  boolean_output=off  mode=Upper Bit Location + Width  bit1=-288  base1=MSB of Input  bit0=0  base0=LSB of Input  dbl_ovrd=off  block_type=slice
  slice2 : xbsIndex_r4/Slice  nbits=288  boolean_output=off  mode=Upper Bit Location + Width  bit1=0  base1=MSB of Input  bit0=0  base0=LSB of Input  dbl_ovrd=off  block_type=slice
  msb_out2 : Outport
  lsb_out1 : Outport  Port=2
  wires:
  bus_in/1 -> slice2/1, slice1/1
  slice2/1 -> reinterpret2/1
  reinterpret2/1 -> msb_out2/1
  slice1/1 -> reinterpret1/1
  reinterpret1/1 -> lsb_out1/1

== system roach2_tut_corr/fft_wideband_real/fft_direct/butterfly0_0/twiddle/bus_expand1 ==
  bus_in : Inport
  reinterpret1 : xbsIndex_r4/Reinterpret  force_arith_type=on  arith_type=Unsigned  force_bin_pt=on  bin_pt=0  block_type=reinterpret
  slice1 : xbsIndex_r4/Slice  nbits=288  boolean_output=off  mode=Upper Bit Location + Width  bit1=-1  base1=MSB of Input  bit0=0  base0=LSB of Input  dbl_ovrd=off  block_type=slice
  slice2 : xbsIndex_r4/Slice  nbits=1  boolean_output=on  mode=Upper Bit Location + Width  bit1=0  base1=MSB of Input  bit0=0  base0=LSB of Input  dbl_ovrd=off  block_type=slice
  msb_out2 : Outport
  lsb_out1 : Outport  Port=2
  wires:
  bus_in/1 -> slice2/1, slice1/1
  slice2/1 -> msb_out2/1
  slice1/1 -> reinterpret1/1
  reinterpret1/1 -> lsb_out1/1

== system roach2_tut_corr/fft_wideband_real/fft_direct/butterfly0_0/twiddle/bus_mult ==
  a : Inport
  b : Inport  Port=2
  misci : Inport  Port=3
  a*b_bussify : Subsystem  AncestorBlock=casper_library_flow_control/bus_create
  a_debus : Subsystem  AncestorBlock=casper_library_flow_control/bus_expand
  b_debus : Subsystem  AncestorBlock=casper_library_flow_control/bus_expand
  dmisc : xbsIndex_r4/Delay  rst=off  infoeditControl=Selection of Reset will increase slice count due to use of real FFs and instead of SRLs  en=off  latency=mult_latency+add_latency+conv_latency+fan_latency  dbl_ovrd=off  reg_retiming=on  block_type=delay
  mult1 : Subsystem  AncestorBlock=casper_library_multipliers/cmult
  mult2 : Subsystem  AncestorBlock=casper_library_multipliers/cmult
  mult3 : Subsystem  AncestorBlock=casper_library_multipliers/cmult
  mult4 : Subsystem  AncestorBlock=casper_library_multipliers/cmult
  mult5 : Subsystem  AncestorBlock=casper_library_multipliers/cmult
  mult6 : Subsystem  AncestorBlock=casper_library_multipliers/cmult
  mult7 : Subsystem  AncestorBlock=casper_library_multipliers/cmult
  mult8 : Subsystem  AncestorBlock=casper_library_multipliers/cmult
  repa : Subsystem  AncestorBlock=casper_library_bus/bus_replicate
  repb : Subsystem  AncestorBlock=casper_library_bus/bus_replicate
  a*b : Outport
  misco : Outport  Port=2
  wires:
  a/1 -> repa/1(in)
  b/1 -> repb/1(in)
  repa/1(out) -> a_debus/1(bus_in)
  repb/1(out) -> b_debus/1(bus_in)
  a_debus/1(msb_lsb_out1) -> mult1/1(a), mult2/1(a), mult3/1(a), mult4/1(a), mult5/1(a), mult6/1(a), mult7/1(a), mult8/1(a)
  b_debus/1(msb_out8) -> mult1/2(b)
  b_debus/2(out7) -> mult2/2(b)
  b_debus/3(out6) -> mult3/2(b)
  b_debus/4(out5) -> mult4/2(b)
  b_debus/5(out4) -> mult5/2(b)
  b_debus/6(out3) -> mult6/2(b)
  b_debus/7(out2) -> mult7/2(b)
  b_debus/8(lsb_out1) -> mult8/2(b)
  misci/1 -> dmisc/1
  mult1/1(ab) -> a*b_bussify/1(in1)
  mult2/1(ab) -> a*b_bussify/2(in2)
  mult3/1(ab) -> a*b_bussify/3(in3)
  mult4/1(ab) -> a*b_bussify/4(in4)
  mult5/1(ab) -> a*b_bussify/5(in5)
  mult6/1(ab) -> a*b_bussify/6(in6)
  mult7/1(ab) -> a*b_bussify/7(in7)
  mult8/1(ab) -> a*b_bussify/8(in8)
  a*b_bussify/1(bus_out) -> a*b/1
  dmisc/1 -> misco/1

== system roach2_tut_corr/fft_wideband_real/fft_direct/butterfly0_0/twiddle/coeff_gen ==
  rst : Inport
  misci : Inport  Port=2
  Counter : xbsIndex_r4/Counter  cnt_type=Free Running  cnt_to=Inf  operation=Up  start_count=0  cnt_by_val=1  arith_type=Unsigned  n_bits=9  bin_pt=0  load_pin=off  rst=on  en=off  explicit_period=on  period=1  dbl_ovrd=off  use_behavioral_HDL=on  implementation=Fabric  block_type=counter
  Slice : xbsIndex_r4/Slice  nbits=9  boolean_output=off  mode=Upper Bit Location + Width  bit1=0  base1=MSB of Input  bit0=0  base0=LSB of Input  dbl_ovrd=off  block_type=slice
  cosin : Subsystem  Tag=casper:cosin  AncestorBlock=casper_library_downconverter/cosin
  ri_to_c : casper_library_misc/ri_to_c
  w : Outport
  misco : Outport  Port=2
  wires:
  ri_to_c/1 -> w/1
  rst/1 -> Counter/1
  Counter/1 -> Slice/1
  Slice/1 -> cosin/1(theta)
  cosin/1(cos) -> ri_to_c/1
  cosin/2(-sin) -> ri_to_c/2
  misci/1 -> cosin/2(misci)
  cosin/3(misco) -> misco/1

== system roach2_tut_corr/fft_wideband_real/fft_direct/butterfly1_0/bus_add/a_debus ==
  bus_in : Inport
  reinterpret{1..8} (8 alike) : xbsIndex_r4/Reinterpret  force_arith_type=on  arith_type="Signed  (2's comp)"  force_bin_pt=on  bin_pt=17  block_type=reinterpret
  slice1 : xbsIndex_r4/Slice  nbits=18  boolean_output=off  mode=Upper Bit Location + Width  bit1=-126  base1=MSB of Input  bit0=0  base0=LSB of Input  dbl_ovrd=off  block_type=slice
  slice2 : xbsIndex_r4/Slice  nbits=18  boolean_output=off  mode=Upper Bit Location + Width  bit1=-108  base1=MSB of Input  bit0=0  base0=LSB of Input  dbl_ovrd=off  block_type=slice
  slice3 : xbsIndex_r4/Slice  nbits=18  boolean_output=off  mode=Upper Bit Location + Width  bit1=-90  base1=MSB of Input  bit0=0  base0=LSB of Input  dbl_ovrd=off  block_type=slice
  slice4 : xbsIndex_r4/Slice  nbits=18  boolean_output=off  mode=Upper Bit Location + Width  bit1=-72  base1=MSB of Input  bit0=0  base0=LSB of Input  dbl_ovrd=off  block_type=slice
  slice5 : xbsIndex_r4/Slice  nbits=18  boolean_output=off  mode=Upper Bit Location + Width  bit1=-54  base1=MSB of Input  bit0=0  base0=LSB of Input  dbl_ovrd=off  block_type=slice
  slice6 : xbsIndex_r4/Slice  nbits=18  boolean_output=off  mode=Upper Bit Location + Width  bit1=-36  base1=MSB of Input  bit0=0  base0=LSB of Input  dbl_ovrd=off  block_type=slice
  slice7 : xbsIndex_r4/Slice  nbits=18  boolean_output=off  mode=Upper Bit Location + Width  bit1=-18  base1=MSB of Input  bit0=0  base0=LSB of Input  dbl_ovrd=off  block_type=slice
  slice8 : xbsIndex_r4/Slice  nbits=18  boolean_output=off  mode=Upper Bit Location + Width  bit1=0  base1=MSB of Input  bit0=0  base0=LSB of Input  dbl_ovrd=off  block_type=slice
  msb_out8 : Outport
  out7 : Outport  Port=2
  out6 : Outport  Port=3
  out5 : Outport  Port=4
  out4 : Outport  Port=5
  out3 : Outport  Port=6
  out2 : Outport  Port=7
  lsb_out1 : Outport  Port=8
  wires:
  bus_in/1 -> slice8/1, slice7/1, slice6/1, slice5/1, slice4/1, slice3/1, slice2/1, slice1/1
  slice8/1 -> reinterpret8/1
  reinterpret8/1 -> msb_out8/1
  slice7/1 -> reinterpret7/1
  reinterpret7/1 -> out7/1
  slice6/1 -> reinterpret6/1
  reinterpret6/1 -> out6/1
  slice5/1 -> reinterpret5/1
  reinterpret5/1 -> out5/1
  slice4/1 -> reinterpret4/1
  reinterpret4/1 -> out4/1
  slice3/1 -> reinterpret3/1
  reinterpret3/1 -> out3/1
  slice2/1 -> reinterpret2/1
  reinterpret2/1 -> out2/1
  slice1/1 -> reinterpret1/1
  reinterpret1/1 -> lsb_out1/1

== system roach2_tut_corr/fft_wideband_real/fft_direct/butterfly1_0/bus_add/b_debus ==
  bus_in : Inport
  reinterpret{1..8} (8 alike) : xbsIndex_r4/Reinterpret  force_arith_type=on  arith_type="Signed  (2's comp)"  force_bin_pt=on  bin_pt=17  block_type=reinterpret
  slice1 : xbsIndex_r4/Slice  nbits=19  boolean_output=off  mode=Upper Bit Location + Width  bit1=-133  base1=MSB of Input  bit0=0  base0=LSB of Input  dbl_ovrd=off  block_type=slice
  slice2 : xbsIndex_r4/Slice  nbits=19  boolean_output=off  mode=Upper Bit Location + Width  bit1=-114  base1=MSB of Input  bit0=0  base0=LSB of Input  dbl_ovrd=off  block_type=slice
  slice3 : xbsIndex_r4/Slice  nbits=19  boolean_output=off  mode=Upper Bit Location + Width  bit1=-95  base1=MSB of Input  bit0=0  base0=LSB of Input  dbl_ovrd=off  block_type=slice
  slice4 : xbsIndex_r4/Slice  nbits=19  boolean_output=off  mode=Upper Bit Location + Width  bit1=-76  base1=MSB of Input  bit0=0  base0=LSB of Input  dbl_ovrd=off  block_type=slice
  slice5 : xbsIndex_r4/Slice  nbits=19  boolean_output=off  mode=Upper Bit Location + Width  bit1=-57  base1=MSB of Input  bit0=0  base0=LSB of Input  dbl_ovrd=off  block_type=slice
  slice6 : xbsIndex_r4/Slice  nbits=19  boolean_output=off  mode=Upper Bit Location + Width  bit1=-38  base1=MSB of Input  bit0=0  base0=LSB of Input  dbl_ovrd=off  block_type=slice
  slice7 : xbsIndex_r4/Slice  nbits=19  boolean_output=off  mode=Upper Bit Location + Width  bit1=-19  base1=MSB of Input  bit0=0  base0=LSB of Input  dbl_ovrd=off  block_type=slice
  slice8 : xbsIndex_r4/Slice  nbits=19  boolean_output=off  mode=Upper Bit Location + Width  bit1=0  base1=MSB of Input  bit0=0  base0=LSB of Input  dbl_ovrd=off  block_type=slice
  msb_out8 : Outport
  out7 : Outport  Port=2
  out6 : Outport  Port=3
  out5 : Outport  Port=4
  out4 : Outport  Port=5
  out3 : Outport  Port=6
  out2 : Outport  Port=7
  lsb_out1 : Outport  Port=8
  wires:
  bus_in/1 -> slice8/1, slice7/1, slice6/1, slice5/1, slice4/1, slice3/1, slice2/1, slice1/1
  slice8/1 -> reinterpret8/1
  reinterpret8/1 -> msb_out8/1
  slice7/1 -> reinterpret7/1
  reinterpret7/1 -> out7/1
  slice6/1 -> reinterpret6/1
  reinterpret6/1 -> out6/1
  slice5/1 -> reinterpret5/1
  reinterpret5/1 -> out5/1
  slice4/1 -> reinterpret4/1
  reinterpret4/1 -> out4/1
  slice3/1 -> reinterpret3/1
  reinterpret3/1 -> out3/1
  slice2/1 -> reinterpret2/1
  reinterpret2/1 -> out2/1
  slice1/1 -> reinterpret1/1
  reinterpret1/1 -> lsb_out1/1

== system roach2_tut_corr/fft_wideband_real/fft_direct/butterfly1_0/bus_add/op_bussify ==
  in1 : Inport
  in2 : Inport  Port=2
  in3 : Inport  Port=3
  in4 : Inport  Port=4
  in5 : Inport  Port=5
  in6 : Inport  Port=6
  in7 : Inport  Port=7
  in8 : Inport  Port=8
  concatenate : xbsIndex_r4/Concat  num_inputs=8  dbl_ovrd=off  block_type=concat
  reinterpret{1..8} (8 alike) : xbsIndex_r4/Reinterpret  force_arith_type=on  arith_type=Unsigned  force_bin_pt=on  bin_pt=0  block_type=reinterpret
  bus_out : Outport
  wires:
  concatenate/1 -> bus_out/1
  in1/1 -> reinterpret1/1
  reinterpret1/1 -> concatenate/1
  in2/1 -> reinterpret2/1
  reinterpret2/1 -> concatenate/2
  in3/1 -> reinterpret3/1
  reinterpret3/1 -> concatenate/3
  in4/1 -> reinterpret4/1
  reinterpret4/1 -> concatenate/4
  in5/1 -> reinterpret5/1
  reinterpret5/1 -> concatenate/5
  in6/1 -> reinterpret6/1
  reinterpret6/1 -> concatenate/6
  in7/1 -> reinterpret7/1
  reinterpret7/1 -> concatenate/7
  in8/1 -> reinterpret8/1
  reinterpret8/1 -> concatenate/8
